VERSION 5.7 ;
  NOWIREEXTENSIONATPIN ON ;
  DIVIDERCHAR "/" ;
  BUSBITCHARS "[]" ;
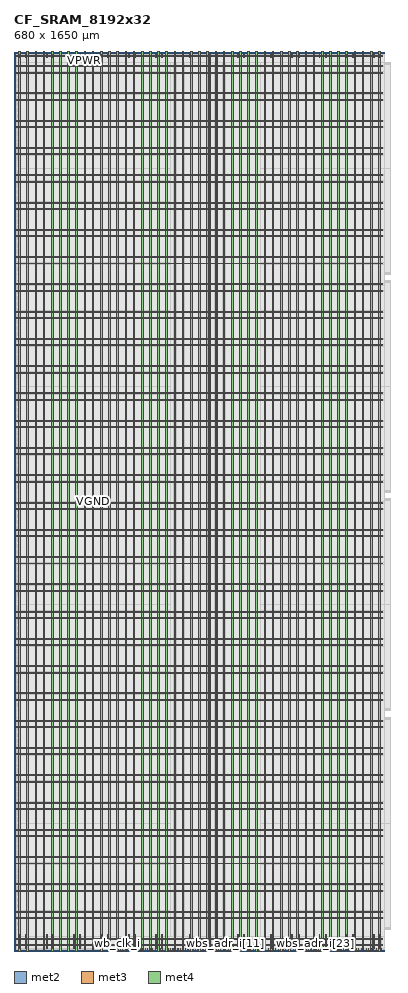
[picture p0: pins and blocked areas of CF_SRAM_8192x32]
MACRO CF_SRAM_8192x32
  CLASS BLOCK ;
  FOREIGN CF_SRAM_8192x32 ;
  ORIGIN 0.000 0.000 ;
  SIZE 680.000 BY 1650.000 ;
  PIN VGND
    DIRECTION INOUT ;
    USE GROUND ;
    PORT
      LAYER met2 ;
        RECT 20.940 5.200 22.700 29.860 ;
    END
    PORT
      LAYER met2 ;
        RECT 20.940 1638.310 22.700 1643.120 ;
    END
    PORT
      LAYER met2 ;
        RECT 70.940 5.200 72.700 29.860 ;
    END
    PORT
      LAYER met2 ;
        RECT 70.940 1638.310 72.700 1643.120 ;
    END
    PORT
      LAYER met2 ;
        RECT 120.940 5.200 122.700 29.860 ;
    END
    PORT
      LAYER met2 ;
        RECT 120.940 1638.310 122.700 1643.120 ;
    END
    PORT
      LAYER met2 ;
        RECT 170.940 5.200 172.700 29.860 ;
    END
    PORT
      LAYER met2 ;
        RECT 170.940 1638.310 172.700 1643.120 ;
    END
    PORT
      LAYER met2 ;
        RECT 220.940 5.200 222.700 29.860 ;
    END
    PORT
      LAYER met2 ;
        RECT 220.940 1638.310 222.700 1643.120 ;
    END
    PORT
      LAYER met2 ;
        RECT 270.940 5.200 272.700 29.720 ;
    END
    PORT
      LAYER met2 ;
        RECT 270.940 1638.450 272.700 1643.120 ;
    END
    PORT
      LAYER met2 ;
        RECT 320.940 5.200 322.700 29.860 ;
    END
    PORT
      LAYER met2 ;
        RECT 320.940 1638.310 322.700 1643.120 ;
    END
    PORT
      LAYER met2 ;
        RECT 370.940 5.200 372.700 1643.120 ;
    END
    PORT
      LAYER met2 ;
        RECT 420.940 5.200 422.700 29.720 ;
    END
    PORT
      LAYER met2 ;
        RECT 420.940 1638.450 422.700 1643.120 ;
    END
    PORT
      LAYER met2 ;
        RECT 470.940 5.200 472.700 29.720 ;
    END
    PORT
      LAYER met2 ;
        RECT 470.940 1638.450 472.700 1643.120 ;
    END
    PORT
      LAYER met2 ;
        RECT 520.940 5.200 522.700 29.860 ;
    END
    PORT
      LAYER met2 ;
        RECT 520.940 1638.310 522.700 1643.120 ;
    END
    PORT
      LAYER met2 ;
        RECT 570.940 5.200 572.700 29.860 ;
    END
    PORT
      LAYER met2 ;
        RECT 570.940 1638.310 572.700 1643.120 ;
    END
    PORT
      LAYER met2 ;
        RECT 620.940 5.200 622.700 29.860 ;
    END
    PORT
      LAYER met2 ;
        RECT 620.940 1638.310 622.700 1643.120 ;
    END
    PORT
      LAYER met2 ;
        RECT 670.940 5.200 672.700 29.860 ;
    END
    PORT
      LAYER met2 ;
        RECT 670.940 1638.310 672.700 1643.120 ;
    END
    PORT
      LAYER met3 ;
        RECT 4.820 21.320 675.060 23.080 ;
    END
    PORT
      LAYER met3 ;
        RECT 4.820 71.320 675.060 73.080 ;
    END
    PORT
      LAYER met3 ;
        RECT 4.820 121.320 675.060 123.080 ;
    END
    PORT
      LAYER met3 ;
        RECT 4.820 171.320 675.060 173.080 ;
    END
    PORT
      LAYER met3 ;
        RECT 4.820 221.320 675.060 223.080 ;
    END
    PORT
      LAYER met3 ;
        RECT 4.820 271.320 675.060 273.080 ;
    END
    PORT
      LAYER met3 ;
        RECT 4.820 321.320 675.060 323.080 ;
    END
    PORT
      LAYER met3 ;
        RECT 4.820 371.320 675.060 373.080 ;
    END
    PORT
      LAYER met3 ;
        RECT 4.820 421.320 675.060 423.080 ;
    END
    PORT
      LAYER met3 ;
        RECT 4.820 471.320 675.060 473.080 ;
    END
    PORT
      LAYER met3 ;
        RECT 4.820 521.320 675.060 523.080 ;
    END
    PORT
      LAYER met3 ;
        RECT 4.820 571.320 675.060 573.080 ;
    END
    PORT
      LAYER met3 ;
        RECT 4.820 621.320 675.060 623.080 ;
    END
    PORT
      LAYER met3 ;
        RECT 4.820 671.320 675.060 673.080 ;
    END
    PORT
      LAYER met3 ;
        RECT 4.820 721.320 675.060 723.080 ;
    END
    PORT
      LAYER met3 ;
        RECT 4.820 771.320 675.060 773.080 ;
    END
    PORT
      LAYER met3 ;
        RECT 4.820 821.320 675.060 823.080 ;
    END
    PORT
      LAYER met3 ;
        RECT 4.820 871.320 675.060 873.080 ;
    END
    PORT
      LAYER met3 ;
        RECT 4.820 921.320 675.060 923.080 ;
    END
    PORT
      LAYER met3 ;
        RECT 4.820 971.320 675.060 973.080 ;
    END
    PORT
      LAYER met3 ;
        RECT 4.820 1021.320 675.060 1023.080 ;
    END
    PORT
      LAYER met3 ;
        RECT 4.820 1071.320 675.060 1073.080 ;
    END
    PORT
      LAYER met3 ;
        RECT 4.820 1121.320 675.060 1123.080 ;
    END
    PORT
      LAYER met3 ;
        RECT 4.820 1171.320 675.060 1173.080 ;
    END
    PORT
      LAYER met3 ;
        RECT 4.820 1221.320 675.060 1223.080 ;
    END
    PORT
      LAYER met3 ;
        RECT 4.820 1271.320 675.060 1273.080 ;
    END
    PORT
      LAYER met3 ;
        RECT 4.820 1321.320 675.060 1323.080 ;
    END
    PORT
      LAYER met3 ;
        RECT 4.820 1371.320 675.060 1373.080 ;
    END
    PORT
      LAYER met3 ;
        RECT 4.820 1421.320 675.060 1423.080 ;
    END
    PORT
      LAYER met3 ;
        RECT 4.820 1471.320 675.060 1473.080 ;
    END
    PORT
      LAYER met3 ;
        RECT 4.820 1521.320 675.060 1523.080 ;
    END
    PORT
      LAYER met3 ;
        RECT 4.820 1571.320 675.060 1573.080 ;
    END
    PORT
      LAYER met3 ;
        RECT 4.820 1621.320 675.060 1623.080 ;
    END
    PORT
      LAYER met4 ;
        RECT 23.510 0.000 26.610 1650.000 ;
    END
    PORT
      LAYER met4 ;
        RECT 53.510 0.000 56.610 1650.000 ;
    END
    PORT
      LAYER met4 ;
        RECT 83.510 0.000 86.610 1650.000 ;
    END
    PORT
      LAYER met4 ;
        RECT 113.510 0.000 116.610 1650.000 ;
    END
    PORT
      LAYER met4 ;
        RECT 143.510 0.000 146.610 1650.000 ;
    END
    PORT
      LAYER met4 ;
        RECT 173.510 0.000 176.610 1650.000 ;
    END
    PORT
      LAYER met4 ;
        RECT 203.510 0.000 206.610 1650.000 ;
    END
    PORT
      LAYER met4 ;
        RECT 233.510 0.000 236.610 1650.000 ;
    END
    PORT
      LAYER met4 ;
        RECT 263.510 0.000 266.610 1650.000 ;
    END
    PORT
      LAYER met4 ;
        RECT 293.510 0.000 296.610 1650.000 ;
    END
    PORT
      LAYER met4 ;
        RECT 323.510 0.000 326.610 1650.000 ;
    END
    PORT
      LAYER met4 ;
        RECT 353.510 0.000 356.610 1650.000 ;
    END
    PORT
      LAYER met4 ;
        RECT 383.510 0.000 386.610 1650.000 ;
    END
    PORT
      LAYER met4 ;
        RECT 413.510 0.000 416.610 1650.000 ;
    END
    PORT
      LAYER met4 ;
        RECT 443.510 0.000 446.610 1650.000 ;
    END
    PORT
      LAYER met4 ;
        RECT 473.510 0.000 476.610 1650.000 ;
    END
    PORT
      LAYER met4 ;
        RECT 503.510 0.000 506.610 1650.000 ;
    END
    PORT
      LAYER met4 ;
        RECT 533.510 0.000 536.610 1650.000 ;
    END
    PORT
      LAYER met4 ;
        RECT 563.510 0.000 566.610 1650.000 ;
    END
    PORT
      LAYER met4 ;
        RECT 593.510 0.000 596.610 1650.000 ;
    END
    PORT
      LAYER met4 ;
        RECT 623.510 0.000 626.610 1650.000 ;
    END
    PORT
      LAYER met4 ;
        RECT 653.510 0.000 656.610 1650.000 ;
    END
    PORT
      LAYER met3 ;
        RECT 4.820 1639.380 675.060 1640.260 ;
    END
  END VGND
  PIN VPWR
    DIRECTION INOUT ;
    USE POWER ;
    PORT
      LAYER met2 ;
        RECT 9.180 5.200 10.940 29.720 ;
    END
    PORT
      LAYER met2 ;
        RECT 9.180 1638.450 10.940 1643.120 ;
    END
    PORT
      LAYER met2 ;
        RECT 59.180 5.200 60.940 29.860 ;
    END
    PORT
      LAYER met2 ;
        RECT 59.180 1638.310 60.940 1643.120 ;
    END
    PORT
      LAYER met2 ;
        RECT 109.180 5.200 110.940 29.860 ;
    END
    PORT
      LAYER met2 ;
        RECT 109.180 1638.310 110.940 1643.120 ;
    END
    PORT
      LAYER met2 ;
        RECT 159.180 5.200 160.940 29.860 ;
    END
    PORT
      LAYER met2 ;
        RECT 159.180 1638.310 160.940 1643.120 ;
    END
    PORT
      LAYER met2 ;
        RECT 209.180 5.200 210.940 29.860 ;
    END
    PORT
      LAYER met2 ;
        RECT 209.180 1638.310 210.940 1643.120 ;
    END
    PORT
      LAYER met2 ;
        RECT 259.180 5.200 260.940 29.720 ;
    END
    PORT
      LAYER met2 ;
        RECT 259.180 1638.450 260.940 1643.120 ;
    END
    PORT
      LAYER met2 ;
        RECT 309.180 5.200 310.940 29.860 ;
    END
    PORT
      LAYER met2 ;
        RECT 309.180 1638.310 310.940 1643.120 ;
    END
    PORT
      LAYER met2 ;
        RECT 359.180 5.200 360.940 1643.120 ;
    END
    PORT
      LAYER met2 ;
        RECT 409.180 5.200 410.940 29.860 ;
    END
    PORT
      LAYER met2 ;
        RECT 409.180 1638.310 410.940 1643.120 ;
    END
    PORT
      LAYER met2 ;
        RECT 459.180 5.200 460.940 29.720 ;
    END
    PORT
      LAYER met2 ;
        RECT 459.180 1638.450 460.940 1643.120 ;
    END
    PORT
      LAYER met2 ;
        RECT 509.180 5.200 510.940 29.860 ;
    END
    PORT
      LAYER met2 ;
        RECT 509.180 1638.310 510.940 1643.120 ;
    END
    PORT
      LAYER met2 ;
        RECT 559.180 5.200 560.940 29.860 ;
    END
    PORT
      LAYER met2 ;
        RECT 559.180 1638.310 560.940 1643.120 ;
    END
    PORT
      LAYER met2 ;
        RECT 609.180 5.200 610.940 29.860 ;
    END
    PORT
      LAYER met2 ;
        RECT 609.180 1638.310 610.940 1643.120 ;
    END
    PORT
      LAYER met2 ;
        RECT 659.180 5.200 660.940 29.860 ;
    END
    PORT
      LAYER met2 ;
        RECT 659.180 1638.310 660.940 1643.120 ;
    END
    PORT
      LAYER met3 ;
        RECT 4.820 9.560 675.060 11.320 ;
    END
    PORT
      LAYER met3 ;
        RECT 4.820 59.560 675.060 61.320 ;
    END
    PORT
      LAYER met3 ;
        RECT 4.820 109.560 675.060 111.320 ;
    END
    PORT
      LAYER met3 ;
        RECT 4.820 159.560 675.060 161.320 ;
    END
    PORT
      LAYER met3 ;
        RECT 4.820 209.560 675.060 211.320 ;
    END
    PORT
      LAYER met3 ;
        RECT 4.820 259.560 675.060 261.320 ;
    END
    PORT
      LAYER met3 ;
        RECT 4.820 309.560 675.060 311.320 ;
    END
    PORT
      LAYER met3 ;
        RECT 4.820 359.560 675.060 361.320 ;
    END
    PORT
      LAYER met3 ;
        RECT 4.820 409.560 675.060 411.320 ;
    END
    PORT
      LAYER met3 ;
        RECT 4.820 459.560 675.060 461.320 ;
    END
    PORT
      LAYER met3 ;
        RECT 4.820 509.560 675.060 511.320 ;
    END
    PORT
      LAYER met3 ;
        RECT 4.820 559.560 675.060 561.320 ;
    END
    PORT
      LAYER met3 ;
        RECT 4.820 609.560 675.060 611.320 ;
    END
    PORT
      LAYER met3 ;
        RECT 4.820 659.560 675.060 661.320 ;
    END
    PORT
      LAYER met3 ;
        RECT 4.820 709.560 675.060 711.320 ;
    END
    PORT
      LAYER met3 ;
        RECT 4.820 759.560 675.060 761.320 ;
    END
    PORT
      LAYER met3 ;
        RECT 4.820 809.560 675.060 811.320 ;
    END
    PORT
      LAYER met3 ;
        RECT 4.820 859.560 675.060 861.320 ;
    END
    PORT
      LAYER met3 ;
        RECT 4.820 909.560 675.060 911.320 ;
    END
    PORT
      LAYER met3 ;
        RECT 4.820 959.560 675.060 961.320 ;
    END
    PORT
      LAYER met3 ;
        RECT 4.820 1009.560 675.060 1011.320 ;
    END
    PORT
      LAYER met3 ;
        RECT 4.820 1059.560 675.060 1061.320 ;
    END
    PORT
      LAYER met3 ;
        RECT 4.820 1109.560 675.060 1111.320 ;
    END
    PORT
      LAYER met3 ;
        RECT 4.820 1159.560 675.060 1161.320 ;
    END
    PORT
      LAYER met3 ;
        RECT 4.820 1209.560 675.060 1211.320 ;
    END
    PORT
      LAYER met3 ;
        RECT 4.820 1259.560 675.060 1261.320 ;
    END
    PORT
      LAYER met3 ;
        RECT 4.820 1309.560 675.060 1311.320 ;
    END
    PORT
      LAYER met3 ;
        RECT 4.820 1359.560 675.060 1361.320 ;
    END
    PORT
      LAYER met3 ;
        RECT 4.820 1409.560 675.060 1411.320 ;
    END
    PORT
      LAYER met3 ;
        RECT 4.820 1459.560 675.060 1461.320 ;
    END
    PORT
      LAYER met3 ;
        RECT 4.820 1509.560 675.060 1511.320 ;
    END
    PORT
      LAYER met3 ;
        RECT 4.820 1559.560 675.060 1561.320 ;
    END
    PORT
      LAYER met3 ;
        RECT 4.820 1609.560 675.060 1611.320 ;
    END
    PORT
      LAYER met4 ;
        RECT 8.510 0.000 11.610 1650.000 ;
    END
    PORT
      LAYER met4 ;
        RECT 38.510 0.000 41.610 1650.000 ;
    END
    PORT
      LAYER met4 ;
        RECT 68.510 0.000 71.610 1650.000 ;
    END
    PORT
      LAYER met4 ;
        RECT 98.510 0.000 101.610 1650.000 ;
    END
    PORT
      LAYER met4 ;
        RECT 128.510 0.000 131.610 1650.000 ;
    END
    PORT
      LAYER met4 ;
        RECT 158.510 0.000 161.610 1650.000 ;
    END
    PORT
      LAYER met4 ;
        RECT 188.510 0.000 191.610 1650.000 ;
    END
    PORT
      LAYER met4 ;
        RECT 218.510 0.000 221.610 1650.000 ;
    END
    PORT
      LAYER met4 ;
        RECT 248.510 0.000 251.610 1650.000 ;
    END
    PORT
      LAYER met4 ;
        RECT 278.510 0.000 281.610 1650.000 ;
    END
    PORT
      LAYER met4 ;
        RECT 308.510 0.000 311.610 1650.000 ;
    END
    PORT
      LAYER met4 ;
        RECT 338.510 0.000 341.610 1650.000 ;
    END
    PORT
      LAYER met4 ;
        RECT 368.510 0.000 371.610 1650.000 ;
    END
    PORT
      LAYER met4 ;
        RECT 398.510 0.000 401.610 1650.000 ;
    END
    PORT
      LAYER met4 ;
        RECT 428.510 0.000 431.610 1650.000 ;
    END
    PORT
      LAYER met4 ;
        RECT 458.510 0.000 461.610 1650.000 ;
    END
    PORT
      LAYER met4 ;
        RECT 488.510 0.000 491.610 1650.000 ;
    END
    PORT
      LAYER met4 ;
        RECT 518.510 0.000 521.610 1650.000 ;
    END
    PORT
      LAYER met4 ;
        RECT 548.510 0.000 551.610 1650.000 ;
    END
    PORT
      LAYER met4 ;
        RECT 578.510 0.000 581.610 1650.000 ;
    END
    PORT
      LAYER met4 ;
        RECT 608.510 0.000 611.610 1650.000 ;
    END
    PORT
      LAYER met4 ;
        RECT 638.510 0.000 641.610 1650.000 ;
    END
    PORT
      LAYER met4 ;
        RECT 668.510 0.000 671.610 1650.000 ;
    END
    PORT
      LAYER met3 ;
        RECT 4.820 1640.740 675.060 1641.620 ;
    END
  END VPWR
  PIN wb_clk_i
    DIRECTION INPUT ;
    USE SIGNAL ;
    ANTENNAGATEAREA 1.286700 ;
    ANTENNADIFFAREA 0.434700 ;
    PORT
      LAYER met2 ;
        RECT 190.070 0.000 190.350 4.000 ;
    END
  END wb_clk_i
  PIN wb_rst_i
    DIRECTION INPUT ;
    USE SIGNAL ;
    ANTENNAGATEAREA 0.196500 ;
    PORT
      LAYER met2 ;
        RECT 194.670 0.000 194.950 4.000 ;
    END
  END wb_rst_i
  PIN wbs_ack_o
    DIRECTION OUTPUT ;
    USE SIGNAL ;
    ANTENNADIFFAREA 2.673000 ;
    PORT
      LAYER met2 ;
        RECT 199.270 0.000 199.550 4.000 ;
    END
  END wbs_ack_o
  PIN wbs_adr_i[0]
    DIRECTION INPUT ;
    USE SIGNAL ;
    PORT
      LAYER met2 ;
        RECT 217.670 0.000 217.950 4.000 ;
    END
  END wbs_adr_i[0]
  PIN wbs_adr_i[10]
    DIRECTION INPUT ;
    USE SIGNAL ;
    ANTENNAGATEAREA 0.126000 ;
    PORT
      LAYER met2 ;
        RECT 374.070 0.000 374.350 4.000 ;
    END
  END wbs_adr_i[10]
  PIN wbs_adr_i[11]
    DIRECTION INPUT ;
    USE SIGNAL ;
    ANTENNAGATEAREA 0.126000 ;
    PORT
      LAYER met2 ;
        RECT 387.870 0.000 388.150 4.000 ;
    END
  END wbs_adr_i[11]
  PIN wbs_adr_i[12]
    DIRECTION INPUT ;
    USE SIGNAL ;
    ANTENNAGATEAREA 0.126000 ;
    PORT
      LAYER met2 ;
        RECT 401.670 0.000 401.950 4.000 ;
    END
  END wbs_adr_i[12]
  PIN wbs_adr_i[13]
    DIRECTION INPUT ;
    USE SIGNAL ;
    ANTENNAGATEAREA 0.126000 ;
    PORT
      LAYER met2 ;
        RECT 415.470 0.000 415.750 4.000 ;
    END
  END wbs_adr_i[13]
  PIN wbs_adr_i[14]
    DIRECTION INPUT ;
    USE SIGNAL ;
    ANTENNAGATEAREA 0.126000 ;
    PORT
      LAYER met2 ;
        RECT 429.270 0.000 429.550 4.000 ;
    END
  END wbs_adr_i[14]
  PIN wbs_adr_i[15]
    DIRECTION INPUT ;
    USE SIGNAL ;
    PORT
      LAYER met2 ;
        RECT 443.070 0.000 443.350 4.000 ;
    END
  END wbs_adr_i[15]
  PIN wbs_adr_i[16]
    DIRECTION INPUT ;
    USE SIGNAL ;
    PORT
      LAYER met2 ;
        RECT 456.870 0.000 457.150 4.000 ;
    END
  END wbs_adr_i[16]
  PIN wbs_adr_i[17]
    DIRECTION INPUT ;
    USE SIGNAL ;
    PORT
      LAYER met2 ;
        RECT 470.670 0.000 470.950 4.000 ;
    END
  END wbs_adr_i[17]
  PIN wbs_adr_i[18]
    DIRECTION INPUT ;
    USE SIGNAL ;
    PORT
      LAYER met2 ;
        RECT 484.470 0.000 484.750 4.000 ;
    END
  END wbs_adr_i[18]
  PIN wbs_adr_i[19]
    DIRECTION INPUT ;
    USE SIGNAL ;
    PORT
      LAYER met2 ;
        RECT 498.270 0.000 498.550 4.000 ;
    END
  END wbs_adr_i[19]
  PIN wbs_adr_i[1]
    DIRECTION INPUT ;
    USE SIGNAL ;
    PORT
      LAYER met2 ;
        RECT 236.070 0.000 236.350 4.000 ;
    END
  END wbs_adr_i[1]
  PIN wbs_adr_i[20]
    DIRECTION INPUT ;
    USE SIGNAL ;
    PORT
      LAYER met2 ;
        RECT 512.070 0.000 512.350 4.000 ;
    END
  END wbs_adr_i[20]
  PIN wbs_adr_i[21]
    DIRECTION INPUT ;
    USE SIGNAL ;
    PORT
      LAYER met2 ;
        RECT 525.870 0.000 526.150 4.000 ;
    END
  END wbs_adr_i[21]
  PIN wbs_adr_i[22]
    DIRECTION INPUT ;
    USE SIGNAL ;
    PORT
      LAYER met2 ;
        RECT 539.670 0.000 539.950 4.000 ;
    END
  END wbs_adr_i[22]
  PIN wbs_adr_i[23]
    DIRECTION INPUT ;
    USE SIGNAL ;
    PORT
      LAYER met2 ;
        RECT 553.470 0.000 553.750 4.000 ;
    END
  END wbs_adr_i[23]
  PIN wbs_adr_i[24]
    DIRECTION INPUT ;
    USE SIGNAL ;
    PORT
      LAYER met2 ;
        RECT 567.270 0.000 567.550 4.000 ;
    END
  END wbs_adr_i[24]
  PIN wbs_adr_i[25]
    DIRECTION INPUT ;
    USE SIGNAL ;
    PORT
      LAYER met2 ;
        RECT 581.070 0.000 581.350 4.000 ;
    END
  END wbs_adr_i[25]
  PIN wbs_adr_i[26]
    DIRECTION INPUT ;
    USE SIGNAL ;
    PORT
      LAYER met2 ;
        RECT 594.870 0.000 595.150 4.000 ;
    END
  END wbs_adr_i[26]
  PIN wbs_adr_i[27]
    DIRECTION INPUT ;
    USE SIGNAL ;
    PORT
      LAYER met2 ;
        RECT 608.670 0.000 608.950 4.000 ;
    END
  END wbs_adr_i[27]
  PIN wbs_adr_i[28]
    DIRECTION INPUT ;
    USE SIGNAL ;
    PORT
      LAYER met2 ;
        RECT 622.470 0.000 622.750 4.000 ;
    END
  END wbs_adr_i[28]
  PIN wbs_adr_i[29]
    DIRECTION INPUT ;
    USE SIGNAL ;
    PORT
      LAYER met2 ;
        RECT 636.270 0.000 636.550 4.000 ;
    END
  END wbs_adr_i[29]
  PIN wbs_adr_i[2]
    DIRECTION INPUT ;
    USE SIGNAL ;
    ANTENNAGATEAREA 0.126000 ;
    PORT
      LAYER met2 ;
        RECT 254.470 0.000 254.750 4.000 ;
    END
  END wbs_adr_i[2]
  PIN wbs_adr_i[30]
    DIRECTION INPUT ;
    USE SIGNAL ;
    PORT
      LAYER met2 ;
        RECT 650.070 0.000 650.350 4.000 ;
    END
  END wbs_adr_i[30]
  PIN wbs_adr_i[31]
    DIRECTION INPUT ;
    USE SIGNAL ;
    PORT
      LAYER met2 ;
        RECT 663.870 0.000 664.150 4.000 ;
    END
  END wbs_adr_i[31]
  PIN wbs_adr_i[3]
    DIRECTION INPUT ;
    USE SIGNAL ;
    ANTENNAGATEAREA 0.126000 ;
    PORT
      LAYER met2 ;
        RECT 272.870 0.000 273.150 4.000 ;
    END
  END wbs_adr_i[3]
  PIN wbs_adr_i[4]
    DIRECTION INPUT ;
    USE SIGNAL ;
    ANTENNAGATEAREA 0.126000 ;
    PORT
      LAYER met2 ;
        RECT 291.270 0.000 291.550 4.000 ;
    END
  END wbs_adr_i[4]
  PIN wbs_adr_i[5]
    DIRECTION INPUT ;
    USE SIGNAL ;
    ANTENNAGATEAREA 0.126000 ;
    PORT
      LAYER met2 ;
        RECT 305.070 0.000 305.350 4.000 ;
    END
  END wbs_adr_i[5]
  PIN wbs_adr_i[6]
    DIRECTION INPUT ;
    USE SIGNAL ;
    ANTENNAGATEAREA 0.126000 ;
    PORT
      LAYER met2 ;
        RECT 318.870 0.000 319.150 4.000 ;
    END
  END wbs_adr_i[6]
  PIN wbs_adr_i[7]
    DIRECTION INPUT ;
    USE SIGNAL ;
    ANTENNAGATEAREA 0.126000 ;
    PORT
      LAYER met2 ;
        RECT 332.670 0.000 332.950 4.000 ;
    END
  END wbs_adr_i[7]
  PIN wbs_adr_i[8]
    DIRECTION INPUT ;
    USE SIGNAL ;
    ANTENNAGATEAREA 0.126000 ;
    PORT
      LAYER met2 ;
        RECT 346.470 0.000 346.750 4.000 ;
    END
  END wbs_adr_i[8]
  PIN wbs_adr_i[9]
    DIRECTION INPUT ;
    USE SIGNAL ;
    ANTENNAGATEAREA 0.126000 ;
    PORT
      LAYER met2 ;
        RECT 360.270 0.000 360.550 4.000 ;
    END
  END wbs_adr_i[9]
  PIN wbs_cyc_i
    DIRECTION INPUT ;
    USE SIGNAL ;
    ANTENNAGATEAREA 0.126000 ;
    PORT
      LAYER met2 ;
        RECT 203.870 0.000 204.150 4.000 ;
    END
  END wbs_cyc_i
  PIN wbs_dat_i[0]
    DIRECTION INPUT ;
    USE SIGNAL ;
    ANTENNAGATEAREA 0.126000 ;
    PORT
      LAYER met2 ;
        RECT 222.270 0.000 222.550 4.000 ;
    END
  END wbs_dat_i[0]
  PIN wbs_dat_i[10]
    DIRECTION INPUT ;
    USE SIGNAL ;
    ANTENNAGATEAREA 0.126000 ;
    PORT
      LAYER met2 ;
        RECT 378.670 0.000 378.950 4.000 ;
    END
  END wbs_dat_i[10]
  PIN wbs_dat_i[11]
    DIRECTION INPUT ;
    USE SIGNAL ;
    ANTENNAGATEAREA 0.126000 ;
    PORT
      LAYER met2 ;
        RECT 392.470 0.000 392.750 4.000 ;
    END
  END wbs_dat_i[11]
  PIN wbs_dat_i[12]
    DIRECTION INPUT ;
    USE SIGNAL ;
    ANTENNAGATEAREA 0.126000 ;
    PORT
      LAYER met2 ;
        RECT 406.270 0.000 406.550 4.000 ;
    END
  END wbs_dat_i[12]
  PIN wbs_dat_i[13]
    DIRECTION INPUT ;
    USE SIGNAL ;
    ANTENNAGATEAREA 0.126000 ;
    PORT
      LAYER met2 ;
        RECT 420.070 0.000 420.350 4.000 ;
    END
  END wbs_dat_i[13]
  PIN wbs_dat_i[14]
    DIRECTION INPUT ;
    USE SIGNAL ;
    ANTENNAGATEAREA 0.126000 ;
    PORT
      LAYER met2 ;
        RECT 433.870 0.000 434.150 4.000 ;
    END
  END wbs_dat_i[14]
  PIN wbs_dat_i[15]
    DIRECTION INPUT ;
    USE SIGNAL ;
    ANTENNAGATEAREA 0.126000 ;
    PORT
      LAYER met2 ;
        RECT 447.670 0.000 447.950 4.000 ;
    END
  END wbs_dat_i[15]
  PIN wbs_dat_i[16]
    DIRECTION INPUT ;
    USE SIGNAL ;
    ANTENNAGATEAREA 0.126000 ;
    PORT
      LAYER met2 ;
        RECT 461.470 0.000 461.750 4.000 ;
    END
  END wbs_dat_i[16]
  PIN wbs_dat_i[17]
    DIRECTION INPUT ;
    USE SIGNAL ;
    ANTENNAGATEAREA 0.126000 ;
    PORT
      LAYER met2 ;
        RECT 475.270 0.000 475.550 4.000 ;
    END
  END wbs_dat_i[17]
  PIN wbs_dat_i[18]
    DIRECTION INPUT ;
    USE SIGNAL ;
    ANTENNAGATEAREA 0.126000 ;
    PORT
      LAYER met2 ;
        RECT 489.070 0.000 489.350 4.000 ;
    END
  END wbs_dat_i[18]
  PIN wbs_dat_i[19]
    DIRECTION INPUT ;
    USE SIGNAL ;
    ANTENNAGATEAREA 0.126000 ;
    PORT
      LAYER met2 ;
        RECT 502.870 0.000 503.150 4.000 ;
    END
  END wbs_dat_i[19]
  PIN wbs_dat_i[1]
    DIRECTION INPUT ;
    USE SIGNAL ;
    ANTENNAGATEAREA 0.126000 ;
    PORT
      LAYER met2 ;
        RECT 240.670 0.000 240.950 4.000 ;
    END
  END wbs_dat_i[1]
  PIN wbs_dat_i[20]
    DIRECTION INPUT ;
    USE SIGNAL ;
    ANTENNAGATEAREA 0.126000 ;
    PORT
      LAYER met2 ;
        RECT 516.670 0.000 516.950 4.000 ;
    END
  END wbs_dat_i[20]
  PIN wbs_dat_i[21]
    DIRECTION INPUT ;
    USE SIGNAL ;
    ANTENNAGATEAREA 0.126000 ;
    PORT
      LAYER met2 ;
        RECT 530.470 0.000 530.750 4.000 ;
    END
  END wbs_dat_i[21]
  PIN wbs_dat_i[22]
    DIRECTION INPUT ;
    USE SIGNAL ;
    ANTENNAGATEAREA 0.126000 ;
    PORT
      LAYER met2 ;
        RECT 544.270 0.000 544.550 4.000 ;
    END
  END wbs_dat_i[22]
  PIN wbs_dat_i[23]
    DIRECTION INPUT ;
    USE SIGNAL ;
    ANTENNAGATEAREA 0.126000 ;
    PORT
      LAYER met2 ;
        RECT 558.070 0.000 558.350 4.000 ;
    END
  END wbs_dat_i[23]
  PIN wbs_dat_i[24]
    DIRECTION INPUT ;
    USE SIGNAL ;
    ANTENNAGATEAREA 0.126000 ;
    PORT
      LAYER met2 ;
        RECT 571.870 0.000 572.150 4.000 ;
    END
  END wbs_dat_i[24]
  PIN wbs_dat_i[25]
    DIRECTION INPUT ;
    USE SIGNAL ;
    ANTENNAGATEAREA 0.126000 ;
    PORT
      LAYER met2 ;
        RECT 585.670 0.000 585.950 4.000 ;
    END
  END wbs_dat_i[25]
  PIN wbs_dat_i[26]
    DIRECTION INPUT ;
    USE SIGNAL ;
    ANTENNAGATEAREA 0.126000 ;
    PORT
      LAYER met2 ;
        RECT 599.470 0.000 599.750 4.000 ;
    END
  END wbs_dat_i[26]
  PIN wbs_dat_i[27]
    DIRECTION INPUT ;
    USE SIGNAL ;
    ANTENNAGATEAREA 0.126000 ;
    PORT
      LAYER met2 ;
        RECT 613.270 0.000 613.550 4.000 ;
    END
  END wbs_dat_i[27]
  PIN wbs_dat_i[28]
    DIRECTION INPUT ;
    USE SIGNAL ;
    ANTENNAGATEAREA 0.126000 ;
    PORT
      LAYER met2 ;
        RECT 627.070 0.000 627.350 4.000 ;
    END
  END wbs_dat_i[28]
  PIN wbs_dat_i[29]
    DIRECTION INPUT ;
    USE SIGNAL ;
    ANTENNAGATEAREA 0.126000 ;
    PORT
      LAYER met2 ;
        RECT 640.870 0.000 641.150 4.000 ;
    END
  END wbs_dat_i[29]
  PIN wbs_dat_i[2]
    DIRECTION INPUT ;
    USE SIGNAL ;
    ANTENNAGATEAREA 0.126000 ;
    PORT
      LAYER met2 ;
        RECT 259.070 0.000 259.350 4.000 ;
    END
  END wbs_dat_i[2]
  PIN wbs_dat_i[30]
    DIRECTION INPUT ;
    USE SIGNAL ;
    ANTENNAGATEAREA 0.126000 ;
    PORT
      LAYER met2 ;
        RECT 654.670 0.000 654.950 4.000 ;
    END
  END wbs_dat_i[30]
  PIN wbs_dat_i[31]
    DIRECTION INPUT ;
    USE SIGNAL ;
    ANTENNAGATEAREA 0.126000 ;
    PORT
      LAYER met2 ;
        RECT 668.470 0.000 668.750 4.000 ;
    END
  END wbs_dat_i[31]
  PIN wbs_dat_i[3]
    DIRECTION INPUT ;
    USE SIGNAL ;
    ANTENNAGATEAREA 0.126000 ;
    PORT
      LAYER met2 ;
        RECT 277.470 0.000 277.750 4.000 ;
    END
  END wbs_dat_i[3]
  PIN wbs_dat_i[4]
    DIRECTION INPUT ;
    USE SIGNAL ;
    ANTENNAGATEAREA 0.126000 ;
    PORT
      LAYER met2 ;
        RECT 295.870 0.000 296.150 4.000 ;
    END
  END wbs_dat_i[4]
  PIN wbs_dat_i[5]
    DIRECTION INPUT ;
    USE SIGNAL ;
    ANTENNAGATEAREA 0.126000 ;
    PORT
      LAYER met2 ;
        RECT 309.670 0.000 309.950 4.000 ;
    END
  END wbs_dat_i[5]
  PIN wbs_dat_i[6]
    DIRECTION INPUT ;
    USE SIGNAL ;
    ANTENNAGATEAREA 0.126000 ;
    PORT
      LAYER met2 ;
        RECT 323.470 0.000 323.750 4.000 ;
    END
  END wbs_dat_i[6]
  PIN wbs_dat_i[7]
    DIRECTION INPUT ;
    USE SIGNAL ;
    ANTENNAGATEAREA 0.126000 ;
    PORT
      LAYER met2 ;
        RECT 337.270 0.000 337.550 4.000 ;
    END
  END wbs_dat_i[7]
  PIN wbs_dat_i[8]
    DIRECTION INPUT ;
    USE SIGNAL ;
    ANTENNAGATEAREA 0.126000 ;
    PORT
      LAYER met2 ;
        RECT 351.070 0.000 351.350 4.000 ;
    END
  END wbs_dat_i[8]
  PIN wbs_dat_i[9]
    DIRECTION INPUT ;
    USE SIGNAL ;
    ANTENNAGATEAREA 0.126000 ;
    PORT
      LAYER met2 ;
        RECT 364.870 0.000 365.150 4.000 ;
    END
  END wbs_dat_i[9]
  PIN wbs_dat_o[0]
    DIRECTION OUTPUT ;
    USE SIGNAL ;
    ANTENNADIFFAREA 2.673000 ;
    PORT
      LAYER met2 ;
        RECT 226.870 0.000 227.150 4.000 ;
    END
  END wbs_dat_o[0]
  PIN wbs_dat_o[10]
    DIRECTION OUTPUT ;
    USE SIGNAL ;
    ANTENNADIFFAREA 2.673000 ;
    PORT
      LAYER met2 ;
        RECT 383.270 0.000 383.550 4.000 ;
    END
  END wbs_dat_o[10]
  PIN wbs_dat_o[11]
    DIRECTION OUTPUT ;
    USE SIGNAL ;
    ANTENNADIFFAREA 2.673000 ;
    PORT
      LAYER met2 ;
        RECT 397.070 0.000 397.350 4.000 ;
    END
  END wbs_dat_o[11]
  PIN wbs_dat_o[12]
    DIRECTION OUTPUT ;
    USE SIGNAL ;
    ANTENNADIFFAREA 2.673000 ;
    PORT
      LAYER met2 ;
        RECT 410.870 0.000 411.150 4.000 ;
    END
  END wbs_dat_o[12]
  PIN wbs_dat_o[13]
    DIRECTION OUTPUT ;
    USE SIGNAL ;
    ANTENNADIFFAREA 2.673000 ;
    PORT
      LAYER met2 ;
        RECT 424.670 0.000 424.950 4.000 ;
    END
  END wbs_dat_o[13]
  PIN wbs_dat_o[14]
    DIRECTION OUTPUT ;
    USE SIGNAL ;
    ANTENNADIFFAREA 2.673000 ;
    PORT
      LAYER met2 ;
        RECT 438.470 0.000 438.750 4.000 ;
    END
  END wbs_dat_o[14]
  PIN wbs_dat_o[15]
    DIRECTION OUTPUT ;
    USE SIGNAL ;
    ANTENNADIFFAREA 2.673000 ;
    PORT
      LAYER met2 ;
        RECT 452.270 0.000 452.550 4.000 ;
    END
  END wbs_dat_o[15]
  PIN wbs_dat_o[16]
    DIRECTION OUTPUT ;
    USE SIGNAL ;
    ANTENNADIFFAREA 2.673000 ;
    PORT
      LAYER met2 ;
        RECT 466.070 0.000 466.350 4.000 ;
    END
  END wbs_dat_o[16]
  PIN wbs_dat_o[17]
    DIRECTION OUTPUT ;
    USE SIGNAL ;
    ANTENNADIFFAREA 2.673000 ;
    PORT
      LAYER met2 ;
        RECT 479.870 0.000 480.150 4.000 ;
    END
  END wbs_dat_o[17]
  PIN wbs_dat_o[18]
    DIRECTION OUTPUT ;
    USE SIGNAL ;
    ANTENNADIFFAREA 2.673000 ;
    PORT
      LAYER met2 ;
        RECT 493.670 0.000 493.950 4.000 ;
    END
  END wbs_dat_o[18]
  PIN wbs_dat_o[19]
    DIRECTION OUTPUT ;
    USE SIGNAL ;
    ANTENNADIFFAREA 2.673000 ;
    PORT
      LAYER met2 ;
        RECT 507.470 0.000 507.750 4.000 ;
    END
  END wbs_dat_o[19]
  PIN wbs_dat_o[1]
    DIRECTION OUTPUT ;
    USE SIGNAL ;
    ANTENNADIFFAREA 2.673000 ;
    PORT
      LAYER met2 ;
        RECT 245.270 0.000 245.550 4.000 ;
    END
  END wbs_dat_o[1]
  PIN wbs_dat_o[20]
    DIRECTION OUTPUT ;
    USE SIGNAL ;
    ANTENNADIFFAREA 2.673000 ;
    PORT
      LAYER met2 ;
        RECT 521.270 0.000 521.550 4.000 ;
    END
  END wbs_dat_o[20]
  PIN wbs_dat_o[21]
    DIRECTION OUTPUT ;
    USE SIGNAL ;
    ANTENNADIFFAREA 2.673000 ;
    PORT
      LAYER met2 ;
        RECT 535.070 0.000 535.350 4.000 ;
    END
  END wbs_dat_o[21]
  PIN wbs_dat_o[22]
    DIRECTION OUTPUT ;
    USE SIGNAL ;
    ANTENNADIFFAREA 2.673000 ;
    PORT
      LAYER met2 ;
        RECT 548.870 0.000 549.150 4.000 ;
    END
  END wbs_dat_o[22]
  PIN wbs_dat_o[23]
    DIRECTION OUTPUT ;
    USE SIGNAL ;
    ANTENNADIFFAREA 2.673000 ;
    PORT
      LAYER met2 ;
        RECT 562.670 0.000 562.950 4.000 ;
    END
  END wbs_dat_o[23]
  PIN wbs_dat_o[24]
    DIRECTION OUTPUT ;
    USE SIGNAL ;
    ANTENNADIFFAREA 2.673000 ;
    PORT
      LAYER met2 ;
        RECT 576.470 0.000 576.750 4.000 ;
    END
  END wbs_dat_o[24]
  PIN wbs_dat_o[25]
    DIRECTION OUTPUT ;
    USE SIGNAL ;
    ANTENNADIFFAREA 2.673000 ;
    PORT
      LAYER met2 ;
        RECT 590.270 0.000 590.550 4.000 ;
    END
  END wbs_dat_o[25]
  PIN wbs_dat_o[26]
    DIRECTION OUTPUT ;
    USE SIGNAL ;
    ANTENNADIFFAREA 2.673000 ;
    PORT
      LAYER met2 ;
        RECT 604.070 0.000 604.350 4.000 ;
    END
  END wbs_dat_o[26]
  PIN wbs_dat_o[27]
    DIRECTION OUTPUT ;
    USE SIGNAL ;
    ANTENNADIFFAREA 2.673000 ;
    PORT
      LAYER met2 ;
        RECT 617.870 0.000 618.150 4.000 ;
    END
  END wbs_dat_o[27]
  PIN wbs_dat_o[28]
    DIRECTION OUTPUT ;
    USE SIGNAL ;
    ANTENNADIFFAREA 2.673000 ;
    PORT
      LAYER met2 ;
        RECT 631.670 0.000 631.950 4.000 ;
    END
  END wbs_dat_o[28]
  PIN wbs_dat_o[29]
    DIRECTION OUTPUT ;
    USE SIGNAL ;
    ANTENNADIFFAREA 2.673000 ;
    PORT
      LAYER met2 ;
        RECT 645.470 0.000 645.750 4.000 ;
    END
  END wbs_dat_o[29]
  PIN wbs_dat_o[2]
    DIRECTION OUTPUT ;
    USE SIGNAL ;
    ANTENNADIFFAREA 2.673000 ;
    PORT
      LAYER met2 ;
        RECT 263.670 0.000 263.950 4.000 ;
    END
  END wbs_dat_o[2]
  PIN wbs_dat_o[30]
    DIRECTION OUTPUT ;
    USE SIGNAL ;
    ANTENNADIFFAREA 2.673000 ;
    PORT
      LAYER met2 ;
        RECT 659.270 0.000 659.550 4.000 ;
    END
  END wbs_dat_o[30]
  PIN wbs_dat_o[31]
    DIRECTION OUTPUT ;
    USE SIGNAL ;
    ANTENNADIFFAREA 2.673000 ;
    PORT
      LAYER met2 ;
        RECT 673.070 0.000 673.350 4.000 ;
    END
  END wbs_dat_o[31]
  PIN wbs_dat_o[3]
    DIRECTION OUTPUT ;
    USE SIGNAL ;
    ANTENNADIFFAREA 2.673000 ;
    PORT
      LAYER met2 ;
        RECT 282.070 0.000 282.350 4.000 ;
    END
  END wbs_dat_o[3]
  PIN wbs_dat_o[4]
    DIRECTION OUTPUT ;
    USE SIGNAL ;
    ANTENNADIFFAREA 2.673000 ;
    PORT
      LAYER met2 ;
        RECT 300.470 0.000 300.750 4.000 ;
    END
  END wbs_dat_o[4]
  PIN wbs_dat_o[5]
    DIRECTION OUTPUT ;
    USE SIGNAL ;
    ANTENNADIFFAREA 2.673000 ;
    PORT
      LAYER met2 ;
        RECT 314.270 0.000 314.550 4.000 ;
    END
  END wbs_dat_o[5]
  PIN wbs_dat_o[6]
    DIRECTION OUTPUT ;
    USE SIGNAL ;
    ANTENNADIFFAREA 2.673000 ;
    PORT
      LAYER met2 ;
        RECT 328.070 0.000 328.350 4.000 ;
    END
  END wbs_dat_o[6]
  PIN wbs_dat_o[7]
    DIRECTION OUTPUT ;
    USE SIGNAL ;
    ANTENNADIFFAREA 2.673000 ;
    PORT
      LAYER met2 ;
        RECT 341.870 0.000 342.150 4.000 ;
    END
  END wbs_dat_o[7]
  PIN wbs_dat_o[8]
    DIRECTION OUTPUT ;
    USE SIGNAL ;
    ANTENNADIFFAREA 2.673000 ;
    PORT
      LAYER met2 ;
        RECT 355.670 0.000 355.950 4.000 ;
    END
  END wbs_dat_o[8]
  PIN wbs_dat_o[9]
    DIRECTION OUTPUT ;
    USE SIGNAL ;
    ANTENNADIFFAREA 2.673000 ;
    PORT
      LAYER met2 ;
        RECT 369.470 0.000 369.750 4.000 ;
    END
  END wbs_dat_o[9]
  PIN wbs_sel_i[0]
    DIRECTION INPUT ;
    USE SIGNAL ;
    ANTENNAGATEAREA 0.126000 ;
    PORT
      LAYER met2 ;
        RECT 231.470 0.000 231.750 4.000 ;
    END
  END wbs_sel_i[0]
  PIN wbs_sel_i[1]
    DIRECTION INPUT ;
    USE SIGNAL ;
    ANTENNAGATEAREA 0.126000 ;
    PORT
      LAYER met2 ;
        RECT 249.870 0.000 250.150 4.000 ;
    END
  END wbs_sel_i[1]
  PIN wbs_sel_i[2]
    DIRECTION INPUT ;
    USE SIGNAL ;
    ANTENNAGATEAREA 0.126000 ;
    PORT
      LAYER met2 ;
        RECT 268.270 0.000 268.550 4.000 ;
    END
  END wbs_sel_i[2]
  PIN wbs_sel_i[3]
    DIRECTION INPUT ;
    USE SIGNAL ;
    ANTENNAGATEAREA 0.126000 ;
    PORT
      LAYER met2 ;
        RECT 286.670 0.000 286.950 4.000 ;
    END
  END wbs_sel_i[3]
  PIN wbs_stb_i
    DIRECTION INPUT ;
    USE SIGNAL ;
    ANTENNAGATEAREA 0.213000 ;
    PORT
      LAYER met2 ;
        RECT 208.470 0.000 208.750 4.000 ;
    END
  END wbs_stb_i
  PIN wbs_we_i
    DIRECTION INPUT ;
    USE SIGNAL ;
    ANTENNAGATEAREA 0.126000 ;
    PORT
      LAYER met2 ;
        RECT 213.070 0.000 213.350 4.000 ;
    END
  END wbs_we_i
  OBS
      LAYER nwell ;
        RECT 4.870 5.320 675.010 1642.965 ;
      LAYER li1 ;
        RECT 5.060 5.355 674.820 1642.965 ;
      LAYER met1 ;
        RECT 5.060 1628.170 680.000 1643.120 ;
        RECT 5.060 1621.575 421.000 1628.170 ;
      LAYER met1 ;
        RECT 421.000 1627.030 724.315 1628.170 ;
        RECT 421.000 1625.335 724.035 1627.030 ;
      LAYER met1 ;
        RECT 724.035 1625.335 724.315 1627.030 ;
      LAYER met1 ;
        RECT 421.000 1623.090 724.315 1625.335 ;
        RECT 421.000 1622.590 723.980 1623.090 ;
      LAYER met1 ;
        RECT 723.980 1622.590 724.315 1623.090 ;
      LAYER met1 ;
        RECT 421.000 1621.575 724.315 1622.590 ;
      LAYER met1 ;
        RECT 5.060 1621.345 421.500 1621.575 ;
      LAYER met1 ;
        RECT 421.500 1621.345 724.315 1621.575 ;
      LAYER met1 ;
        RECT 5.060 1619.425 421.000 1621.345 ;
      LAYER met1 ;
        RECT 421.000 1619.425 724.315 1621.345 ;
      LAYER met1 ;
        RECT 5.060 1618.055 422.000 1619.425 ;
      LAYER met1 ;
        RECT 422.000 1618.055 724.315 1619.425 ;
      LAYER met1 ;
        RECT 5.060 1616.695 421.000 1618.055 ;
      LAYER met1 ;
        RECT 421.000 1616.695 724.315 1618.055 ;
      LAYER met1 ;
        RECT 5.060 1616.465 421.430 1616.695 ;
      LAYER met1 ;
        RECT 421.430 1616.465 724.315 1616.695 ;
      LAYER met1 ;
        RECT 5.060 1615.435 421.000 1616.465 ;
      LAYER met1 ;
        RECT 421.000 1615.435 724.315 1616.465 ;
      LAYER met1 ;
        RECT 5.060 1615.205 421.500 1615.435 ;
      LAYER met1 ;
        RECT 421.500 1615.205 724.315 1615.435 ;
      LAYER met1 ;
        RECT 5.060 1610.675 421.000 1615.205 ;
      LAYER met1 ;
        RECT 421.000 1614.800 724.315 1615.205 ;
        RECT 421.000 1612.560 724.035 1614.800 ;
      LAYER met1 ;
        RECT 724.035 1612.560 724.315 1614.800 ;
      LAYER met1 ;
        RECT 421.000 1610.675 724.315 1612.560 ;
      LAYER met1 ;
        RECT 5.060 1610.445 421.500 1610.675 ;
      LAYER met1 ;
        RECT 421.500 1610.445 724.315 1610.675 ;
      LAYER met1 ;
        RECT 5.060 1608.525 421.000 1610.445 ;
      LAYER met1 ;
        RECT 421.000 1608.525 724.315 1610.445 ;
      LAYER met1 ;
        RECT 5.060 1607.155 422.000 1608.525 ;
      LAYER met1 ;
        RECT 422.000 1607.155 724.315 1608.525 ;
      LAYER met1 ;
        RECT 5.060 1605.795 421.000 1607.155 ;
      LAYER met1 ;
        RECT 421.000 1605.795 724.315 1607.155 ;
      LAYER met1 ;
        RECT 5.060 1605.565 421.430 1605.795 ;
      LAYER met1 ;
        RECT 421.430 1605.565 724.315 1605.795 ;
      LAYER met1 ;
        RECT 5.060 1604.535 421.000 1605.565 ;
      LAYER met1 ;
        RECT 421.000 1604.535 724.315 1605.565 ;
      LAYER met1 ;
        RECT 5.060 1604.305 421.500 1604.535 ;
      LAYER met1 ;
        RECT 421.500 1604.305 724.315 1604.535 ;
      LAYER met1 ;
        RECT 5.060 1599.775 421.000 1604.305 ;
      LAYER met1 ;
        RECT 421.000 1599.775 724.315 1604.305 ;
      LAYER met1 ;
        RECT 5.060 1599.545 421.500 1599.775 ;
      LAYER met1 ;
        RECT 421.500 1599.545 724.315 1599.775 ;
      LAYER met1 ;
        RECT 5.060 1597.625 421.000 1599.545 ;
      LAYER met1 ;
        RECT 421.000 1597.625 724.315 1599.545 ;
      LAYER met1 ;
        RECT 5.060 1596.255 422.000 1597.625 ;
      LAYER met1 ;
        RECT 422.000 1596.255 724.315 1597.625 ;
      LAYER met1 ;
        RECT 5.060 1594.895 421.000 1596.255 ;
      LAYER met1 ;
        RECT 421.000 1594.895 724.315 1596.255 ;
      LAYER met1 ;
        RECT 5.060 1594.665 421.430 1594.895 ;
      LAYER met1 ;
        RECT 421.430 1594.665 724.315 1594.895 ;
      LAYER met1 ;
        RECT 5.060 1593.635 421.000 1594.665 ;
      LAYER met1 ;
        RECT 421.000 1593.635 724.315 1594.665 ;
      LAYER met1 ;
        RECT 5.060 1593.405 421.500 1593.635 ;
      LAYER met1 ;
        RECT 421.500 1593.405 724.315 1593.635 ;
      LAYER met1 ;
        RECT 5.060 1588.875 421.000 1593.405 ;
      LAYER met1 ;
        RECT 421.000 1588.875 724.315 1593.405 ;
      LAYER met1 ;
        RECT 5.060 1588.645 421.500 1588.875 ;
      LAYER met1 ;
        RECT 421.500 1588.645 724.315 1588.875 ;
      LAYER met1 ;
        RECT 5.060 1586.725 421.000 1588.645 ;
      LAYER met1 ;
        RECT 421.000 1586.725 724.315 1588.645 ;
      LAYER met1 ;
        RECT 5.060 1585.355 422.000 1586.725 ;
      LAYER met1 ;
        RECT 422.000 1585.355 724.315 1586.725 ;
      LAYER met1 ;
        RECT 5.060 1583.995 421.000 1585.355 ;
      LAYER met1 ;
        RECT 421.000 1583.995 724.315 1585.355 ;
      LAYER met1 ;
        RECT 5.060 1583.765 421.430 1583.995 ;
      LAYER met1 ;
        RECT 421.430 1583.765 724.315 1583.995 ;
      LAYER met1 ;
        RECT 5.060 1582.735 421.000 1583.765 ;
      LAYER met1 ;
        RECT 421.000 1582.735 724.315 1583.765 ;
      LAYER met1 ;
        RECT 5.060 1582.505 421.500 1582.735 ;
      LAYER met1 ;
        RECT 421.500 1582.505 724.315 1582.735 ;
      LAYER met1 ;
        RECT 5.060 1577.975 421.000 1582.505 ;
      LAYER met1 ;
        RECT 421.000 1577.975 724.315 1582.505 ;
      LAYER met1 ;
        RECT 5.060 1577.745 421.500 1577.975 ;
      LAYER met1 ;
        RECT 421.500 1577.745 724.315 1577.975 ;
      LAYER met1 ;
        RECT 5.060 1575.825 421.000 1577.745 ;
      LAYER met1 ;
        RECT 421.000 1575.825 724.315 1577.745 ;
      LAYER met1 ;
        RECT 5.060 1574.455 422.000 1575.825 ;
      LAYER met1 ;
        RECT 422.000 1574.455 724.315 1575.825 ;
      LAYER met1 ;
        RECT 5.060 1573.095 421.000 1574.455 ;
      LAYER met1 ;
        RECT 421.000 1573.095 724.315 1574.455 ;
      LAYER met1 ;
        RECT 5.060 1572.865 421.430 1573.095 ;
      LAYER met1 ;
        RECT 421.430 1572.865 724.315 1573.095 ;
      LAYER met1 ;
        RECT 5.060 1571.835 421.000 1572.865 ;
      LAYER met1 ;
        RECT 421.000 1571.835 724.315 1572.865 ;
      LAYER met1 ;
        RECT 5.060 1571.605 421.500 1571.835 ;
      LAYER met1 ;
        RECT 421.500 1571.605 724.315 1571.835 ;
      LAYER met1 ;
        RECT 5.060 1567.075 421.000 1571.605 ;
      LAYER met1 ;
        RECT 421.000 1567.075 724.315 1571.605 ;
      LAYER met1 ;
        RECT 5.060 1566.845 421.500 1567.075 ;
      LAYER met1 ;
        RECT 421.500 1566.845 724.315 1567.075 ;
      LAYER met1 ;
        RECT 5.060 1564.925 421.000 1566.845 ;
      LAYER met1 ;
        RECT 421.000 1564.925 724.315 1566.845 ;
      LAYER met1 ;
        RECT 5.060 1563.555 422.000 1564.925 ;
      LAYER met1 ;
        RECT 422.000 1563.555 724.315 1564.925 ;
      LAYER met1 ;
        RECT 5.060 1562.195 421.000 1563.555 ;
      LAYER met1 ;
        RECT 421.000 1562.195 724.315 1563.555 ;
      LAYER met1 ;
        RECT 5.060 1561.965 421.430 1562.195 ;
      LAYER met1 ;
        RECT 421.430 1561.965 724.315 1562.195 ;
      LAYER met1 ;
        RECT 5.060 1560.935 421.000 1561.965 ;
      LAYER met1 ;
        RECT 421.000 1560.935 724.315 1561.965 ;
      LAYER met1 ;
        RECT 5.060 1560.705 421.500 1560.935 ;
      LAYER met1 ;
        RECT 421.500 1560.705 724.315 1560.935 ;
      LAYER met1 ;
        RECT 5.060 1556.175 421.000 1560.705 ;
      LAYER met1 ;
        RECT 421.000 1556.175 724.315 1560.705 ;
      LAYER met1 ;
        RECT 5.060 1555.945 421.500 1556.175 ;
      LAYER met1 ;
        RECT 421.500 1555.945 724.315 1556.175 ;
      LAYER met1 ;
        RECT 5.060 1554.025 421.000 1555.945 ;
      LAYER met1 ;
        RECT 421.000 1554.025 724.315 1555.945 ;
      LAYER met1 ;
        RECT 5.060 1552.655 422.000 1554.025 ;
      LAYER met1 ;
        RECT 422.000 1552.655 724.315 1554.025 ;
      LAYER met1 ;
        RECT 5.060 1551.295 421.000 1552.655 ;
      LAYER met1 ;
        RECT 421.000 1551.295 724.315 1552.655 ;
      LAYER met1 ;
        RECT 5.060 1551.065 421.430 1551.295 ;
      LAYER met1 ;
        RECT 421.430 1551.065 724.315 1551.295 ;
      LAYER met1 ;
        RECT 5.060 1550.035 421.000 1551.065 ;
      LAYER met1 ;
        RECT 421.000 1550.035 724.315 1551.065 ;
      LAYER met1 ;
        RECT 5.060 1549.805 421.500 1550.035 ;
      LAYER met1 ;
        RECT 421.500 1549.805 724.315 1550.035 ;
      LAYER met1 ;
        RECT 5.060 1545.275 421.000 1549.805 ;
      LAYER met1 ;
        RECT 421.000 1545.275 724.315 1549.805 ;
      LAYER met1 ;
        RECT 5.060 1545.045 421.500 1545.275 ;
      LAYER met1 ;
        RECT 421.500 1545.045 724.315 1545.275 ;
      LAYER met1 ;
        RECT 5.060 1543.125 421.000 1545.045 ;
      LAYER met1 ;
        RECT 421.000 1543.125 724.315 1545.045 ;
      LAYER met1 ;
        RECT 5.060 1541.755 422.000 1543.125 ;
      LAYER met1 ;
        RECT 422.000 1541.755 724.315 1543.125 ;
      LAYER met1 ;
        RECT 5.060 1540.395 421.000 1541.755 ;
      LAYER met1 ;
        RECT 421.000 1540.395 724.315 1541.755 ;
      LAYER met1 ;
        RECT 5.060 1540.165 421.430 1540.395 ;
      LAYER met1 ;
        RECT 421.430 1540.165 724.315 1540.395 ;
      LAYER met1 ;
        RECT 5.060 1539.135 421.000 1540.165 ;
      LAYER met1 ;
        RECT 421.000 1539.135 724.315 1540.165 ;
      LAYER met1 ;
        RECT 5.060 1538.905 421.500 1539.135 ;
      LAYER met1 ;
        RECT 421.500 1538.905 724.315 1539.135 ;
      LAYER met1 ;
        RECT 5.060 1534.375 421.000 1538.905 ;
      LAYER met1 ;
        RECT 421.000 1534.375 724.315 1538.905 ;
      LAYER met1 ;
        RECT 5.060 1534.145 421.500 1534.375 ;
      LAYER met1 ;
        RECT 421.500 1534.145 724.315 1534.375 ;
      LAYER met1 ;
        RECT 5.060 1532.225 421.000 1534.145 ;
      LAYER met1 ;
        RECT 421.000 1532.225 724.315 1534.145 ;
      LAYER met1 ;
        RECT 5.060 1530.855 422.000 1532.225 ;
      LAYER met1 ;
        RECT 422.000 1530.855 724.315 1532.225 ;
      LAYER met1 ;
        RECT 5.060 1529.495 421.000 1530.855 ;
      LAYER met1 ;
        RECT 421.000 1529.495 724.315 1530.855 ;
      LAYER met1 ;
        RECT 5.060 1529.265 421.430 1529.495 ;
      LAYER met1 ;
        RECT 421.430 1529.265 724.315 1529.495 ;
      LAYER met1 ;
        RECT 5.060 1528.235 421.000 1529.265 ;
      LAYER met1 ;
        RECT 421.000 1528.235 724.315 1529.265 ;
      LAYER met1 ;
        RECT 5.060 1528.005 421.500 1528.235 ;
      LAYER met1 ;
        RECT 421.500 1528.005 724.315 1528.235 ;
      LAYER met1 ;
        RECT 5.060 1523.475 421.000 1528.005 ;
      LAYER met1 ;
        RECT 421.000 1523.475 724.315 1528.005 ;
      LAYER met1 ;
        RECT 5.060 1523.245 421.500 1523.475 ;
      LAYER met1 ;
        RECT 421.500 1523.245 724.315 1523.475 ;
      LAYER met1 ;
        RECT 5.060 1521.325 421.000 1523.245 ;
      LAYER met1 ;
        RECT 421.000 1521.325 724.315 1523.245 ;
      LAYER met1 ;
        RECT 5.060 1519.955 422.000 1521.325 ;
      LAYER met1 ;
        RECT 422.000 1519.955 724.315 1521.325 ;
      LAYER met1 ;
        RECT 5.060 1518.595 421.000 1519.955 ;
      LAYER met1 ;
        RECT 421.000 1518.595 724.315 1519.955 ;
      LAYER met1 ;
        RECT 5.060 1518.365 421.430 1518.595 ;
      LAYER met1 ;
        RECT 421.430 1518.365 724.315 1518.595 ;
      LAYER met1 ;
        RECT 5.060 1517.335 421.000 1518.365 ;
      LAYER met1 ;
        RECT 421.000 1517.335 724.315 1518.365 ;
      LAYER met1 ;
        RECT 5.060 1517.105 421.500 1517.335 ;
      LAYER met1 ;
        RECT 421.500 1517.105 724.315 1517.335 ;
      LAYER met1 ;
        RECT 5.060 1512.575 421.000 1517.105 ;
      LAYER met1 ;
        RECT 421.000 1512.575 724.315 1517.105 ;
      LAYER met1 ;
        RECT 5.060 1512.345 421.500 1512.575 ;
      LAYER met1 ;
        RECT 421.500 1512.345 724.315 1512.575 ;
      LAYER met1 ;
        RECT 5.060 1510.425 421.000 1512.345 ;
      LAYER met1 ;
        RECT 421.000 1510.425 724.315 1512.345 ;
      LAYER met1 ;
        RECT 5.060 1509.055 422.000 1510.425 ;
      LAYER met1 ;
        RECT 422.000 1509.055 724.315 1510.425 ;
      LAYER met1 ;
        RECT 5.060 1507.695 421.000 1509.055 ;
      LAYER met1 ;
        RECT 421.000 1507.695 724.315 1509.055 ;
      LAYER met1 ;
        RECT 5.060 1507.465 421.430 1507.695 ;
      LAYER met1 ;
        RECT 421.430 1507.465 724.315 1507.695 ;
      LAYER met1 ;
        RECT 5.060 1506.435 421.000 1507.465 ;
      LAYER met1 ;
        RECT 421.000 1506.435 724.315 1507.465 ;
      LAYER met1 ;
        RECT 5.060 1506.205 421.500 1506.435 ;
      LAYER met1 ;
        RECT 421.500 1506.205 724.315 1506.435 ;
      LAYER met1 ;
        RECT 5.060 1501.675 421.000 1506.205 ;
      LAYER met1 ;
        RECT 421.000 1501.675 724.315 1506.205 ;
      LAYER met1 ;
        RECT 5.060 1501.445 421.500 1501.675 ;
      LAYER met1 ;
        RECT 421.500 1501.445 724.315 1501.675 ;
      LAYER met1 ;
        RECT 5.060 1499.525 421.000 1501.445 ;
      LAYER met1 ;
        RECT 421.000 1499.525 724.315 1501.445 ;
      LAYER met1 ;
        RECT 5.060 1498.155 422.000 1499.525 ;
      LAYER met1 ;
        RECT 422.000 1498.155 724.315 1499.525 ;
      LAYER met1 ;
        RECT 5.060 1496.795 421.000 1498.155 ;
      LAYER met1 ;
        RECT 421.000 1496.795 724.315 1498.155 ;
      LAYER met1 ;
        RECT 5.060 1496.565 421.430 1496.795 ;
      LAYER met1 ;
        RECT 421.430 1496.565 724.315 1496.795 ;
      LAYER met1 ;
        RECT 5.060 1495.535 421.000 1496.565 ;
      LAYER met1 ;
        RECT 421.000 1495.535 724.315 1496.565 ;
      LAYER met1 ;
        RECT 5.060 1495.305 421.500 1495.535 ;
      LAYER met1 ;
        RECT 421.500 1495.305 724.315 1495.535 ;
      LAYER met1 ;
        RECT 5.060 1490.775 421.000 1495.305 ;
      LAYER met1 ;
        RECT 421.000 1490.775 724.315 1495.305 ;
      LAYER met1 ;
        RECT 5.060 1490.545 421.500 1490.775 ;
      LAYER met1 ;
        RECT 421.500 1490.545 724.315 1490.775 ;
      LAYER met1 ;
        RECT 5.060 1488.625 421.000 1490.545 ;
      LAYER met1 ;
        RECT 421.000 1488.625 724.315 1490.545 ;
      LAYER met1 ;
        RECT 5.060 1487.255 422.000 1488.625 ;
      LAYER met1 ;
        RECT 422.000 1487.255 724.315 1488.625 ;
      LAYER met1 ;
        RECT 5.060 1485.895 421.000 1487.255 ;
      LAYER met1 ;
        RECT 421.000 1485.895 724.315 1487.255 ;
      LAYER met1 ;
        RECT 5.060 1485.665 421.430 1485.895 ;
      LAYER met1 ;
        RECT 421.430 1485.665 724.315 1485.895 ;
      LAYER met1 ;
        RECT 5.060 1484.635 421.000 1485.665 ;
      LAYER met1 ;
        RECT 421.000 1484.635 724.315 1485.665 ;
      LAYER met1 ;
        RECT 5.060 1484.405 421.500 1484.635 ;
      LAYER met1 ;
        RECT 421.500 1484.405 724.315 1484.635 ;
      LAYER met1 ;
        RECT 5.060 1479.875 421.000 1484.405 ;
      LAYER met1 ;
        RECT 421.000 1479.875 724.315 1484.405 ;
      LAYER met1 ;
        RECT 5.060 1479.645 421.500 1479.875 ;
      LAYER met1 ;
        RECT 421.500 1479.645 724.315 1479.875 ;
      LAYER met1 ;
        RECT 5.060 1477.725 421.000 1479.645 ;
      LAYER met1 ;
        RECT 421.000 1477.725 724.315 1479.645 ;
      LAYER met1 ;
        RECT 5.060 1476.355 422.000 1477.725 ;
      LAYER met1 ;
        RECT 422.000 1476.355 724.315 1477.725 ;
      LAYER met1 ;
        RECT 5.060 1474.995 421.000 1476.355 ;
      LAYER met1 ;
        RECT 421.000 1474.995 724.315 1476.355 ;
      LAYER met1 ;
        RECT 5.060 1474.765 421.430 1474.995 ;
      LAYER met1 ;
        RECT 421.430 1474.765 724.315 1474.995 ;
      LAYER met1 ;
        RECT 5.060 1473.735 421.000 1474.765 ;
      LAYER met1 ;
        RECT 421.000 1473.735 724.315 1474.765 ;
      LAYER met1 ;
        RECT 5.060 1473.505 421.500 1473.735 ;
      LAYER met1 ;
        RECT 421.500 1473.505 724.315 1473.735 ;
      LAYER met1 ;
        RECT 5.060 1468.975 421.000 1473.505 ;
      LAYER met1 ;
        RECT 421.000 1468.975 724.315 1473.505 ;
      LAYER met1 ;
        RECT 5.060 1468.745 421.500 1468.975 ;
      LAYER met1 ;
        RECT 421.500 1468.745 724.315 1468.975 ;
      LAYER met1 ;
        RECT 5.060 1466.825 421.000 1468.745 ;
      LAYER met1 ;
        RECT 421.000 1466.825 724.315 1468.745 ;
      LAYER met1 ;
        RECT 5.060 1465.455 422.000 1466.825 ;
      LAYER met1 ;
        RECT 422.000 1465.455 724.315 1466.825 ;
      LAYER met1 ;
        RECT 5.060 1464.095 421.000 1465.455 ;
      LAYER met1 ;
        RECT 421.000 1464.095 724.315 1465.455 ;
      LAYER met1 ;
        RECT 5.060 1463.865 421.430 1464.095 ;
      LAYER met1 ;
        RECT 421.430 1463.865 724.315 1464.095 ;
      LAYER met1 ;
        RECT 5.060 1462.835 421.000 1463.865 ;
      LAYER met1 ;
        RECT 421.000 1462.835 724.315 1463.865 ;
      LAYER met1 ;
        RECT 5.060 1462.605 421.500 1462.835 ;
      LAYER met1 ;
        RECT 421.500 1462.605 724.315 1462.835 ;
      LAYER met1 ;
        RECT 5.060 1458.075 421.000 1462.605 ;
      LAYER met1 ;
        RECT 421.000 1458.075 724.315 1462.605 ;
      LAYER met1 ;
        RECT 5.060 1457.845 421.500 1458.075 ;
      LAYER met1 ;
        RECT 421.500 1457.845 724.315 1458.075 ;
      LAYER met1 ;
        RECT 5.060 1456.255 421.000 1457.845 ;
      LAYER met1 ;
        RECT 421.000 1456.255 724.315 1457.845 ;
      LAYER met1 ;
        RECT 5.060 1456.065 422.015 1456.255 ;
      LAYER met1 ;
        RECT 422.015 1456.065 724.315 1456.255 ;
      LAYER met1 ;
        RECT 5.060 1455.925 421.000 1456.065 ;
      LAYER met1 ;
        RECT 421.000 1455.925 724.315 1456.065 ;
      LAYER met1 ;
        RECT 5.060 1454.555 422.000 1455.925 ;
      LAYER met1 ;
        RECT 422.000 1454.555 724.315 1455.925 ;
      LAYER met1 ;
        RECT 5.060 1453.195 421.000 1454.555 ;
      LAYER met1 ;
        RECT 421.000 1453.195 724.315 1454.555 ;
      LAYER met1 ;
        RECT 5.060 1452.965 421.430 1453.195 ;
      LAYER met1 ;
        RECT 421.430 1452.965 724.315 1453.195 ;
      LAYER met1 ;
        RECT 5.060 1451.935 421.000 1452.965 ;
      LAYER met1 ;
        RECT 421.000 1451.935 724.315 1452.965 ;
      LAYER met1 ;
        RECT 5.060 1451.705 421.500 1451.935 ;
      LAYER met1 ;
        RECT 421.500 1451.705 724.315 1451.935 ;
      LAYER met1 ;
        RECT 5.060 1450.030 421.000 1451.705 ;
      LAYER met1 ;
        RECT 421.000 1450.030 724.315 1451.705 ;
      LAYER met1 ;
        RECT 5.060 1449.770 421.630 1450.030 ;
      LAYER met1 ;
        RECT 421.630 1449.770 724.315 1450.030 ;
      LAYER met1 ;
        RECT 5.060 1449.105 421.000 1449.770 ;
      LAYER met1 ;
        RECT 421.000 1449.105 724.315 1449.770 ;
      LAYER met1 ;
        RECT 5.060 1448.845 421.620 1449.105 ;
      LAYER met1 ;
        RECT 421.620 1448.845 724.315 1449.105 ;
      LAYER met1 ;
        RECT 5.060 1445.965 421.000 1448.845 ;
      LAYER met1 ;
        RECT 421.000 1445.965 724.315 1448.845 ;
      LAYER met1 ;
        RECT 5.060 1445.705 421.605 1445.965 ;
      LAYER met1 ;
        RECT 421.605 1445.705 724.315 1445.965 ;
      LAYER met1 ;
        RECT 5.060 1445.565 421.000 1445.705 ;
      LAYER met1 ;
        RECT 421.000 1445.565 724.315 1445.705 ;
      LAYER met1 ;
        RECT 5.060 1445.305 421.610 1445.565 ;
      LAYER met1 ;
        RECT 421.610 1445.305 724.315 1445.565 ;
      LAYER met1 ;
        RECT 5.060 1442.425 421.000 1445.305 ;
      LAYER met1 ;
        RECT 421.000 1442.425 724.315 1445.305 ;
      LAYER met1 ;
        RECT 5.060 1442.165 421.550 1442.425 ;
      LAYER met1 ;
        RECT 421.550 1442.165 724.315 1442.425 ;
      LAYER met1 ;
        RECT 5.060 1442.025 421.000 1442.165 ;
      LAYER met1 ;
        RECT 421.000 1442.025 724.315 1442.165 ;
      LAYER met1 ;
        RECT 5.060 1441.765 421.535 1442.025 ;
      LAYER met1 ;
        RECT 421.535 1441.765 724.315 1442.025 ;
      LAYER met1 ;
        RECT 5.060 1438.885 421.000 1441.765 ;
      LAYER met1 ;
        RECT 421.000 1438.885 724.315 1441.765 ;
      LAYER met1 ;
        RECT 5.060 1438.625 421.590 1438.885 ;
      LAYER met1 ;
        RECT 421.590 1438.625 724.315 1438.885 ;
      LAYER met1 ;
        RECT 5.060 1438.485 421.000 1438.625 ;
      LAYER met1 ;
        RECT 421.000 1438.485 724.315 1438.625 ;
      LAYER met1 ;
        RECT 5.060 1438.225 421.575 1438.485 ;
      LAYER met1 ;
        RECT 421.575 1438.225 724.315 1438.485 ;
      LAYER met1 ;
        RECT 5.060 1431.805 421.000 1438.225 ;
      LAYER met1 ;
        RECT 421.000 1434.365 724.315 1438.225 ;
        RECT 421.000 1434.105 724.055 1434.365 ;
      LAYER met1 ;
        RECT 724.055 1434.105 724.775 1434.365 ;
      LAYER met1 ;
        RECT 421.000 1431.805 724.315 1434.105 ;
      LAYER met1 ;
        RECT 5.060 1431.545 421.510 1431.805 ;
      LAYER met1 ;
        RECT 421.510 1431.545 724.315 1431.805 ;
      LAYER met1 ;
        RECT 5.060 1431.405 421.000 1431.545 ;
      LAYER met1 ;
        RECT 421.000 1431.405 724.315 1431.545 ;
      LAYER met1 ;
        RECT 5.060 1431.145 421.510 1431.405 ;
      LAYER met1 ;
        RECT 421.510 1431.145 724.315 1431.405 ;
      LAYER met1 ;
        RECT 5.060 1428.265 421.000 1431.145 ;
      LAYER met1 ;
        RECT 421.000 1428.265 724.315 1431.145 ;
      LAYER met1 ;
        RECT 5.060 1428.005 421.510 1428.265 ;
      LAYER met1 ;
        RECT 421.510 1428.005 724.315 1428.265 ;
      LAYER met1 ;
        RECT 5.060 1427.865 421.000 1428.005 ;
      LAYER met1 ;
        RECT 421.000 1427.865 724.315 1428.005 ;
      LAYER met1 ;
        RECT 5.060 1427.605 421.505 1427.865 ;
      LAYER met1 ;
        RECT 421.505 1427.605 724.315 1427.865 ;
      LAYER met1 ;
        RECT 5.060 1424.720 421.000 1427.605 ;
      LAYER met1 ;
        RECT 421.000 1424.720 724.315 1427.605 ;
      LAYER met1 ;
        RECT 5.060 1424.465 421.675 1424.720 ;
      LAYER met1 ;
        RECT 421.675 1424.465 724.315 1424.720 ;
      LAYER met1 ;
        RECT 5.060 1424.325 421.000 1424.465 ;
      LAYER met1 ;
        RECT 421.000 1424.325 724.315 1424.465 ;
      LAYER met1 ;
        RECT 5.060 1424.065 421.665 1424.325 ;
      LAYER met1 ;
        RECT 421.665 1424.065 724.315 1424.325 ;
      LAYER met1 ;
        RECT 5.060 1419.985 421.000 1424.065 ;
      LAYER met1 ;
        RECT 421.000 1419.985 724.315 1424.065 ;
      LAYER met1 ;
        RECT 5.060 1419.785 421.865 1419.985 ;
      LAYER met1 ;
        RECT 421.865 1419.785 724.315 1419.985 ;
      LAYER met1 ;
        RECT 5.060 1419.645 421.000 1419.785 ;
      LAYER met1 ;
        RECT 421.000 1419.645 724.315 1419.785 ;
      LAYER met1 ;
        RECT 5.060 1419.445 421.880 1419.645 ;
      LAYER met1 ;
        RECT 421.880 1419.445 724.315 1419.645 ;
      LAYER met1 ;
        RECT 5.060 1418.285 421.000 1419.445 ;
      LAYER met1 ;
        RECT 421.000 1418.285 724.315 1419.445 ;
      LAYER met1 ;
        RECT 5.060 1418.095 421.785 1418.285 ;
      LAYER met1 ;
        RECT 421.785 1418.095 724.315 1418.285 ;
      LAYER met1 ;
        RECT 5.060 1416.765 421.000 1418.095 ;
      LAYER met1 ;
        RECT 421.000 1416.765 724.315 1418.095 ;
      LAYER met1 ;
        RECT 5.060 1416.535 421.500 1416.765 ;
      LAYER met1 ;
        RECT 421.500 1416.535 724.315 1416.765 ;
      LAYER met1 ;
        RECT 5.060 1415.505 421.000 1416.535 ;
      LAYER met1 ;
        RECT 421.000 1415.505 724.315 1416.535 ;
      LAYER met1 ;
        RECT 5.060 1415.275 421.430 1415.505 ;
      LAYER met1 ;
        RECT 421.430 1415.275 724.315 1415.505 ;
      LAYER met1 ;
        RECT 5.060 1413.915 421.000 1415.275 ;
      LAYER met1 ;
        RECT 421.000 1413.915 724.315 1415.275 ;
      LAYER met1 ;
        RECT 5.060 1412.545 422.000 1413.915 ;
      LAYER met1 ;
        RECT 422.000 1412.545 724.315 1413.915 ;
      LAYER met1 ;
        RECT 5.060 1410.625 421.000 1412.545 ;
      LAYER met1 ;
        RECT 421.000 1410.625 724.315 1412.545 ;
      LAYER met1 ;
        RECT 5.060 1410.395 421.500 1410.625 ;
      LAYER met1 ;
        RECT 421.500 1410.395 724.315 1410.625 ;
      LAYER met1 ;
        RECT 5.060 1407.825 421.000 1410.395 ;
      LAYER met1 ;
        RECT 421.000 1407.825 724.315 1410.395 ;
      LAYER met1 ;
        RECT 5.060 1407.575 421.630 1407.825 ;
      LAYER met1 ;
        RECT 421.630 1407.575 724.315 1407.825 ;
      LAYER met1 ;
        RECT 5.060 1407.435 421.000 1407.575 ;
      LAYER met1 ;
        RECT 421.000 1407.435 724.315 1407.575 ;
      LAYER met1 ;
        RECT 5.060 1407.195 421.635 1407.435 ;
      LAYER met1 ;
        RECT 421.635 1407.195 724.315 1407.435 ;
      LAYER met1 ;
        RECT 5.060 1405.865 421.000 1407.195 ;
      LAYER met1 ;
        RECT 421.000 1405.865 724.315 1407.195 ;
      LAYER met1 ;
        RECT 5.060 1405.635 421.500 1405.865 ;
      LAYER met1 ;
        RECT 421.500 1405.635 724.315 1405.865 ;
      LAYER met1 ;
        RECT 5.060 1404.605 421.000 1405.635 ;
      LAYER met1 ;
        RECT 421.000 1404.605 724.315 1405.635 ;
      LAYER met1 ;
        RECT 5.060 1404.375 421.430 1404.605 ;
      LAYER met1 ;
        RECT 421.430 1404.375 724.315 1404.605 ;
      LAYER met1 ;
        RECT 5.060 1403.015 421.000 1404.375 ;
      LAYER met1 ;
        RECT 421.000 1403.015 724.315 1404.375 ;
      LAYER met1 ;
        RECT 5.060 1401.645 422.000 1403.015 ;
      LAYER met1 ;
        RECT 422.000 1401.645 724.315 1403.015 ;
      LAYER met1 ;
        RECT 5.060 1401.125 421.000 1401.645 ;
      LAYER met1 ;
        RECT 421.000 1401.125 724.315 1401.645 ;
      LAYER met1 ;
        RECT 5.060 1400.895 421.645 1401.125 ;
      LAYER met1 ;
        RECT 421.645 1400.895 724.315 1401.125 ;
      LAYER met1 ;
        RECT 5.060 1399.725 421.000 1400.895 ;
      LAYER met1 ;
        RECT 421.000 1399.725 724.315 1400.895 ;
      LAYER met1 ;
        RECT 5.060 1399.495 421.500 1399.725 ;
      LAYER met1 ;
        RECT 421.500 1399.495 724.315 1399.725 ;
      LAYER met1 ;
        RECT 5.060 1394.965 421.000 1399.495 ;
      LAYER met1 ;
        RECT 421.000 1394.965 724.315 1399.495 ;
      LAYER met1 ;
        RECT 5.060 1394.735 421.500 1394.965 ;
      LAYER met1 ;
        RECT 421.500 1394.735 724.315 1394.965 ;
      LAYER met1 ;
        RECT 5.060 1393.705 421.000 1394.735 ;
      LAYER met1 ;
        RECT 421.000 1393.705 724.315 1394.735 ;
      LAYER met1 ;
        RECT 5.060 1393.475 421.430 1393.705 ;
      LAYER met1 ;
        RECT 421.430 1393.475 724.315 1393.705 ;
      LAYER met1 ;
        RECT 5.060 1392.115 421.000 1393.475 ;
      LAYER met1 ;
        RECT 421.000 1392.115 724.315 1393.475 ;
      LAYER met1 ;
        RECT 5.060 1390.745 422.000 1392.115 ;
      LAYER met1 ;
        RECT 422.000 1390.745 724.315 1392.115 ;
      LAYER met1 ;
        RECT 5.060 1388.825 421.000 1390.745 ;
      LAYER met1 ;
        RECT 421.000 1388.825 724.315 1390.745 ;
      LAYER met1 ;
        RECT 5.060 1388.595 421.500 1388.825 ;
      LAYER met1 ;
        RECT 421.500 1388.595 724.315 1388.825 ;
      LAYER met1 ;
        RECT 5.060 1384.065 421.000 1388.595 ;
      LAYER met1 ;
        RECT 421.000 1384.065 724.315 1388.595 ;
      LAYER met1 ;
        RECT 5.060 1383.835 421.500 1384.065 ;
      LAYER met1 ;
        RECT 421.500 1383.835 724.315 1384.065 ;
      LAYER met1 ;
        RECT 5.060 1382.805 421.000 1383.835 ;
      LAYER met1 ;
        RECT 421.000 1382.805 724.315 1383.835 ;
      LAYER met1 ;
        RECT 5.060 1382.575 421.430 1382.805 ;
      LAYER met1 ;
        RECT 421.430 1382.575 724.315 1382.805 ;
      LAYER met1 ;
        RECT 5.060 1381.215 421.000 1382.575 ;
      LAYER met1 ;
        RECT 421.000 1381.215 724.315 1382.575 ;
      LAYER met1 ;
        RECT 5.060 1379.845 422.000 1381.215 ;
      LAYER met1 ;
        RECT 422.000 1379.845 724.315 1381.215 ;
      LAYER met1 ;
        RECT 5.060 1377.925 421.000 1379.845 ;
      LAYER met1 ;
        RECT 421.000 1377.925 724.315 1379.845 ;
      LAYER met1 ;
        RECT 5.060 1377.695 421.500 1377.925 ;
      LAYER met1 ;
        RECT 421.500 1377.695 724.315 1377.925 ;
      LAYER met1 ;
        RECT 5.060 1373.165 421.000 1377.695 ;
      LAYER met1 ;
        RECT 421.000 1373.165 724.315 1377.695 ;
      LAYER met1 ;
        RECT 5.060 1372.935 421.500 1373.165 ;
      LAYER met1 ;
        RECT 421.500 1372.935 724.315 1373.165 ;
      LAYER met1 ;
        RECT 5.060 1371.905 421.000 1372.935 ;
      LAYER met1 ;
        RECT 421.000 1371.905 724.315 1372.935 ;
      LAYER met1 ;
        RECT 5.060 1371.675 421.430 1371.905 ;
      LAYER met1 ;
        RECT 421.430 1371.675 724.315 1371.905 ;
      LAYER met1 ;
        RECT 5.060 1370.315 421.000 1371.675 ;
      LAYER met1 ;
        RECT 421.000 1370.315 724.315 1371.675 ;
      LAYER met1 ;
        RECT 5.060 1368.945 422.000 1370.315 ;
      LAYER met1 ;
        RECT 422.000 1368.945 724.315 1370.315 ;
      LAYER met1 ;
        RECT 5.060 1367.025 421.000 1368.945 ;
      LAYER met1 ;
        RECT 421.000 1367.025 724.315 1368.945 ;
      LAYER met1 ;
        RECT 5.060 1366.795 421.500 1367.025 ;
      LAYER met1 ;
        RECT 421.500 1366.795 724.315 1367.025 ;
      LAYER met1 ;
        RECT 5.060 1362.265 421.000 1366.795 ;
      LAYER met1 ;
        RECT 421.000 1362.265 724.315 1366.795 ;
      LAYER met1 ;
        RECT 5.060 1362.035 421.500 1362.265 ;
      LAYER met1 ;
        RECT 421.500 1362.035 724.315 1362.265 ;
      LAYER met1 ;
        RECT 5.060 1361.005 421.000 1362.035 ;
      LAYER met1 ;
        RECT 421.000 1361.005 724.315 1362.035 ;
      LAYER met1 ;
        RECT 5.060 1360.775 421.430 1361.005 ;
      LAYER met1 ;
        RECT 421.430 1360.775 724.315 1361.005 ;
      LAYER met1 ;
        RECT 5.060 1359.415 421.000 1360.775 ;
      LAYER met1 ;
        RECT 421.000 1359.415 724.315 1360.775 ;
      LAYER met1 ;
        RECT 5.060 1358.045 422.000 1359.415 ;
      LAYER met1 ;
        RECT 422.000 1358.045 724.315 1359.415 ;
      LAYER met1 ;
        RECT 5.060 1356.125 421.000 1358.045 ;
      LAYER met1 ;
        RECT 421.000 1356.125 724.315 1358.045 ;
      LAYER met1 ;
        RECT 5.060 1355.895 421.500 1356.125 ;
      LAYER met1 ;
        RECT 421.500 1355.895 724.315 1356.125 ;
      LAYER met1 ;
        RECT 5.060 1351.365 421.000 1355.895 ;
      LAYER met1 ;
        RECT 421.000 1351.365 724.315 1355.895 ;
      LAYER met1 ;
        RECT 5.060 1351.135 421.500 1351.365 ;
      LAYER met1 ;
        RECT 421.500 1351.135 724.315 1351.365 ;
      LAYER met1 ;
        RECT 5.060 1350.105 421.000 1351.135 ;
      LAYER met1 ;
        RECT 421.000 1350.105 724.315 1351.135 ;
      LAYER met1 ;
        RECT 5.060 1349.875 421.430 1350.105 ;
      LAYER met1 ;
        RECT 421.430 1349.875 724.315 1350.105 ;
      LAYER met1 ;
        RECT 5.060 1348.515 421.000 1349.875 ;
      LAYER met1 ;
        RECT 421.000 1348.515 724.315 1349.875 ;
      LAYER met1 ;
        RECT 5.060 1347.145 422.000 1348.515 ;
      LAYER met1 ;
        RECT 422.000 1347.145 724.315 1348.515 ;
      LAYER met1 ;
        RECT 5.060 1345.225 421.000 1347.145 ;
      LAYER met1 ;
        RECT 421.000 1345.225 724.315 1347.145 ;
      LAYER met1 ;
        RECT 5.060 1344.995 421.500 1345.225 ;
      LAYER met1 ;
        RECT 421.500 1344.995 724.315 1345.225 ;
      LAYER met1 ;
        RECT 5.060 1340.465 421.000 1344.995 ;
      LAYER met1 ;
        RECT 421.000 1340.465 724.315 1344.995 ;
      LAYER met1 ;
        RECT 5.060 1340.235 421.500 1340.465 ;
      LAYER met1 ;
        RECT 421.500 1340.235 724.315 1340.465 ;
      LAYER met1 ;
        RECT 5.060 1339.205 421.000 1340.235 ;
      LAYER met1 ;
        RECT 421.000 1339.205 724.315 1340.235 ;
      LAYER met1 ;
        RECT 5.060 1338.975 421.430 1339.205 ;
      LAYER met1 ;
        RECT 421.430 1338.975 724.315 1339.205 ;
      LAYER met1 ;
        RECT 5.060 1337.615 421.000 1338.975 ;
      LAYER met1 ;
        RECT 421.000 1337.615 724.315 1338.975 ;
      LAYER met1 ;
        RECT 5.060 1336.245 422.000 1337.615 ;
      LAYER met1 ;
        RECT 422.000 1336.245 724.315 1337.615 ;
      LAYER met1 ;
        RECT 5.060 1334.325 421.000 1336.245 ;
      LAYER met1 ;
        RECT 421.000 1334.325 724.315 1336.245 ;
      LAYER met1 ;
        RECT 5.060 1334.095 421.500 1334.325 ;
      LAYER met1 ;
        RECT 421.500 1334.095 724.315 1334.325 ;
      LAYER met1 ;
        RECT 5.060 1329.565 421.000 1334.095 ;
      LAYER met1 ;
        RECT 421.000 1329.565 724.315 1334.095 ;
      LAYER met1 ;
        RECT 5.060 1329.335 421.500 1329.565 ;
      LAYER met1 ;
        RECT 421.500 1329.335 724.315 1329.565 ;
      LAYER met1 ;
        RECT 5.060 1328.305 421.000 1329.335 ;
      LAYER met1 ;
        RECT 421.000 1328.305 724.315 1329.335 ;
      LAYER met1 ;
        RECT 5.060 1328.075 421.430 1328.305 ;
      LAYER met1 ;
        RECT 421.430 1328.075 724.315 1328.305 ;
      LAYER met1 ;
        RECT 5.060 1326.715 421.000 1328.075 ;
      LAYER met1 ;
        RECT 421.000 1326.715 724.315 1328.075 ;
      LAYER met1 ;
        RECT 5.060 1325.345 422.000 1326.715 ;
      LAYER met1 ;
        RECT 422.000 1325.345 724.315 1326.715 ;
      LAYER met1 ;
        RECT 5.060 1323.425 421.000 1325.345 ;
      LAYER met1 ;
        RECT 421.000 1323.425 724.315 1325.345 ;
      LAYER met1 ;
        RECT 5.060 1323.195 421.500 1323.425 ;
      LAYER met1 ;
        RECT 421.500 1323.195 724.315 1323.425 ;
      LAYER met1 ;
        RECT 5.060 1318.665 421.000 1323.195 ;
      LAYER met1 ;
        RECT 421.000 1318.665 724.315 1323.195 ;
      LAYER met1 ;
        RECT 5.060 1318.435 421.500 1318.665 ;
      LAYER met1 ;
        RECT 421.500 1318.435 724.315 1318.665 ;
      LAYER met1 ;
        RECT 5.060 1317.405 421.000 1318.435 ;
      LAYER met1 ;
        RECT 421.000 1317.405 724.315 1318.435 ;
      LAYER met1 ;
        RECT 5.060 1317.175 421.430 1317.405 ;
      LAYER met1 ;
        RECT 421.430 1317.175 724.315 1317.405 ;
      LAYER met1 ;
        RECT 5.060 1315.815 421.000 1317.175 ;
      LAYER met1 ;
        RECT 421.000 1315.815 724.315 1317.175 ;
      LAYER met1 ;
        RECT 5.060 1314.445 422.000 1315.815 ;
      LAYER met1 ;
        RECT 422.000 1314.445 724.315 1315.815 ;
      LAYER met1 ;
        RECT 5.060 1312.525 421.000 1314.445 ;
      LAYER met1 ;
        RECT 421.000 1312.525 724.315 1314.445 ;
      LAYER met1 ;
        RECT 5.060 1312.295 421.500 1312.525 ;
      LAYER met1 ;
        RECT 421.500 1312.295 724.315 1312.525 ;
      LAYER met1 ;
        RECT 5.060 1307.765 421.000 1312.295 ;
      LAYER met1 ;
        RECT 421.000 1307.765 724.315 1312.295 ;
      LAYER met1 ;
        RECT 5.060 1307.535 421.500 1307.765 ;
      LAYER met1 ;
        RECT 421.500 1307.535 724.315 1307.765 ;
      LAYER met1 ;
        RECT 5.060 1306.505 421.000 1307.535 ;
      LAYER met1 ;
        RECT 421.000 1306.505 724.315 1307.535 ;
      LAYER met1 ;
        RECT 5.060 1306.275 421.430 1306.505 ;
      LAYER met1 ;
        RECT 421.430 1306.275 724.315 1306.505 ;
      LAYER met1 ;
        RECT 5.060 1304.915 421.000 1306.275 ;
      LAYER met1 ;
        RECT 421.000 1304.915 724.315 1306.275 ;
      LAYER met1 ;
        RECT 5.060 1303.545 422.000 1304.915 ;
      LAYER met1 ;
        RECT 422.000 1303.545 724.315 1304.915 ;
      LAYER met1 ;
        RECT 5.060 1301.625 421.000 1303.545 ;
      LAYER met1 ;
        RECT 421.000 1301.625 724.315 1303.545 ;
      LAYER met1 ;
        RECT 5.060 1301.395 421.500 1301.625 ;
      LAYER met1 ;
        RECT 421.500 1301.395 724.315 1301.625 ;
      LAYER met1 ;
        RECT 5.060 1296.865 421.000 1301.395 ;
      LAYER met1 ;
        RECT 421.000 1296.865 724.315 1301.395 ;
      LAYER met1 ;
        RECT 5.060 1296.635 421.500 1296.865 ;
      LAYER met1 ;
        RECT 421.500 1296.635 724.315 1296.865 ;
      LAYER met1 ;
        RECT 5.060 1295.605 421.000 1296.635 ;
      LAYER met1 ;
        RECT 421.000 1295.605 724.315 1296.635 ;
      LAYER met1 ;
        RECT 5.060 1295.375 421.430 1295.605 ;
      LAYER met1 ;
        RECT 421.430 1295.375 724.315 1295.605 ;
      LAYER met1 ;
        RECT 5.060 1294.015 421.000 1295.375 ;
      LAYER met1 ;
        RECT 421.000 1294.015 724.315 1295.375 ;
      LAYER met1 ;
        RECT 5.060 1292.645 422.000 1294.015 ;
      LAYER met1 ;
        RECT 422.000 1292.645 724.315 1294.015 ;
      LAYER met1 ;
        RECT 5.060 1290.725 421.000 1292.645 ;
      LAYER met1 ;
        RECT 421.000 1290.725 724.315 1292.645 ;
      LAYER met1 ;
        RECT 5.060 1290.495 421.500 1290.725 ;
      LAYER met1 ;
        RECT 421.500 1290.495 724.315 1290.725 ;
      LAYER met1 ;
        RECT 5.060 1285.965 421.000 1290.495 ;
      LAYER met1 ;
        RECT 421.000 1285.965 724.315 1290.495 ;
      LAYER met1 ;
        RECT 5.060 1285.735 421.500 1285.965 ;
      LAYER met1 ;
        RECT 421.500 1285.735 724.315 1285.965 ;
      LAYER met1 ;
        RECT 5.060 1284.705 421.000 1285.735 ;
      LAYER met1 ;
        RECT 421.000 1284.705 724.315 1285.735 ;
      LAYER met1 ;
        RECT 5.060 1284.475 421.430 1284.705 ;
      LAYER met1 ;
        RECT 421.430 1284.475 724.315 1284.705 ;
      LAYER met1 ;
        RECT 5.060 1283.115 421.000 1284.475 ;
      LAYER met1 ;
        RECT 421.000 1283.115 724.315 1284.475 ;
      LAYER met1 ;
        RECT 5.060 1281.745 422.000 1283.115 ;
      LAYER met1 ;
        RECT 422.000 1281.745 724.315 1283.115 ;
      LAYER met1 ;
        RECT 5.060 1279.825 421.000 1281.745 ;
      LAYER met1 ;
        RECT 421.000 1279.825 724.315 1281.745 ;
      LAYER met1 ;
        RECT 5.060 1279.595 421.500 1279.825 ;
      LAYER met1 ;
        RECT 421.500 1279.595 724.315 1279.825 ;
      LAYER met1 ;
        RECT 5.060 1275.065 421.000 1279.595 ;
      LAYER met1 ;
        RECT 421.000 1275.065 724.315 1279.595 ;
      LAYER met1 ;
        RECT 5.060 1274.835 421.500 1275.065 ;
      LAYER met1 ;
        RECT 421.500 1274.835 724.315 1275.065 ;
      LAYER met1 ;
        RECT 5.060 1273.805 421.000 1274.835 ;
      LAYER met1 ;
        RECT 421.000 1273.805 724.315 1274.835 ;
      LAYER met1 ;
        RECT 5.060 1273.575 421.430 1273.805 ;
      LAYER met1 ;
        RECT 421.430 1273.575 724.315 1273.805 ;
      LAYER met1 ;
        RECT 5.060 1272.215 421.000 1273.575 ;
      LAYER met1 ;
        RECT 421.000 1272.215 724.315 1273.575 ;
      LAYER met1 ;
        RECT 5.060 1270.845 422.000 1272.215 ;
      LAYER met1 ;
        RECT 422.000 1270.845 724.315 1272.215 ;
      LAYER met1 ;
        RECT 5.060 1268.925 421.000 1270.845 ;
      LAYER met1 ;
        RECT 421.000 1268.925 724.315 1270.845 ;
      LAYER met1 ;
        RECT 5.060 1268.695 421.500 1268.925 ;
      LAYER met1 ;
        RECT 421.500 1268.695 724.315 1268.925 ;
      LAYER met1 ;
        RECT 5.060 1264.165 421.000 1268.695 ;
      LAYER met1 ;
        RECT 421.000 1264.165 724.315 1268.695 ;
      LAYER met1 ;
        RECT 5.060 1263.935 421.500 1264.165 ;
      LAYER met1 ;
        RECT 421.500 1263.935 724.315 1264.165 ;
      LAYER met1 ;
        RECT 5.060 1262.905 421.000 1263.935 ;
      LAYER met1 ;
        RECT 421.000 1262.905 724.315 1263.935 ;
      LAYER met1 ;
        RECT 5.060 1262.675 421.430 1262.905 ;
      LAYER met1 ;
        RECT 421.430 1262.675 724.315 1262.905 ;
      LAYER met1 ;
        RECT 5.060 1261.315 421.000 1262.675 ;
      LAYER met1 ;
        RECT 421.000 1261.315 724.315 1262.675 ;
      LAYER met1 ;
        RECT 5.060 1259.945 422.000 1261.315 ;
      LAYER met1 ;
        RECT 422.000 1259.945 724.315 1261.315 ;
      LAYER met1 ;
        RECT 5.060 1258.025 421.000 1259.945 ;
      LAYER met1 ;
        RECT 421.000 1258.025 724.315 1259.945 ;
      LAYER met1 ;
        RECT 5.060 1257.795 421.500 1258.025 ;
      LAYER met1 ;
        RECT 421.500 1257.795 724.315 1258.025 ;
      LAYER met1 ;
        RECT 5.060 1253.265 421.000 1257.795 ;
      LAYER met1 ;
        RECT 421.000 1255.910 724.315 1257.795 ;
        RECT 421.000 1253.670 724.035 1255.910 ;
      LAYER met1 ;
        RECT 724.035 1253.670 724.315 1255.910 ;
      LAYER met1 ;
        RECT 421.000 1253.265 724.315 1253.670 ;
      LAYER met1 ;
        RECT 5.060 1253.035 421.500 1253.265 ;
      LAYER met1 ;
        RECT 421.500 1253.035 724.315 1253.265 ;
      LAYER met1 ;
        RECT 5.060 1252.005 421.000 1253.035 ;
      LAYER met1 ;
        RECT 421.000 1252.005 724.315 1253.035 ;
      LAYER met1 ;
        RECT 5.060 1251.775 421.430 1252.005 ;
      LAYER met1 ;
        RECT 421.430 1251.775 724.315 1252.005 ;
      LAYER met1 ;
        RECT 5.060 1250.415 421.000 1251.775 ;
      LAYER met1 ;
        RECT 421.000 1250.415 724.315 1251.775 ;
      LAYER met1 ;
        RECT 5.060 1249.045 422.000 1250.415 ;
      LAYER met1 ;
        RECT 422.000 1249.045 724.315 1250.415 ;
      LAYER met1 ;
        RECT 5.060 1247.125 421.000 1249.045 ;
      LAYER met1 ;
        RECT 421.000 1247.125 724.315 1249.045 ;
      LAYER met1 ;
        RECT 5.060 1246.895 421.500 1247.125 ;
      LAYER met1 ;
        RECT 421.500 1246.895 724.315 1247.125 ;
      LAYER met1 ;
        RECT 5.060 1240.300 421.000 1246.895 ;
      LAYER met1 ;
        RECT 421.000 1245.880 724.315 1246.895 ;
        RECT 421.000 1245.380 723.980 1245.880 ;
      LAYER met1 ;
        RECT 723.980 1245.380 724.315 1245.880 ;
      LAYER met1 ;
        RECT 421.000 1243.135 724.315 1245.380 ;
        RECT 421.000 1241.440 724.035 1243.135 ;
      LAYER met1 ;
        RECT 724.035 1241.440 724.315 1243.135 ;
      LAYER met1 ;
        RECT 421.000 1240.300 724.315 1241.440 ;
      LAYER met1 ;
        RECT 5.060 1228.370 680.000 1240.300 ;
        RECT 5.060 1221.775 421.000 1228.370 ;
      LAYER met1 ;
        RECT 421.000 1227.230 724.315 1228.370 ;
        RECT 421.000 1225.535 724.035 1227.230 ;
      LAYER met1 ;
        RECT 724.035 1225.535 724.315 1227.230 ;
      LAYER met1 ;
        RECT 421.000 1223.290 724.315 1225.535 ;
        RECT 421.000 1222.790 723.980 1223.290 ;
      LAYER met1 ;
        RECT 723.980 1222.790 724.315 1223.290 ;
      LAYER met1 ;
        RECT 421.000 1221.775 724.315 1222.790 ;
      LAYER met1 ;
        RECT 5.060 1221.545 421.500 1221.775 ;
      LAYER met1 ;
        RECT 421.500 1221.545 724.315 1221.775 ;
      LAYER met1 ;
        RECT 5.060 1219.625 421.000 1221.545 ;
      LAYER met1 ;
        RECT 421.000 1219.625 724.315 1221.545 ;
      LAYER met1 ;
        RECT 5.060 1218.255 422.000 1219.625 ;
      LAYER met1 ;
        RECT 422.000 1218.255 724.315 1219.625 ;
      LAYER met1 ;
        RECT 5.060 1216.895 421.000 1218.255 ;
      LAYER met1 ;
        RECT 421.000 1216.895 724.315 1218.255 ;
      LAYER met1 ;
        RECT 5.060 1216.665 421.430 1216.895 ;
      LAYER met1 ;
        RECT 421.430 1216.665 724.315 1216.895 ;
      LAYER met1 ;
        RECT 5.060 1215.635 421.000 1216.665 ;
      LAYER met1 ;
        RECT 421.000 1215.635 724.315 1216.665 ;
      LAYER met1 ;
        RECT 5.060 1215.405 421.500 1215.635 ;
      LAYER met1 ;
        RECT 421.500 1215.405 724.315 1215.635 ;
      LAYER met1 ;
        RECT 5.060 1210.875 421.000 1215.405 ;
      LAYER met1 ;
        RECT 421.000 1215.000 724.315 1215.405 ;
        RECT 421.000 1212.760 724.035 1215.000 ;
      LAYER met1 ;
        RECT 724.035 1212.760 724.315 1215.000 ;
      LAYER met1 ;
        RECT 421.000 1210.875 724.315 1212.760 ;
      LAYER met1 ;
        RECT 5.060 1210.645 421.500 1210.875 ;
      LAYER met1 ;
        RECT 421.500 1210.645 724.315 1210.875 ;
      LAYER met1 ;
        RECT 5.060 1208.725 421.000 1210.645 ;
      LAYER met1 ;
        RECT 421.000 1208.725 724.315 1210.645 ;
      LAYER met1 ;
        RECT 5.060 1207.355 422.000 1208.725 ;
      LAYER met1 ;
        RECT 422.000 1207.355 724.315 1208.725 ;
      LAYER met1 ;
        RECT 5.060 1205.995 421.000 1207.355 ;
      LAYER met1 ;
        RECT 421.000 1205.995 724.315 1207.355 ;
      LAYER met1 ;
        RECT 5.060 1205.765 421.430 1205.995 ;
      LAYER met1 ;
        RECT 421.430 1205.765 724.315 1205.995 ;
      LAYER met1 ;
        RECT 5.060 1204.735 421.000 1205.765 ;
      LAYER met1 ;
        RECT 421.000 1204.735 724.315 1205.765 ;
      LAYER met1 ;
        RECT 5.060 1204.505 421.500 1204.735 ;
      LAYER met1 ;
        RECT 421.500 1204.505 724.315 1204.735 ;
      LAYER met1 ;
        RECT 5.060 1199.975 421.000 1204.505 ;
      LAYER met1 ;
        RECT 421.000 1199.975 724.315 1204.505 ;
      LAYER met1 ;
        RECT 5.060 1199.745 421.500 1199.975 ;
      LAYER met1 ;
        RECT 421.500 1199.745 724.315 1199.975 ;
      LAYER met1 ;
        RECT 5.060 1197.825 421.000 1199.745 ;
      LAYER met1 ;
        RECT 421.000 1197.825 724.315 1199.745 ;
      LAYER met1 ;
        RECT 5.060 1196.455 422.000 1197.825 ;
      LAYER met1 ;
        RECT 422.000 1196.455 724.315 1197.825 ;
      LAYER met1 ;
        RECT 5.060 1195.095 421.000 1196.455 ;
      LAYER met1 ;
        RECT 421.000 1195.095 724.315 1196.455 ;
      LAYER met1 ;
        RECT 5.060 1194.865 421.430 1195.095 ;
      LAYER met1 ;
        RECT 421.430 1194.865 724.315 1195.095 ;
      LAYER met1 ;
        RECT 5.060 1193.835 421.000 1194.865 ;
      LAYER met1 ;
        RECT 421.000 1193.835 724.315 1194.865 ;
      LAYER met1 ;
        RECT 5.060 1193.605 421.500 1193.835 ;
      LAYER met1 ;
        RECT 421.500 1193.605 724.315 1193.835 ;
      LAYER met1 ;
        RECT 5.060 1189.075 421.000 1193.605 ;
      LAYER met1 ;
        RECT 421.000 1189.075 724.315 1193.605 ;
      LAYER met1 ;
        RECT 5.060 1188.845 421.500 1189.075 ;
      LAYER met1 ;
        RECT 421.500 1188.845 724.315 1189.075 ;
      LAYER met1 ;
        RECT 5.060 1186.925 421.000 1188.845 ;
      LAYER met1 ;
        RECT 421.000 1186.925 724.315 1188.845 ;
      LAYER met1 ;
        RECT 5.060 1185.555 422.000 1186.925 ;
      LAYER met1 ;
        RECT 422.000 1185.555 724.315 1186.925 ;
      LAYER met1 ;
        RECT 5.060 1184.195 421.000 1185.555 ;
      LAYER met1 ;
        RECT 421.000 1184.195 724.315 1185.555 ;
      LAYER met1 ;
        RECT 5.060 1183.965 421.430 1184.195 ;
      LAYER met1 ;
        RECT 421.430 1183.965 724.315 1184.195 ;
      LAYER met1 ;
        RECT 5.060 1182.935 421.000 1183.965 ;
      LAYER met1 ;
        RECT 421.000 1182.935 724.315 1183.965 ;
      LAYER met1 ;
        RECT 5.060 1182.705 421.500 1182.935 ;
      LAYER met1 ;
        RECT 421.500 1182.705 724.315 1182.935 ;
      LAYER met1 ;
        RECT 5.060 1178.175 421.000 1182.705 ;
      LAYER met1 ;
        RECT 421.000 1178.175 724.315 1182.705 ;
      LAYER met1 ;
        RECT 5.060 1177.945 421.500 1178.175 ;
      LAYER met1 ;
        RECT 421.500 1177.945 724.315 1178.175 ;
      LAYER met1 ;
        RECT 5.060 1176.025 421.000 1177.945 ;
      LAYER met1 ;
        RECT 421.000 1176.025 724.315 1177.945 ;
      LAYER met1 ;
        RECT 5.060 1174.655 422.000 1176.025 ;
      LAYER met1 ;
        RECT 422.000 1174.655 724.315 1176.025 ;
      LAYER met1 ;
        RECT 5.060 1173.295 421.000 1174.655 ;
      LAYER met1 ;
        RECT 421.000 1173.295 724.315 1174.655 ;
      LAYER met1 ;
        RECT 5.060 1173.065 421.430 1173.295 ;
      LAYER met1 ;
        RECT 421.430 1173.065 724.315 1173.295 ;
      LAYER met1 ;
        RECT 5.060 1172.035 421.000 1173.065 ;
      LAYER met1 ;
        RECT 421.000 1172.035 724.315 1173.065 ;
      LAYER met1 ;
        RECT 5.060 1171.805 421.500 1172.035 ;
      LAYER met1 ;
        RECT 421.500 1171.805 724.315 1172.035 ;
      LAYER met1 ;
        RECT 5.060 1167.275 421.000 1171.805 ;
      LAYER met1 ;
        RECT 421.000 1167.275 724.315 1171.805 ;
      LAYER met1 ;
        RECT 5.060 1167.045 421.500 1167.275 ;
      LAYER met1 ;
        RECT 421.500 1167.045 724.315 1167.275 ;
      LAYER met1 ;
        RECT 5.060 1165.125 421.000 1167.045 ;
      LAYER met1 ;
        RECT 421.000 1165.125 724.315 1167.045 ;
      LAYER met1 ;
        RECT 5.060 1163.755 422.000 1165.125 ;
      LAYER met1 ;
        RECT 422.000 1163.755 724.315 1165.125 ;
      LAYER met1 ;
        RECT 5.060 1162.395 421.000 1163.755 ;
      LAYER met1 ;
        RECT 421.000 1162.395 724.315 1163.755 ;
      LAYER met1 ;
        RECT 5.060 1162.165 421.430 1162.395 ;
      LAYER met1 ;
        RECT 421.430 1162.165 724.315 1162.395 ;
      LAYER met1 ;
        RECT 5.060 1161.135 421.000 1162.165 ;
      LAYER met1 ;
        RECT 421.000 1161.135 724.315 1162.165 ;
      LAYER met1 ;
        RECT 5.060 1160.905 421.500 1161.135 ;
      LAYER met1 ;
        RECT 421.500 1160.905 724.315 1161.135 ;
      LAYER met1 ;
        RECT 5.060 1156.375 421.000 1160.905 ;
      LAYER met1 ;
        RECT 421.000 1156.375 724.315 1160.905 ;
      LAYER met1 ;
        RECT 5.060 1156.145 421.500 1156.375 ;
      LAYER met1 ;
        RECT 421.500 1156.145 724.315 1156.375 ;
      LAYER met1 ;
        RECT 5.060 1154.225 421.000 1156.145 ;
      LAYER met1 ;
        RECT 421.000 1154.225 724.315 1156.145 ;
      LAYER met1 ;
        RECT 5.060 1152.855 422.000 1154.225 ;
      LAYER met1 ;
        RECT 422.000 1152.855 724.315 1154.225 ;
      LAYER met1 ;
        RECT 5.060 1151.495 421.000 1152.855 ;
      LAYER met1 ;
        RECT 421.000 1151.495 724.315 1152.855 ;
      LAYER met1 ;
        RECT 5.060 1151.265 421.430 1151.495 ;
      LAYER met1 ;
        RECT 421.430 1151.265 724.315 1151.495 ;
      LAYER met1 ;
        RECT 5.060 1150.235 421.000 1151.265 ;
      LAYER met1 ;
        RECT 421.000 1150.235 724.315 1151.265 ;
      LAYER met1 ;
        RECT 5.060 1150.005 421.500 1150.235 ;
      LAYER met1 ;
        RECT 421.500 1150.005 724.315 1150.235 ;
      LAYER met1 ;
        RECT 5.060 1145.475 421.000 1150.005 ;
      LAYER met1 ;
        RECT 421.000 1145.475 724.315 1150.005 ;
      LAYER met1 ;
        RECT 5.060 1145.245 421.500 1145.475 ;
      LAYER met1 ;
        RECT 421.500 1145.245 724.315 1145.475 ;
      LAYER met1 ;
        RECT 5.060 1143.325 421.000 1145.245 ;
      LAYER met1 ;
        RECT 421.000 1143.325 724.315 1145.245 ;
      LAYER met1 ;
        RECT 5.060 1141.955 422.000 1143.325 ;
      LAYER met1 ;
        RECT 422.000 1141.955 724.315 1143.325 ;
      LAYER met1 ;
        RECT 5.060 1140.595 421.000 1141.955 ;
      LAYER met1 ;
        RECT 421.000 1140.595 724.315 1141.955 ;
      LAYER met1 ;
        RECT 5.060 1140.365 421.430 1140.595 ;
      LAYER met1 ;
        RECT 421.430 1140.365 724.315 1140.595 ;
      LAYER met1 ;
        RECT 5.060 1139.335 421.000 1140.365 ;
      LAYER met1 ;
        RECT 421.000 1139.335 724.315 1140.365 ;
      LAYER met1 ;
        RECT 5.060 1139.105 421.500 1139.335 ;
      LAYER met1 ;
        RECT 421.500 1139.105 724.315 1139.335 ;
      LAYER met1 ;
        RECT 5.060 1134.575 421.000 1139.105 ;
      LAYER met1 ;
        RECT 421.000 1134.575 724.315 1139.105 ;
      LAYER met1 ;
        RECT 5.060 1134.345 421.500 1134.575 ;
      LAYER met1 ;
        RECT 421.500 1134.345 724.315 1134.575 ;
      LAYER met1 ;
        RECT 5.060 1132.425 421.000 1134.345 ;
      LAYER met1 ;
        RECT 421.000 1132.425 724.315 1134.345 ;
      LAYER met1 ;
        RECT 5.060 1131.055 422.000 1132.425 ;
      LAYER met1 ;
        RECT 422.000 1131.055 724.315 1132.425 ;
      LAYER met1 ;
        RECT 5.060 1129.695 421.000 1131.055 ;
      LAYER met1 ;
        RECT 421.000 1129.695 724.315 1131.055 ;
      LAYER met1 ;
        RECT 5.060 1129.465 421.430 1129.695 ;
      LAYER met1 ;
        RECT 421.430 1129.465 724.315 1129.695 ;
      LAYER met1 ;
        RECT 5.060 1128.435 421.000 1129.465 ;
      LAYER met1 ;
        RECT 421.000 1128.435 724.315 1129.465 ;
      LAYER met1 ;
        RECT 5.060 1128.205 421.500 1128.435 ;
      LAYER met1 ;
        RECT 421.500 1128.205 724.315 1128.435 ;
      LAYER met1 ;
        RECT 5.060 1123.675 421.000 1128.205 ;
      LAYER met1 ;
        RECT 421.000 1123.675 724.315 1128.205 ;
      LAYER met1 ;
        RECT 5.060 1123.445 421.500 1123.675 ;
      LAYER met1 ;
        RECT 421.500 1123.445 724.315 1123.675 ;
      LAYER met1 ;
        RECT 5.060 1121.525 421.000 1123.445 ;
      LAYER met1 ;
        RECT 421.000 1121.525 724.315 1123.445 ;
      LAYER met1 ;
        RECT 5.060 1120.155 422.000 1121.525 ;
      LAYER met1 ;
        RECT 422.000 1120.155 724.315 1121.525 ;
      LAYER met1 ;
        RECT 5.060 1118.795 421.000 1120.155 ;
      LAYER met1 ;
        RECT 421.000 1118.795 724.315 1120.155 ;
      LAYER met1 ;
        RECT 5.060 1118.565 421.430 1118.795 ;
      LAYER met1 ;
        RECT 421.430 1118.565 724.315 1118.795 ;
      LAYER met1 ;
        RECT 5.060 1117.535 421.000 1118.565 ;
      LAYER met1 ;
        RECT 421.000 1117.535 724.315 1118.565 ;
      LAYER met1 ;
        RECT 5.060 1117.305 421.500 1117.535 ;
      LAYER met1 ;
        RECT 421.500 1117.305 724.315 1117.535 ;
      LAYER met1 ;
        RECT 5.060 1112.775 421.000 1117.305 ;
      LAYER met1 ;
        RECT 421.000 1112.775 724.315 1117.305 ;
      LAYER met1 ;
        RECT 5.060 1112.545 421.500 1112.775 ;
      LAYER met1 ;
        RECT 421.500 1112.545 724.315 1112.775 ;
      LAYER met1 ;
        RECT 5.060 1110.625 421.000 1112.545 ;
      LAYER met1 ;
        RECT 421.000 1110.625 724.315 1112.545 ;
      LAYER met1 ;
        RECT 5.060 1109.255 422.000 1110.625 ;
      LAYER met1 ;
        RECT 422.000 1109.255 724.315 1110.625 ;
      LAYER met1 ;
        RECT 5.060 1107.895 421.000 1109.255 ;
      LAYER met1 ;
        RECT 421.000 1107.895 724.315 1109.255 ;
      LAYER met1 ;
        RECT 5.060 1107.665 421.430 1107.895 ;
      LAYER met1 ;
        RECT 421.430 1107.665 724.315 1107.895 ;
      LAYER met1 ;
        RECT 5.060 1106.635 421.000 1107.665 ;
      LAYER met1 ;
        RECT 421.000 1106.635 724.315 1107.665 ;
      LAYER met1 ;
        RECT 5.060 1106.405 421.500 1106.635 ;
      LAYER met1 ;
        RECT 421.500 1106.405 724.315 1106.635 ;
      LAYER met1 ;
        RECT 5.060 1101.875 421.000 1106.405 ;
      LAYER met1 ;
        RECT 421.000 1101.875 724.315 1106.405 ;
      LAYER met1 ;
        RECT 5.060 1101.645 421.500 1101.875 ;
      LAYER met1 ;
        RECT 421.500 1101.645 724.315 1101.875 ;
      LAYER met1 ;
        RECT 5.060 1099.725 421.000 1101.645 ;
      LAYER met1 ;
        RECT 421.000 1099.725 724.315 1101.645 ;
      LAYER met1 ;
        RECT 5.060 1098.355 422.000 1099.725 ;
      LAYER met1 ;
        RECT 422.000 1098.355 724.315 1099.725 ;
      LAYER met1 ;
        RECT 5.060 1096.995 421.000 1098.355 ;
      LAYER met1 ;
        RECT 421.000 1096.995 724.315 1098.355 ;
      LAYER met1 ;
        RECT 5.060 1096.765 421.430 1096.995 ;
      LAYER met1 ;
        RECT 421.430 1096.765 724.315 1096.995 ;
      LAYER met1 ;
        RECT 5.060 1095.735 421.000 1096.765 ;
      LAYER met1 ;
        RECT 421.000 1095.735 724.315 1096.765 ;
      LAYER met1 ;
        RECT 5.060 1095.505 421.500 1095.735 ;
      LAYER met1 ;
        RECT 421.500 1095.505 724.315 1095.735 ;
      LAYER met1 ;
        RECT 5.060 1090.975 421.000 1095.505 ;
      LAYER met1 ;
        RECT 421.000 1090.975 724.315 1095.505 ;
      LAYER met1 ;
        RECT 5.060 1090.745 421.500 1090.975 ;
      LAYER met1 ;
        RECT 421.500 1090.745 724.315 1090.975 ;
      LAYER met1 ;
        RECT 5.060 1088.825 421.000 1090.745 ;
      LAYER met1 ;
        RECT 421.000 1088.825 724.315 1090.745 ;
      LAYER met1 ;
        RECT 5.060 1087.455 422.000 1088.825 ;
      LAYER met1 ;
        RECT 422.000 1087.455 724.315 1088.825 ;
      LAYER met1 ;
        RECT 5.060 1086.095 421.000 1087.455 ;
      LAYER met1 ;
        RECT 421.000 1086.095 724.315 1087.455 ;
      LAYER met1 ;
        RECT 5.060 1085.865 421.430 1086.095 ;
      LAYER met1 ;
        RECT 421.430 1085.865 724.315 1086.095 ;
      LAYER met1 ;
        RECT 5.060 1084.835 421.000 1085.865 ;
      LAYER met1 ;
        RECT 421.000 1084.835 724.315 1085.865 ;
      LAYER met1 ;
        RECT 5.060 1084.605 421.500 1084.835 ;
      LAYER met1 ;
        RECT 421.500 1084.605 724.315 1084.835 ;
      LAYER met1 ;
        RECT 5.060 1080.075 421.000 1084.605 ;
      LAYER met1 ;
        RECT 421.000 1080.075 724.315 1084.605 ;
      LAYER met1 ;
        RECT 5.060 1079.845 421.500 1080.075 ;
      LAYER met1 ;
        RECT 421.500 1079.845 724.315 1080.075 ;
      LAYER met1 ;
        RECT 5.060 1077.925 421.000 1079.845 ;
      LAYER met1 ;
        RECT 421.000 1077.925 724.315 1079.845 ;
      LAYER met1 ;
        RECT 5.060 1076.555 422.000 1077.925 ;
      LAYER met1 ;
        RECT 422.000 1076.555 724.315 1077.925 ;
      LAYER met1 ;
        RECT 5.060 1075.195 421.000 1076.555 ;
      LAYER met1 ;
        RECT 421.000 1075.195 724.315 1076.555 ;
      LAYER met1 ;
        RECT 5.060 1074.965 421.430 1075.195 ;
      LAYER met1 ;
        RECT 421.430 1074.965 724.315 1075.195 ;
      LAYER met1 ;
        RECT 5.060 1073.935 421.000 1074.965 ;
      LAYER met1 ;
        RECT 421.000 1073.935 724.315 1074.965 ;
      LAYER met1 ;
        RECT 5.060 1073.705 421.500 1073.935 ;
      LAYER met1 ;
        RECT 421.500 1073.705 724.315 1073.935 ;
      LAYER met1 ;
        RECT 5.060 1069.175 421.000 1073.705 ;
      LAYER met1 ;
        RECT 421.000 1069.175 724.315 1073.705 ;
      LAYER met1 ;
        RECT 5.060 1068.945 421.500 1069.175 ;
      LAYER met1 ;
        RECT 421.500 1068.945 724.315 1069.175 ;
      LAYER met1 ;
        RECT 5.060 1067.025 421.000 1068.945 ;
      LAYER met1 ;
        RECT 421.000 1067.025 724.315 1068.945 ;
      LAYER met1 ;
        RECT 5.060 1065.655 422.000 1067.025 ;
      LAYER met1 ;
        RECT 422.000 1065.655 724.315 1067.025 ;
      LAYER met1 ;
        RECT 5.060 1064.295 421.000 1065.655 ;
      LAYER met1 ;
        RECT 421.000 1064.295 724.315 1065.655 ;
      LAYER met1 ;
        RECT 5.060 1064.065 421.430 1064.295 ;
      LAYER met1 ;
        RECT 421.430 1064.065 724.315 1064.295 ;
      LAYER met1 ;
        RECT 5.060 1063.035 421.000 1064.065 ;
      LAYER met1 ;
        RECT 421.000 1063.035 724.315 1064.065 ;
      LAYER met1 ;
        RECT 5.060 1062.805 421.500 1063.035 ;
      LAYER met1 ;
        RECT 421.500 1062.805 724.315 1063.035 ;
      LAYER met1 ;
        RECT 5.060 1058.275 421.000 1062.805 ;
      LAYER met1 ;
        RECT 421.000 1058.275 724.315 1062.805 ;
      LAYER met1 ;
        RECT 5.060 1058.045 421.500 1058.275 ;
      LAYER met1 ;
        RECT 421.500 1058.045 724.315 1058.275 ;
      LAYER met1 ;
        RECT 5.060 1056.455 421.000 1058.045 ;
      LAYER met1 ;
        RECT 421.000 1056.455 724.315 1058.045 ;
      LAYER met1 ;
        RECT 5.060 1056.265 422.015 1056.455 ;
      LAYER met1 ;
        RECT 422.015 1056.265 724.315 1056.455 ;
      LAYER met1 ;
        RECT 5.060 1056.125 421.000 1056.265 ;
      LAYER met1 ;
        RECT 421.000 1056.125 724.315 1056.265 ;
      LAYER met1 ;
        RECT 5.060 1054.755 422.000 1056.125 ;
      LAYER met1 ;
        RECT 422.000 1054.755 724.315 1056.125 ;
      LAYER met1 ;
        RECT 5.060 1053.395 421.000 1054.755 ;
      LAYER met1 ;
        RECT 421.000 1053.395 724.315 1054.755 ;
      LAYER met1 ;
        RECT 5.060 1053.165 421.430 1053.395 ;
      LAYER met1 ;
        RECT 421.430 1053.165 724.315 1053.395 ;
      LAYER met1 ;
        RECT 5.060 1052.135 421.000 1053.165 ;
      LAYER met1 ;
        RECT 421.000 1052.135 724.315 1053.165 ;
      LAYER met1 ;
        RECT 5.060 1051.905 421.500 1052.135 ;
      LAYER met1 ;
        RECT 421.500 1051.905 724.315 1052.135 ;
      LAYER met1 ;
        RECT 5.060 1050.230 421.000 1051.905 ;
      LAYER met1 ;
        RECT 421.000 1050.230 724.315 1051.905 ;
      LAYER met1 ;
        RECT 5.060 1049.970 421.630 1050.230 ;
      LAYER met1 ;
        RECT 421.630 1049.970 724.315 1050.230 ;
      LAYER met1 ;
        RECT 5.060 1049.305 421.000 1049.970 ;
      LAYER met1 ;
        RECT 421.000 1049.305 724.315 1049.970 ;
      LAYER met1 ;
        RECT 5.060 1049.045 421.620 1049.305 ;
      LAYER met1 ;
        RECT 421.620 1049.045 724.315 1049.305 ;
      LAYER met1 ;
        RECT 5.060 1046.165 421.000 1049.045 ;
      LAYER met1 ;
        RECT 421.000 1046.165 724.315 1049.045 ;
      LAYER met1 ;
        RECT 5.060 1045.905 421.605 1046.165 ;
      LAYER met1 ;
        RECT 421.605 1045.905 724.315 1046.165 ;
      LAYER met1 ;
        RECT 5.060 1045.765 421.000 1045.905 ;
      LAYER met1 ;
        RECT 421.000 1045.765 724.315 1045.905 ;
      LAYER met1 ;
        RECT 5.060 1045.505 421.610 1045.765 ;
      LAYER met1 ;
        RECT 421.610 1045.505 724.315 1045.765 ;
      LAYER met1 ;
        RECT 5.060 1042.625 421.000 1045.505 ;
      LAYER met1 ;
        RECT 421.000 1042.625 724.315 1045.505 ;
      LAYER met1 ;
        RECT 5.060 1042.365 421.550 1042.625 ;
      LAYER met1 ;
        RECT 421.550 1042.365 724.315 1042.625 ;
      LAYER met1 ;
        RECT 5.060 1042.225 421.000 1042.365 ;
      LAYER met1 ;
        RECT 421.000 1042.225 724.315 1042.365 ;
      LAYER met1 ;
        RECT 5.060 1041.965 421.535 1042.225 ;
      LAYER met1 ;
        RECT 421.535 1041.965 724.315 1042.225 ;
      LAYER met1 ;
        RECT 5.060 1039.085 421.000 1041.965 ;
      LAYER met1 ;
        RECT 421.000 1039.085 724.315 1041.965 ;
      LAYER met1 ;
        RECT 5.060 1038.825 421.590 1039.085 ;
      LAYER met1 ;
        RECT 421.590 1038.825 724.315 1039.085 ;
      LAYER met1 ;
        RECT 5.060 1038.685 421.000 1038.825 ;
      LAYER met1 ;
        RECT 421.000 1038.685 724.315 1038.825 ;
      LAYER met1 ;
        RECT 5.060 1038.425 421.575 1038.685 ;
      LAYER met1 ;
        RECT 421.575 1038.425 724.315 1038.685 ;
      LAYER met1 ;
        RECT 5.060 1032.005 421.000 1038.425 ;
      LAYER met1 ;
        RECT 421.000 1034.565 724.315 1038.425 ;
        RECT 421.000 1034.305 724.055 1034.565 ;
      LAYER met1 ;
        RECT 724.055 1034.305 724.775 1034.565 ;
      LAYER met1 ;
        RECT 421.000 1032.005 724.315 1034.305 ;
      LAYER met1 ;
        RECT 5.060 1031.745 421.510 1032.005 ;
      LAYER met1 ;
        RECT 421.510 1031.745 724.315 1032.005 ;
      LAYER met1 ;
        RECT 5.060 1031.605 421.000 1031.745 ;
      LAYER met1 ;
        RECT 421.000 1031.605 724.315 1031.745 ;
      LAYER met1 ;
        RECT 5.060 1031.345 421.510 1031.605 ;
      LAYER met1 ;
        RECT 421.510 1031.345 724.315 1031.605 ;
      LAYER met1 ;
        RECT 5.060 1028.465 421.000 1031.345 ;
      LAYER met1 ;
        RECT 421.000 1028.465 724.315 1031.345 ;
      LAYER met1 ;
        RECT 5.060 1028.205 421.510 1028.465 ;
      LAYER met1 ;
        RECT 421.510 1028.205 724.315 1028.465 ;
      LAYER met1 ;
        RECT 5.060 1028.065 421.000 1028.205 ;
      LAYER met1 ;
        RECT 421.000 1028.065 724.315 1028.205 ;
      LAYER met1 ;
        RECT 5.060 1027.805 421.505 1028.065 ;
      LAYER met1 ;
        RECT 421.505 1027.805 724.315 1028.065 ;
      LAYER met1 ;
        RECT 5.060 1024.920 421.000 1027.805 ;
      LAYER met1 ;
        RECT 421.000 1024.920 724.315 1027.805 ;
      LAYER met1 ;
        RECT 5.060 1024.665 421.675 1024.920 ;
      LAYER met1 ;
        RECT 421.675 1024.665 724.315 1024.920 ;
      LAYER met1 ;
        RECT 5.060 1024.525 421.000 1024.665 ;
      LAYER met1 ;
        RECT 421.000 1024.525 724.315 1024.665 ;
      LAYER met1 ;
        RECT 5.060 1024.265 421.665 1024.525 ;
      LAYER met1 ;
        RECT 421.665 1024.265 724.315 1024.525 ;
      LAYER met1 ;
        RECT 5.060 1020.185 421.000 1024.265 ;
      LAYER met1 ;
        RECT 421.000 1020.185 724.315 1024.265 ;
      LAYER met1 ;
        RECT 5.060 1019.985 421.865 1020.185 ;
      LAYER met1 ;
        RECT 421.865 1019.985 724.315 1020.185 ;
      LAYER met1 ;
        RECT 5.060 1019.845 421.000 1019.985 ;
      LAYER met1 ;
        RECT 421.000 1019.845 724.315 1019.985 ;
      LAYER met1 ;
        RECT 5.060 1019.645 421.880 1019.845 ;
      LAYER met1 ;
        RECT 421.880 1019.645 724.315 1019.845 ;
      LAYER met1 ;
        RECT 5.060 1018.485 421.000 1019.645 ;
      LAYER met1 ;
        RECT 421.000 1018.485 724.315 1019.645 ;
      LAYER met1 ;
        RECT 5.060 1018.295 421.785 1018.485 ;
      LAYER met1 ;
        RECT 421.785 1018.295 724.315 1018.485 ;
      LAYER met1 ;
        RECT 5.060 1016.965 421.000 1018.295 ;
      LAYER met1 ;
        RECT 421.000 1016.965 724.315 1018.295 ;
      LAYER met1 ;
        RECT 5.060 1016.735 421.500 1016.965 ;
      LAYER met1 ;
        RECT 421.500 1016.735 724.315 1016.965 ;
      LAYER met1 ;
        RECT 5.060 1015.705 421.000 1016.735 ;
      LAYER met1 ;
        RECT 421.000 1015.705 724.315 1016.735 ;
      LAYER met1 ;
        RECT 5.060 1015.475 421.430 1015.705 ;
      LAYER met1 ;
        RECT 421.430 1015.475 724.315 1015.705 ;
      LAYER met1 ;
        RECT 5.060 1014.115 421.000 1015.475 ;
      LAYER met1 ;
        RECT 421.000 1014.115 724.315 1015.475 ;
      LAYER met1 ;
        RECT 5.060 1012.745 422.000 1014.115 ;
      LAYER met1 ;
        RECT 422.000 1012.745 724.315 1014.115 ;
      LAYER met1 ;
        RECT 5.060 1010.825 421.000 1012.745 ;
      LAYER met1 ;
        RECT 421.000 1010.825 724.315 1012.745 ;
      LAYER met1 ;
        RECT 5.060 1010.595 421.500 1010.825 ;
      LAYER met1 ;
        RECT 421.500 1010.595 724.315 1010.825 ;
      LAYER met1 ;
        RECT 5.060 1008.025 421.000 1010.595 ;
      LAYER met1 ;
        RECT 421.000 1008.025 724.315 1010.595 ;
      LAYER met1 ;
        RECT 5.060 1007.775 421.630 1008.025 ;
      LAYER met1 ;
        RECT 421.630 1007.775 724.315 1008.025 ;
      LAYER met1 ;
        RECT 5.060 1007.635 421.000 1007.775 ;
      LAYER met1 ;
        RECT 421.000 1007.635 724.315 1007.775 ;
      LAYER met1 ;
        RECT 5.060 1007.395 421.635 1007.635 ;
      LAYER met1 ;
        RECT 421.635 1007.395 724.315 1007.635 ;
      LAYER met1 ;
        RECT 5.060 1006.065 421.000 1007.395 ;
      LAYER met1 ;
        RECT 421.000 1006.065 724.315 1007.395 ;
      LAYER met1 ;
        RECT 5.060 1005.835 421.500 1006.065 ;
      LAYER met1 ;
        RECT 421.500 1005.835 724.315 1006.065 ;
      LAYER met1 ;
        RECT 5.060 1004.805 421.000 1005.835 ;
      LAYER met1 ;
        RECT 421.000 1004.805 724.315 1005.835 ;
      LAYER met1 ;
        RECT 5.060 1004.575 421.430 1004.805 ;
      LAYER met1 ;
        RECT 421.430 1004.575 724.315 1004.805 ;
      LAYER met1 ;
        RECT 5.060 1003.215 421.000 1004.575 ;
      LAYER met1 ;
        RECT 421.000 1003.215 724.315 1004.575 ;
      LAYER met1 ;
        RECT 5.060 1001.845 422.000 1003.215 ;
      LAYER met1 ;
        RECT 422.000 1001.845 724.315 1003.215 ;
      LAYER met1 ;
        RECT 5.060 1001.325 421.000 1001.845 ;
      LAYER met1 ;
        RECT 421.000 1001.325 724.315 1001.845 ;
      LAYER met1 ;
        RECT 5.060 1001.095 421.645 1001.325 ;
      LAYER met1 ;
        RECT 421.645 1001.095 724.315 1001.325 ;
      LAYER met1 ;
        RECT 5.060 999.925 421.000 1001.095 ;
      LAYER met1 ;
        RECT 421.000 999.925 724.315 1001.095 ;
      LAYER met1 ;
        RECT 5.060 999.695 421.500 999.925 ;
      LAYER met1 ;
        RECT 421.500 999.695 724.315 999.925 ;
      LAYER met1 ;
        RECT 5.060 995.165 421.000 999.695 ;
      LAYER met1 ;
        RECT 421.000 995.165 724.315 999.695 ;
      LAYER met1 ;
        RECT 5.060 994.935 421.500 995.165 ;
      LAYER met1 ;
        RECT 421.500 994.935 724.315 995.165 ;
      LAYER met1 ;
        RECT 5.060 993.905 421.000 994.935 ;
      LAYER met1 ;
        RECT 421.000 993.905 724.315 994.935 ;
      LAYER met1 ;
        RECT 5.060 993.675 421.430 993.905 ;
      LAYER met1 ;
        RECT 421.430 993.675 724.315 993.905 ;
      LAYER met1 ;
        RECT 5.060 992.315 421.000 993.675 ;
      LAYER met1 ;
        RECT 421.000 992.315 724.315 993.675 ;
      LAYER met1 ;
        RECT 5.060 990.945 422.000 992.315 ;
      LAYER met1 ;
        RECT 422.000 990.945 724.315 992.315 ;
      LAYER met1 ;
        RECT 5.060 989.025 421.000 990.945 ;
      LAYER met1 ;
        RECT 421.000 989.025 724.315 990.945 ;
      LAYER met1 ;
        RECT 5.060 988.795 421.500 989.025 ;
      LAYER met1 ;
        RECT 421.500 988.795 724.315 989.025 ;
      LAYER met1 ;
        RECT 5.060 984.265 421.000 988.795 ;
      LAYER met1 ;
        RECT 421.000 984.265 724.315 988.795 ;
      LAYER met1 ;
        RECT 5.060 984.035 421.500 984.265 ;
      LAYER met1 ;
        RECT 421.500 984.035 724.315 984.265 ;
      LAYER met1 ;
        RECT 5.060 983.005 421.000 984.035 ;
      LAYER met1 ;
        RECT 421.000 983.005 724.315 984.035 ;
      LAYER met1 ;
        RECT 5.060 982.775 421.430 983.005 ;
      LAYER met1 ;
        RECT 421.430 982.775 724.315 983.005 ;
      LAYER met1 ;
        RECT 5.060 981.415 421.000 982.775 ;
      LAYER met1 ;
        RECT 421.000 981.415 724.315 982.775 ;
      LAYER met1 ;
        RECT 5.060 980.045 422.000 981.415 ;
      LAYER met1 ;
        RECT 422.000 980.045 724.315 981.415 ;
      LAYER met1 ;
        RECT 5.060 978.125 421.000 980.045 ;
      LAYER met1 ;
        RECT 421.000 978.125 724.315 980.045 ;
      LAYER met1 ;
        RECT 5.060 977.895 421.500 978.125 ;
      LAYER met1 ;
        RECT 421.500 977.895 724.315 978.125 ;
      LAYER met1 ;
        RECT 5.060 973.365 421.000 977.895 ;
      LAYER met1 ;
        RECT 421.000 973.365 724.315 977.895 ;
      LAYER met1 ;
        RECT 5.060 973.135 421.500 973.365 ;
      LAYER met1 ;
        RECT 421.500 973.135 724.315 973.365 ;
      LAYER met1 ;
        RECT 5.060 972.105 421.000 973.135 ;
      LAYER met1 ;
        RECT 421.000 972.105 724.315 973.135 ;
      LAYER met1 ;
        RECT 5.060 971.875 421.430 972.105 ;
      LAYER met1 ;
        RECT 421.430 971.875 724.315 972.105 ;
      LAYER met1 ;
        RECT 5.060 970.515 421.000 971.875 ;
      LAYER met1 ;
        RECT 421.000 970.515 724.315 971.875 ;
      LAYER met1 ;
        RECT 5.060 969.145 422.000 970.515 ;
      LAYER met1 ;
        RECT 422.000 969.145 724.315 970.515 ;
      LAYER met1 ;
        RECT 5.060 967.225 421.000 969.145 ;
      LAYER met1 ;
        RECT 421.000 967.225 724.315 969.145 ;
      LAYER met1 ;
        RECT 5.060 966.995 421.500 967.225 ;
      LAYER met1 ;
        RECT 421.500 966.995 724.315 967.225 ;
      LAYER met1 ;
        RECT 5.060 962.465 421.000 966.995 ;
      LAYER met1 ;
        RECT 421.000 962.465 724.315 966.995 ;
      LAYER met1 ;
        RECT 5.060 962.235 421.500 962.465 ;
      LAYER met1 ;
        RECT 421.500 962.235 724.315 962.465 ;
      LAYER met1 ;
        RECT 5.060 961.205 421.000 962.235 ;
      LAYER met1 ;
        RECT 421.000 961.205 724.315 962.235 ;
      LAYER met1 ;
        RECT 5.060 960.975 421.430 961.205 ;
      LAYER met1 ;
        RECT 421.430 960.975 724.315 961.205 ;
      LAYER met1 ;
        RECT 5.060 959.615 421.000 960.975 ;
      LAYER met1 ;
        RECT 421.000 959.615 724.315 960.975 ;
      LAYER met1 ;
        RECT 5.060 958.245 422.000 959.615 ;
      LAYER met1 ;
        RECT 422.000 958.245 724.315 959.615 ;
      LAYER met1 ;
        RECT 5.060 956.325 421.000 958.245 ;
      LAYER met1 ;
        RECT 421.000 956.325 724.315 958.245 ;
      LAYER met1 ;
        RECT 5.060 956.095 421.500 956.325 ;
      LAYER met1 ;
        RECT 421.500 956.095 724.315 956.325 ;
      LAYER met1 ;
        RECT 5.060 951.565 421.000 956.095 ;
      LAYER met1 ;
        RECT 421.000 951.565 724.315 956.095 ;
      LAYER met1 ;
        RECT 5.060 951.335 421.500 951.565 ;
      LAYER met1 ;
        RECT 421.500 951.335 724.315 951.565 ;
      LAYER met1 ;
        RECT 5.060 950.305 421.000 951.335 ;
      LAYER met1 ;
        RECT 421.000 950.305 724.315 951.335 ;
      LAYER met1 ;
        RECT 5.060 950.075 421.430 950.305 ;
      LAYER met1 ;
        RECT 421.430 950.075 724.315 950.305 ;
      LAYER met1 ;
        RECT 5.060 948.715 421.000 950.075 ;
      LAYER met1 ;
        RECT 421.000 948.715 724.315 950.075 ;
      LAYER met1 ;
        RECT 5.060 947.345 422.000 948.715 ;
      LAYER met1 ;
        RECT 422.000 947.345 724.315 948.715 ;
      LAYER met1 ;
        RECT 5.060 945.425 421.000 947.345 ;
      LAYER met1 ;
        RECT 421.000 945.425 724.315 947.345 ;
      LAYER met1 ;
        RECT 5.060 945.195 421.500 945.425 ;
      LAYER met1 ;
        RECT 421.500 945.195 724.315 945.425 ;
      LAYER met1 ;
        RECT 5.060 940.665 421.000 945.195 ;
      LAYER met1 ;
        RECT 421.000 940.665 724.315 945.195 ;
      LAYER met1 ;
        RECT 5.060 940.435 421.500 940.665 ;
      LAYER met1 ;
        RECT 421.500 940.435 724.315 940.665 ;
      LAYER met1 ;
        RECT 5.060 939.405 421.000 940.435 ;
      LAYER met1 ;
        RECT 421.000 939.405 724.315 940.435 ;
      LAYER met1 ;
        RECT 5.060 939.175 421.430 939.405 ;
      LAYER met1 ;
        RECT 421.430 939.175 724.315 939.405 ;
      LAYER met1 ;
        RECT 5.060 937.815 421.000 939.175 ;
      LAYER met1 ;
        RECT 421.000 937.815 724.315 939.175 ;
      LAYER met1 ;
        RECT 5.060 936.445 422.000 937.815 ;
      LAYER met1 ;
        RECT 422.000 936.445 724.315 937.815 ;
      LAYER met1 ;
        RECT 5.060 934.525 421.000 936.445 ;
      LAYER met1 ;
        RECT 421.000 934.525 724.315 936.445 ;
      LAYER met1 ;
        RECT 5.060 934.295 421.500 934.525 ;
      LAYER met1 ;
        RECT 421.500 934.295 724.315 934.525 ;
      LAYER met1 ;
        RECT 5.060 929.765 421.000 934.295 ;
      LAYER met1 ;
        RECT 421.000 929.765 724.315 934.295 ;
      LAYER met1 ;
        RECT 5.060 929.535 421.500 929.765 ;
      LAYER met1 ;
        RECT 421.500 929.535 724.315 929.765 ;
      LAYER met1 ;
        RECT 5.060 928.505 421.000 929.535 ;
      LAYER met1 ;
        RECT 421.000 928.505 724.315 929.535 ;
      LAYER met1 ;
        RECT 5.060 928.275 421.430 928.505 ;
      LAYER met1 ;
        RECT 421.430 928.275 724.315 928.505 ;
      LAYER met1 ;
        RECT 5.060 926.915 421.000 928.275 ;
      LAYER met1 ;
        RECT 421.000 926.915 724.315 928.275 ;
      LAYER met1 ;
        RECT 5.060 925.545 422.000 926.915 ;
      LAYER met1 ;
        RECT 422.000 925.545 724.315 926.915 ;
      LAYER met1 ;
        RECT 5.060 923.625 421.000 925.545 ;
      LAYER met1 ;
        RECT 421.000 923.625 724.315 925.545 ;
      LAYER met1 ;
        RECT 5.060 923.395 421.500 923.625 ;
      LAYER met1 ;
        RECT 421.500 923.395 724.315 923.625 ;
      LAYER met1 ;
        RECT 5.060 918.865 421.000 923.395 ;
      LAYER met1 ;
        RECT 421.000 918.865 724.315 923.395 ;
      LAYER met1 ;
        RECT 5.060 918.635 421.500 918.865 ;
      LAYER met1 ;
        RECT 421.500 918.635 724.315 918.865 ;
      LAYER met1 ;
        RECT 5.060 917.605 421.000 918.635 ;
      LAYER met1 ;
        RECT 421.000 917.605 724.315 918.635 ;
      LAYER met1 ;
        RECT 5.060 917.375 421.430 917.605 ;
      LAYER met1 ;
        RECT 421.430 917.375 724.315 917.605 ;
      LAYER met1 ;
        RECT 5.060 916.015 421.000 917.375 ;
      LAYER met1 ;
        RECT 421.000 916.015 724.315 917.375 ;
      LAYER met1 ;
        RECT 5.060 914.645 422.000 916.015 ;
      LAYER met1 ;
        RECT 422.000 914.645 724.315 916.015 ;
      LAYER met1 ;
        RECT 5.060 912.725 421.000 914.645 ;
      LAYER met1 ;
        RECT 421.000 912.725 724.315 914.645 ;
      LAYER met1 ;
        RECT 5.060 912.495 421.500 912.725 ;
      LAYER met1 ;
        RECT 421.500 912.495 724.315 912.725 ;
      LAYER met1 ;
        RECT 5.060 907.965 421.000 912.495 ;
      LAYER met1 ;
        RECT 421.000 907.965 724.315 912.495 ;
      LAYER met1 ;
        RECT 5.060 907.735 421.500 907.965 ;
      LAYER met1 ;
        RECT 421.500 907.735 724.315 907.965 ;
      LAYER met1 ;
        RECT 5.060 906.705 421.000 907.735 ;
      LAYER met1 ;
        RECT 421.000 906.705 724.315 907.735 ;
      LAYER met1 ;
        RECT 5.060 906.475 421.430 906.705 ;
      LAYER met1 ;
        RECT 421.430 906.475 724.315 906.705 ;
      LAYER met1 ;
        RECT 5.060 905.115 421.000 906.475 ;
      LAYER met1 ;
        RECT 421.000 905.115 724.315 906.475 ;
      LAYER met1 ;
        RECT 5.060 903.745 422.000 905.115 ;
      LAYER met1 ;
        RECT 422.000 903.745 724.315 905.115 ;
      LAYER met1 ;
        RECT 5.060 901.825 421.000 903.745 ;
      LAYER met1 ;
        RECT 421.000 901.825 724.315 903.745 ;
      LAYER met1 ;
        RECT 5.060 901.595 421.500 901.825 ;
      LAYER met1 ;
        RECT 421.500 901.595 724.315 901.825 ;
      LAYER met1 ;
        RECT 5.060 897.065 421.000 901.595 ;
      LAYER met1 ;
        RECT 421.000 897.065 724.315 901.595 ;
      LAYER met1 ;
        RECT 5.060 896.835 421.500 897.065 ;
      LAYER met1 ;
        RECT 421.500 896.835 724.315 897.065 ;
      LAYER met1 ;
        RECT 5.060 895.805 421.000 896.835 ;
      LAYER met1 ;
        RECT 421.000 895.805 724.315 896.835 ;
      LAYER met1 ;
        RECT 5.060 895.575 421.430 895.805 ;
      LAYER met1 ;
        RECT 421.430 895.575 724.315 895.805 ;
      LAYER met1 ;
        RECT 5.060 894.215 421.000 895.575 ;
      LAYER met1 ;
        RECT 421.000 894.215 724.315 895.575 ;
      LAYER met1 ;
        RECT 5.060 892.845 422.000 894.215 ;
      LAYER met1 ;
        RECT 422.000 892.845 724.315 894.215 ;
      LAYER met1 ;
        RECT 5.060 890.925 421.000 892.845 ;
      LAYER met1 ;
        RECT 421.000 890.925 724.315 892.845 ;
      LAYER met1 ;
        RECT 5.060 890.695 421.500 890.925 ;
      LAYER met1 ;
        RECT 421.500 890.695 724.315 890.925 ;
      LAYER met1 ;
        RECT 5.060 886.165 421.000 890.695 ;
      LAYER met1 ;
        RECT 421.000 886.165 724.315 890.695 ;
      LAYER met1 ;
        RECT 5.060 885.935 421.500 886.165 ;
      LAYER met1 ;
        RECT 421.500 885.935 724.315 886.165 ;
      LAYER met1 ;
        RECT 5.060 884.905 421.000 885.935 ;
      LAYER met1 ;
        RECT 421.000 884.905 724.315 885.935 ;
      LAYER met1 ;
        RECT 5.060 884.675 421.430 884.905 ;
      LAYER met1 ;
        RECT 421.430 884.675 724.315 884.905 ;
      LAYER met1 ;
        RECT 5.060 883.315 421.000 884.675 ;
      LAYER met1 ;
        RECT 421.000 883.315 724.315 884.675 ;
      LAYER met1 ;
        RECT 5.060 881.945 422.000 883.315 ;
      LAYER met1 ;
        RECT 422.000 881.945 724.315 883.315 ;
      LAYER met1 ;
        RECT 5.060 880.025 421.000 881.945 ;
      LAYER met1 ;
        RECT 421.000 880.025 724.315 881.945 ;
      LAYER met1 ;
        RECT 5.060 879.795 421.500 880.025 ;
      LAYER met1 ;
        RECT 421.500 879.795 724.315 880.025 ;
      LAYER met1 ;
        RECT 5.060 875.265 421.000 879.795 ;
      LAYER met1 ;
        RECT 421.000 875.265 724.315 879.795 ;
      LAYER met1 ;
        RECT 5.060 875.035 421.500 875.265 ;
      LAYER met1 ;
        RECT 421.500 875.035 724.315 875.265 ;
      LAYER met1 ;
        RECT 5.060 874.005 421.000 875.035 ;
      LAYER met1 ;
        RECT 421.000 874.005 724.315 875.035 ;
      LAYER met1 ;
        RECT 5.060 873.775 421.430 874.005 ;
      LAYER met1 ;
        RECT 421.430 873.775 724.315 874.005 ;
      LAYER met1 ;
        RECT 5.060 872.415 421.000 873.775 ;
      LAYER met1 ;
        RECT 421.000 872.415 724.315 873.775 ;
      LAYER met1 ;
        RECT 5.060 871.045 422.000 872.415 ;
      LAYER met1 ;
        RECT 422.000 871.045 724.315 872.415 ;
      LAYER met1 ;
        RECT 5.060 869.125 421.000 871.045 ;
      LAYER met1 ;
        RECT 421.000 869.125 724.315 871.045 ;
      LAYER met1 ;
        RECT 5.060 868.895 421.500 869.125 ;
      LAYER met1 ;
        RECT 421.500 868.895 724.315 869.125 ;
      LAYER met1 ;
        RECT 5.060 864.365 421.000 868.895 ;
      LAYER met1 ;
        RECT 421.000 864.365 724.315 868.895 ;
      LAYER met1 ;
        RECT 5.060 864.135 421.500 864.365 ;
      LAYER met1 ;
        RECT 421.500 864.135 724.315 864.365 ;
      LAYER met1 ;
        RECT 5.060 863.105 421.000 864.135 ;
      LAYER met1 ;
        RECT 421.000 863.105 724.315 864.135 ;
      LAYER met1 ;
        RECT 5.060 862.875 421.430 863.105 ;
      LAYER met1 ;
        RECT 421.430 862.875 724.315 863.105 ;
      LAYER met1 ;
        RECT 5.060 861.515 421.000 862.875 ;
      LAYER met1 ;
        RECT 421.000 861.515 724.315 862.875 ;
      LAYER met1 ;
        RECT 5.060 860.145 422.000 861.515 ;
      LAYER met1 ;
        RECT 422.000 860.145 724.315 861.515 ;
      LAYER met1 ;
        RECT 5.060 858.225 421.000 860.145 ;
      LAYER met1 ;
        RECT 421.000 858.225 724.315 860.145 ;
      LAYER met1 ;
        RECT 5.060 857.995 421.500 858.225 ;
      LAYER met1 ;
        RECT 421.500 857.995 724.315 858.225 ;
      LAYER met1 ;
        RECT 5.060 853.465 421.000 857.995 ;
      LAYER met1 ;
        RECT 421.000 856.110 724.315 857.995 ;
        RECT 421.000 853.870 724.035 856.110 ;
      LAYER met1 ;
        RECT 724.035 853.870 724.315 856.110 ;
      LAYER met1 ;
        RECT 421.000 853.465 724.315 853.870 ;
      LAYER met1 ;
        RECT 5.060 853.235 421.500 853.465 ;
      LAYER met1 ;
        RECT 421.500 853.235 724.315 853.465 ;
      LAYER met1 ;
        RECT 5.060 852.205 421.000 853.235 ;
      LAYER met1 ;
        RECT 421.000 852.205 724.315 853.235 ;
      LAYER met1 ;
        RECT 5.060 851.975 421.430 852.205 ;
      LAYER met1 ;
        RECT 421.430 851.975 724.315 852.205 ;
      LAYER met1 ;
        RECT 5.060 850.615 421.000 851.975 ;
      LAYER met1 ;
        RECT 421.000 850.615 724.315 851.975 ;
      LAYER met1 ;
        RECT 5.060 849.245 422.000 850.615 ;
      LAYER met1 ;
        RECT 422.000 849.245 724.315 850.615 ;
      LAYER met1 ;
        RECT 5.060 847.325 421.000 849.245 ;
      LAYER met1 ;
        RECT 421.000 847.325 724.315 849.245 ;
      LAYER met1 ;
        RECT 5.060 847.095 421.500 847.325 ;
      LAYER met1 ;
        RECT 421.500 847.095 724.315 847.325 ;
      LAYER met1 ;
        RECT 5.060 840.500 421.000 847.095 ;
      LAYER met1 ;
        RECT 421.000 846.080 724.315 847.095 ;
        RECT 421.000 845.580 723.980 846.080 ;
      LAYER met1 ;
        RECT 723.980 845.580 724.315 846.080 ;
      LAYER met1 ;
        RECT 421.000 843.335 724.315 845.580 ;
        RECT 421.000 841.640 724.035 843.335 ;
      LAYER met1 ;
        RECT 724.035 841.640 724.315 843.335 ;
      LAYER met1 ;
        RECT 421.000 840.500 724.315 841.640 ;
      LAYER met1 ;
        RECT 5.060 828.870 680.000 840.500 ;
        RECT 5.060 822.275 421.000 828.870 ;
      LAYER met1 ;
        RECT 421.000 827.730 724.315 828.870 ;
        RECT 421.000 826.035 724.035 827.730 ;
      LAYER met1 ;
        RECT 724.035 826.035 724.315 827.730 ;
      LAYER met1 ;
        RECT 421.000 823.790 724.315 826.035 ;
        RECT 421.000 823.290 723.980 823.790 ;
      LAYER met1 ;
        RECT 723.980 823.290 724.315 823.790 ;
      LAYER met1 ;
        RECT 421.000 822.275 724.315 823.290 ;
      LAYER met1 ;
        RECT 5.060 822.045 421.500 822.275 ;
      LAYER met1 ;
        RECT 421.500 822.045 724.315 822.275 ;
      LAYER met1 ;
        RECT 5.060 820.125 421.000 822.045 ;
      LAYER met1 ;
        RECT 421.000 820.125 724.315 822.045 ;
      LAYER met1 ;
        RECT 5.060 818.755 422.000 820.125 ;
      LAYER met1 ;
        RECT 422.000 818.755 724.315 820.125 ;
      LAYER met1 ;
        RECT 5.060 817.395 421.000 818.755 ;
      LAYER met1 ;
        RECT 421.000 817.395 724.315 818.755 ;
      LAYER met1 ;
        RECT 5.060 817.165 421.430 817.395 ;
      LAYER met1 ;
        RECT 421.430 817.165 724.315 817.395 ;
      LAYER met1 ;
        RECT 5.060 816.135 421.000 817.165 ;
      LAYER met1 ;
        RECT 421.000 816.135 724.315 817.165 ;
      LAYER met1 ;
        RECT 5.060 815.905 421.500 816.135 ;
      LAYER met1 ;
        RECT 421.500 815.905 724.315 816.135 ;
      LAYER met1 ;
        RECT 5.060 811.375 421.000 815.905 ;
      LAYER met1 ;
        RECT 421.000 815.500 724.315 815.905 ;
        RECT 421.000 813.260 724.035 815.500 ;
      LAYER met1 ;
        RECT 724.035 813.260 724.315 815.500 ;
      LAYER met1 ;
        RECT 421.000 811.375 724.315 813.260 ;
      LAYER met1 ;
        RECT 5.060 811.145 421.500 811.375 ;
      LAYER met1 ;
        RECT 421.500 811.145 724.315 811.375 ;
      LAYER met1 ;
        RECT 5.060 809.225 421.000 811.145 ;
      LAYER met1 ;
        RECT 421.000 809.225 724.315 811.145 ;
      LAYER met1 ;
        RECT 5.060 807.855 422.000 809.225 ;
      LAYER met1 ;
        RECT 422.000 807.855 724.315 809.225 ;
      LAYER met1 ;
        RECT 5.060 806.495 421.000 807.855 ;
      LAYER met1 ;
        RECT 421.000 806.495 724.315 807.855 ;
      LAYER met1 ;
        RECT 5.060 806.265 421.430 806.495 ;
      LAYER met1 ;
        RECT 421.430 806.265 724.315 806.495 ;
      LAYER met1 ;
        RECT 5.060 805.235 421.000 806.265 ;
      LAYER met1 ;
        RECT 421.000 805.235 724.315 806.265 ;
      LAYER met1 ;
        RECT 5.060 805.005 421.500 805.235 ;
      LAYER met1 ;
        RECT 421.500 805.005 724.315 805.235 ;
      LAYER met1 ;
        RECT 5.060 800.475 421.000 805.005 ;
      LAYER met1 ;
        RECT 421.000 800.475 724.315 805.005 ;
      LAYER met1 ;
        RECT 5.060 800.245 421.500 800.475 ;
      LAYER met1 ;
        RECT 421.500 800.245 724.315 800.475 ;
      LAYER met1 ;
        RECT 5.060 798.325 421.000 800.245 ;
      LAYER met1 ;
        RECT 421.000 798.325 724.315 800.245 ;
      LAYER met1 ;
        RECT 5.060 796.955 422.000 798.325 ;
      LAYER met1 ;
        RECT 422.000 796.955 724.315 798.325 ;
      LAYER met1 ;
        RECT 5.060 795.595 421.000 796.955 ;
      LAYER met1 ;
        RECT 421.000 795.595 724.315 796.955 ;
      LAYER met1 ;
        RECT 5.060 795.365 421.430 795.595 ;
      LAYER met1 ;
        RECT 421.430 795.365 724.315 795.595 ;
      LAYER met1 ;
        RECT 5.060 794.335 421.000 795.365 ;
      LAYER met1 ;
        RECT 421.000 794.335 724.315 795.365 ;
      LAYER met1 ;
        RECT 5.060 794.105 421.500 794.335 ;
      LAYER met1 ;
        RECT 421.500 794.105 724.315 794.335 ;
      LAYER met1 ;
        RECT 5.060 789.575 421.000 794.105 ;
      LAYER met1 ;
        RECT 421.000 789.575 724.315 794.105 ;
      LAYER met1 ;
        RECT 5.060 789.345 421.500 789.575 ;
      LAYER met1 ;
        RECT 421.500 789.345 724.315 789.575 ;
      LAYER met1 ;
        RECT 5.060 787.425 421.000 789.345 ;
      LAYER met1 ;
        RECT 421.000 787.425 724.315 789.345 ;
      LAYER met1 ;
        RECT 5.060 786.055 422.000 787.425 ;
      LAYER met1 ;
        RECT 422.000 786.055 724.315 787.425 ;
      LAYER met1 ;
        RECT 5.060 784.695 421.000 786.055 ;
      LAYER met1 ;
        RECT 421.000 784.695 724.315 786.055 ;
      LAYER met1 ;
        RECT 5.060 784.465 421.430 784.695 ;
      LAYER met1 ;
        RECT 421.430 784.465 724.315 784.695 ;
      LAYER met1 ;
        RECT 5.060 783.435 421.000 784.465 ;
      LAYER met1 ;
        RECT 421.000 783.435 724.315 784.465 ;
      LAYER met1 ;
        RECT 5.060 783.205 421.500 783.435 ;
      LAYER met1 ;
        RECT 421.500 783.205 724.315 783.435 ;
      LAYER met1 ;
        RECT 5.060 778.675 421.000 783.205 ;
      LAYER met1 ;
        RECT 421.000 778.675 724.315 783.205 ;
      LAYER met1 ;
        RECT 5.060 778.445 421.500 778.675 ;
      LAYER met1 ;
        RECT 421.500 778.445 724.315 778.675 ;
      LAYER met1 ;
        RECT 5.060 776.525 421.000 778.445 ;
      LAYER met1 ;
        RECT 421.000 776.525 724.315 778.445 ;
      LAYER met1 ;
        RECT 5.060 775.155 422.000 776.525 ;
      LAYER met1 ;
        RECT 422.000 775.155 724.315 776.525 ;
      LAYER met1 ;
        RECT 5.060 773.795 421.000 775.155 ;
      LAYER met1 ;
        RECT 421.000 773.795 724.315 775.155 ;
      LAYER met1 ;
        RECT 5.060 773.565 421.430 773.795 ;
      LAYER met1 ;
        RECT 421.430 773.565 724.315 773.795 ;
      LAYER met1 ;
        RECT 5.060 772.535 421.000 773.565 ;
      LAYER met1 ;
        RECT 421.000 772.535 724.315 773.565 ;
      LAYER met1 ;
        RECT 5.060 772.305 421.500 772.535 ;
      LAYER met1 ;
        RECT 421.500 772.305 724.315 772.535 ;
      LAYER met1 ;
        RECT 5.060 767.775 421.000 772.305 ;
      LAYER met1 ;
        RECT 421.000 767.775 724.315 772.305 ;
      LAYER met1 ;
        RECT 5.060 767.545 421.500 767.775 ;
      LAYER met1 ;
        RECT 421.500 767.545 724.315 767.775 ;
      LAYER met1 ;
        RECT 5.060 765.625 421.000 767.545 ;
      LAYER met1 ;
        RECT 421.000 765.625 724.315 767.545 ;
      LAYER met1 ;
        RECT 5.060 764.255 422.000 765.625 ;
      LAYER met1 ;
        RECT 422.000 764.255 724.315 765.625 ;
      LAYER met1 ;
        RECT 5.060 762.895 421.000 764.255 ;
      LAYER met1 ;
        RECT 421.000 762.895 724.315 764.255 ;
      LAYER met1 ;
        RECT 5.060 762.665 421.430 762.895 ;
      LAYER met1 ;
        RECT 421.430 762.665 724.315 762.895 ;
      LAYER met1 ;
        RECT 5.060 761.635 421.000 762.665 ;
      LAYER met1 ;
        RECT 421.000 761.635 724.315 762.665 ;
      LAYER met1 ;
        RECT 5.060 761.405 421.500 761.635 ;
      LAYER met1 ;
        RECT 421.500 761.405 724.315 761.635 ;
      LAYER met1 ;
        RECT 5.060 756.875 421.000 761.405 ;
      LAYER met1 ;
        RECT 421.000 756.875 724.315 761.405 ;
      LAYER met1 ;
        RECT 5.060 756.645 421.500 756.875 ;
      LAYER met1 ;
        RECT 421.500 756.645 724.315 756.875 ;
      LAYER met1 ;
        RECT 5.060 754.725 421.000 756.645 ;
      LAYER met1 ;
        RECT 421.000 754.725 724.315 756.645 ;
      LAYER met1 ;
        RECT 5.060 753.355 422.000 754.725 ;
      LAYER met1 ;
        RECT 422.000 753.355 724.315 754.725 ;
      LAYER met1 ;
        RECT 5.060 751.995 421.000 753.355 ;
      LAYER met1 ;
        RECT 421.000 751.995 724.315 753.355 ;
      LAYER met1 ;
        RECT 5.060 751.765 421.430 751.995 ;
      LAYER met1 ;
        RECT 421.430 751.765 724.315 751.995 ;
      LAYER met1 ;
        RECT 5.060 750.735 421.000 751.765 ;
      LAYER met1 ;
        RECT 421.000 750.735 724.315 751.765 ;
      LAYER met1 ;
        RECT 5.060 750.505 421.500 750.735 ;
      LAYER met1 ;
        RECT 421.500 750.505 724.315 750.735 ;
      LAYER met1 ;
        RECT 5.060 745.975 421.000 750.505 ;
      LAYER met1 ;
        RECT 421.000 745.975 724.315 750.505 ;
      LAYER met1 ;
        RECT 5.060 745.745 421.500 745.975 ;
      LAYER met1 ;
        RECT 421.500 745.745 724.315 745.975 ;
      LAYER met1 ;
        RECT 5.060 743.825 421.000 745.745 ;
      LAYER met1 ;
        RECT 421.000 743.825 724.315 745.745 ;
      LAYER met1 ;
        RECT 5.060 742.455 422.000 743.825 ;
      LAYER met1 ;
        RECT 422.000 742.455 724.315 743.825 ;
      LAYER met1 ;
        RECT 5.060 741.095 421.000 742.455 ;
      LAYER met1 ;
        RECT 421.000 741.095 724.315 742.455 ;
      LAYER met1 ;
        RECT 5.060 740.865 421.430 741.095 ;
      LAYER met1 ;
        RECT 421.430 740.865 724.315 741.095 ;
      LAYER met1 ;
        RECT 5.060 739.835 421.000 740.865 ;
      LAYER met1 ;
        RECT 421.000 739.835 724.315 740.865 ;
      LAYER met1 ;
        RECT 5.060 739.605 421.500 739.835 ;
      LAYER met1 ;
        RECT 421.500 739.605 724.315 739.835 ;
      LAYER met1 ;
        RECT 5.060 735.075 421.000 739.605 ;
      LAYER met1 ;
        RECT 421.000 735.075 724.315 739.605 ;
      LAYER met1 ;
        RECT 5.060 734.845 421.500 735.075 ;
      LAYER met1 ;
        RECT 421.500 734.845 724.315 735.075 ;
      LAYER met1 ;
        RECT 5.060 732.925 421.000 734.845 ;
      LAYER met1 ;
        RECT 421.000 732.925 724.315 734.845 ;
      LAYER met1 ;
        RECT 5.060 731.555 422.000 732.925 ;
      LAYER met1 ;
        RECT 422.000 731.555 724.315 732.925 ;
      LAYER met1 ;
        RECT 5.060 730.195 421.000 731.555 ;
      LAYER met1 ;
        RECT 421.000 730.195 724.315 731.555 ;
      LAYER met1 ;
        RECT 5.060 729.965 421.430 730.195 ;
      LAYER met1 ;
        RECT 421.430 729.965 724.315 730.195 ;
      LAYER met1 ;
        RECT 5.060 728.935 421.000 729.965 ;
      LAYER met1 ;
        RECT 421.000 728.935 724.315 729.965 ;
      LAYER met1 ;
        RECT 5.060 728.705 421.500 728.935 ;
      LAYER met1 ;
        RECT 421.500 728.705 724.315 728.935 ;
      LAYER met1 ;
        RECT 5.060 724.175 421.000 728.705 ;
      LAYER met1 ;
        RECT 421.000 724.175 724.315 728.705 ;
      LAYER met1 ;
        RECT 5.060 723.945 421.500 724.175 ;
      LAYER met1 ;
        RECT 421.500 723.945 724.315 724.175 ;
      LAYER met1 ;
        RECT 5.060 722.025 421.000 723.945 ;
      LAYER met1 ;
        RECT 421.000 722.025 724.315 723.945 ;
      LAYER met1 ;
        RECT 5.060 720.655 422.000 722.025 ;
      LAYER met1 ;
        RECT 422.000 720.655 724.315 722.025 ;
      LAYER met1 ;
        RECT 5.060 719.295 421.000 720.655 ;
      LAYER met1 ;
        RECT 421.000 719.295 724.315 720.655 ;
      LAYER met1 ;
        RECT 5.060 719.065 421.430 719.295 ;
      LAYER met1 ;
        RECT 421.430 719.065 724.315 719.295 ;
      LAYER met1 ;
        RECT 5.060 718.035 421.000 719.065 ;
      LAYER met1 ;
        RECT 421.000 718.035 724.315 719.065 ;
      LAYER met1 ;
        RECT 5.060 717.805 421.500 718.035 ;
      LAYER met1 ;
        RECT 421.500 717.805 724.315 718.035 ;
      LAYER met1 ;
        RECT 5.060 713.275 421.000 717.805 ;
      LAYER met1 ;
        RECT 421.000 713.275 724.315 717.805 ;
      LAYER met1 ;
        RECT 5.060 713.045 421.500 713.275 ;
      LAYER met1 ;
        RECT 421.500 713.045 724.315 713.275 ;
      LAYER met1 ;
        RECT 5.060 711.125 421.000 713.045 ;
      LAYER met1 ;
        RECT 421.000 711.125 724.315 713.045 ;
      LAYER met1 ;
        RECT 5.060 709.755 422.000 711.125 ;
      LAYER met1 ;
        RECT 422.000 709.755 724.315 711.125 ;
      LAYER met1 ;
        RECT 5.060 708.395 421.000 709.755 ;
      LAYER met1 ;
        RECT 421.000 708.395 724.315 709.755 ;
      LAYER met1 ;
        RECT 5.060 708.165 421.430 708.395 ;
      LAYER met1 ;
        RECT 421.430 708.165 724.315 708.395 ;
      LAYER met1 ;
        RECT 5.060 707.135 421.000 708.165 ;
      LAYER met1 ;
        RECT 421.000 707.135 724.315 708.165 ;
      LAYER met1 ;
        RECT 5.060 706.905 421.500 707.135 ;
      LAYER met1 ;
        RECT 421.500 706.905 724.315 707.135 ;
      LAYER met1 ;
        RECT 5.060 702.375 421.000 706.905 ;
      LAYER met1 ;
        RECT 421.000 702.375 724.315 706.905 ;
      LAYER met1 ;
        RECT 5.060 702.145 421.500 702.375 ;
      LAYER met1 ;
        RECT 421.500 702.145 724.315 702.375 ;
      LAYER met1 ;
        RECT 5.060 700.225 421.000 702.145 ;
      LAYER met1 ;
        RECT 421.000 700.225 724.315 702.145 ;
      LAYER met1 ;
        RECT 5.060 698.855 422.000 700.225 ;
      LAYER met1 ;
        RECT 422.000 698.855 724.315 700.225 ;
      LAYER met1 ;
        RECT 5.060 697.495 421.000 698.855 ;
      LAYER met1 ;
        RECT 421.000 697.495 724.315 698.855 ;
      LAYER met1 ;
        RECT 5.060 697.265 421.430 697.495 ;
      LAYER met1 ;
        RECT 421.430 697.265 724.315 697.495 ;
      LAYER met1 ;
        RECT 5.060 696.235 421.000 697.265 ;
      LAYER met1 ;
        RECT 421.000 696.235 724.315 697.265 ;
      LAYER met1 ;
        RECT 5.060 696.005 421.500 696.235 ;
      LAYER met1 ;
        RECT 421.500 696.005 724.315 696.235 ;
      LAYER met1 ;
        RECT 5.060 691.475 421.000 696.005 ;
      LAYER met1 ;
        RECT 421.000 691.475 724.315 696.005 ;
      LAYER met1 ;
        RECT 5.060 691.245 421.500 691.475 ;
      LAYER met1 ;
        RECT 421.500 691.245 724.315 691.475 ;
      LAYER met1 ;
        RECT 5.060 689.325 421.000 691.245 ;
      LAYER met1 ;
        RECT 421.000 689.325 724.315 691.245 ;
      LAYER met1 ;
        RECT 5.060 687.955 422.000 689.325 ;
      LAYER met1 ;
        RECT 422.000 687.955 724.315 689.325 ;
      LAYER met1 ;
        RECT 5.060 686.595 421.000 687.955 ;
      LAYER met1 ;
        RECT 421.000 686.595 724.315 687.955 ;
      LAYER met1 ;
        RECT 5.060 686.365 421.430 686.595 ;
      LAYER met1 ;
        RECT 421.430 686.365 724.315 686.595 ;
      LAYER met1 ;
        RECT 5.060 685.335 421.000 686.365 ;
      LAYER met1 ;
        RECT 421.000 685.335 724.315 686.365 ;
      LAYER met1 ;
        RECT 5.060 685.105 421.500 685.335 ;
      LAYER met1 ;
        RECT 421.500 685.105 724.315 685.335 ;
      LAYER met1 ;
        RECT 5.060 680.575 421.000 685.105 ;
      LAYER met1 ;
        RECT 421.000 680.575 724.315 685.105 ;
      LAYER met1 ;
        RECT 5.060 680.345 421.500 680.575 ;
      LAYER met1 ;
        RECT 421.500 680.345 724.315 680.575 ;
      LAYER met1 ;
        RECT 5.060 678.425 421.000 680.345 ;
      LAYER met1 ;
        RECT 421.000 678.425 724.315 680.345 ;
      LAYER met1 ;
        RECT 5.060 677.055 422.000 678.425 ;
      LAYER met1 ;
        RECT 422.000 677.055 724.315 678.425 ;
      LAYER met1 ;
        RECT 5.060 675.695 421.000 677.055 ;
      LAYER met1 ;
        RECT 421.000 675.695 724.315 677.055 ;
      LAYER met1 ;
        RECT 5.060 675.465 421.430 675.695 ;
      LAYER met1 ;
        RECT 421.430 675.465 724.315 675.695 ;
      LAYER met1 ;
        RECT 5.060 674.435 421.000 675.465 ;
      LAYER met1 ;
        RECT 421.000 674.435 724.315 675.465 ;
      LAYER met1 ;
        RECT 5.060 674.205 421.500 674.435 ;
      LAYER met1 ;
        RECT 421.500 674.205 724.315 674.435 ;
      LAYER met1 ;
        RECT 5.060 669.675 421.000 674.205 ;
      LAYER met1 ;
        RECT 421.000 669.675 724.315 674.205 ;
      LAYER met1 ;
        RECT 5.060 669.445 421.500 669.675 ;
      LAYER met1 ;
        RECT 421.500 669.445 724.315 669.675 ;
      LAYER met1 ;
        RECT 5.060 667.525 421.000 669.445 ;
      LAYER met1 ;
        RECT 421.000 667.525 724.315 669.445 ;
      LAYER met1 ;
        RECT 5.060 666.155 422.000 667.525 ;
      LAYER met1 ;
        RECT 422.000 666.155 724.315 667.525 ;
      LAYER met1 ;
        RECT 5.060 664.795 421.000 666.155 ;
      LAYER met1 ;
        RECT 421.000 664.795 724.315 666.155 ;
      LAYER met1 ;
        RECT 5.060 664.565 421.430 664.795 ;
      LAYER met1 ;
        RECT 421.430 664.565 724.315 664.795 ;
      LAYER met1 ;
        RECT 5.060 663.535 421.000 664.565 ;
      LAYER met1 ;
        RECT 421.000 663.535 724.315 664.565 ;
      LAYER met1 ;
        RECT 5.060 663.305 421.500 663.535 ;
      LAYER met1 ;
        RECT 421.500 663.305 724.315 663.535 ;
      LAYER met1 ;
        RECT 5.060 658.775 421.000 663.305 ;
      LAYER met1 ;
        RECT 421.000 658.775 724.315 663.305 ;
      LAYER met1 ;
        RECT 5.060 658.545 421.500 658.775 ;
      LAYER met1 ;
        RECT 421.500 658.545 724.315 658.775 ;
      LAYER met1 ;
        RECT 5.060 656.955 421.000 658.545 ;
      LAYER met1 ;
        RECT 421.000 656.955 724.315 658.545 ;
      LAYER met1 ;
        RECT 5.060 656.765 422.015 656.955 ;
      LAYER met1 ;
        RECT 422.015 656.765 724.315 656.955 ;
      LAYER met1 ;
        RECT 5.060 656.625 421.000 656.765 ;
      LAYER met1 ;
        RECT 421.000 656.625 724.315 656.765 ;
      LAYER met1 ;
        RECT 5.060 655.255 422.000 656.625 ;
      LAYER met1 ;
        RECT 422.000 655.255 724.315 656.625 ;
      LAYER met1 ;
        RECT 5.060 653.895 421.000 655.255 ;
      LAYER met1 ;
        RECT 421.000 653.895 724.315 655.255 ;
      LAYER met1 ;
        RECT 5.060 653.665 421.430 653.895 ;
      LAYER met1 ;
        RECT 421.430 653.665 724.315 653.895 ;
      LAYER met1 ;
        RECT 5.060 652.635 421.000 653.665 ;
      LAYER met1 ;
        RECT 421.000 652.635 724.315 653.665 ;
      LAYER met1 ;
        RECT 5.060 652.405 421.500 652.635 ;
      LAYER met1 ;
        RECT 421.500 652.405 724.315 652.635 ;
      LAYER met1 ;
        RECT 5.060 650.730 421.000 652.405 ;
      LAYER met1 ;
        RECT 421.000 650.730 724.315 652.405 ;
      LAYER met1 ;
        RECT 5.060 650.470 421.630 650.730 ;
      LAYER met1 ;
        RECT 421.630 650.470 724.315 650.730 ;
      LAYER met1 ;
        RECT 5.060 649.805 421.000 650.470 ;
      LAYER met1 ;
        RECT 421.000 649.805 724.315 650.470 ;
      LAYER met1 ;
        RECT 5.060 649.545 421.620 649.805 ;
      LAYER met1 ;
        RECT 421.620 649.545 724.315 649.805 ;
      LAYER met1 ;
        RECT 5.060 646.665 421.000 649.545 ;
      LAYER met1 ;
        RECT 421.000 646.665 724.315 649.545 ;
      LAYER met1 ;
        RECT 5.060 646.405 421.605 646.665 ;
      LAYER met1 ;
        RECT 421.605 646.405 724.315 646.665 ;
      LAYER met1 ;
        RECT 5.060 646.265 421.000 646.405 ;
      LAYER met1 ;
        RECT 421.000 646.265 724.315 646.405 ;
      LAYER met1 ;
        RECT 5.060 646.005 421.610 646.265 ;
      LAYER met1 ;
        RECT 421.610 646.005 724.315 646.265 ;
      LAYER met1 ;
        RECT 5.060 643.125 421.000 646.005 ;
      LAYER met1 ;
        RECT 421.000 643.125 724.315 646.005 ;
      LAYER met1 ;
        RECT 5.060 642.865 421.550 643.125 ;
      LAYER met1 ;
        RECT 421.550 642.865 724.315 643.125 ;
      LAYER met1 ;
        RECT 5.060 642.725 421.000 642.865 ;
      LAYER met1 ;
        RECT 421.000 642.725 724.315 642.865 ;
      LAYER met1 ;
        RECT 5.060 642.465 421.535 642.725 ;
      LAYER met1 ;
        RECT 421.535 642.465 724.315 642.725 ;
      LAYER met1 ;
        RECT 5.060 639.585 421.000 642.465 ;
      LAYER met1 ;
        RECT 421.000 639.585 724.315 642.465 ;
      LAYER met1 ;
        RECT 5.060 639.325 421.590 639.585 ;
      LAYER met1 ;
        RECT 421.590 639.325 724.315 639.585 ;
      LAYER met1 ;
        RECT 5.060 639.185 421.000 639.325 ;
      LAYER met1 ;
        RECT 421.000 639.185 724.315 639.325 ;
      LAYER met1 ;
        RECT 5.060 638.925 421.575 639.185 ;
      LAYER met1 ;
        RECT 421.575 638.925 724.315 639.185 ;
      LAYER met1 ;
        RECT 5.060 632.505 421.000 638.925 ;
      LAYER met1 ;
        RECT 421.000 635.065 724.315 638.925 ;
        RECT 421.000 634.805 724.055 635.065 ;
      LAYER met1 ;
        RECT 724.055 634.805 724.775 635.065 ;
      LAYER met1 ;
        RECT 421.000 632.505 724.315 634.805 ;
      LAYER met1 ;
        RECT 5.060 632.245 421.510 632.505 ;
      LAYER met1 ;
        RECT 421.510 632.245 724.315 632.505 ;
      LAYER met1 ;
        RECT 5.060 632.105 421.000 632.245 ;
      LAYER met1 ;
        RECT 421.000 632.105 724.315 632.245 ;
      LAYER met1 ;
        RECT 5.060 631.845 421.510 632.105 ;
      LAYER met1 ;
        RECT 421.510 631.845 724.315 632.105 ;
      LAYER met1 ;
        RECT 5.060 628.965 421.000 631.845 ;
      LAYER met1 ;
        RECT 421.000 628.965 724.315 631.845 ;
      LAYER met1 ;
        RECT 5.060 628.705 421.510 628.965 ;
      LAYER met1 ;
        RECT 421.510 628.705 724.315 628.965 ;
      LAYER met1 ;
        RECT 5.060 628.565 421.000 628.705 ;
      LAYER met1 ;
        RECT 421.000 628.565 724.315 628.705 ;
      LAYER met1 ;
        RECT 5.060 628.305 421.505 628.565 ;
      LAYER met1 ;
        RECT 421.505 628.305 724.315 628.565 ;
      LAYER met1 ;
        RECT 5.060 625.420 421.000 628.305 ;
      LAYER met1 ;
        RECT 421.000 625.420 724.315 628.305 ;
      LAYER met1 ;
        RECT 5.060 625.165 421.675 625.420 ;
      LAYER met1 ;
        RECT 421.675 625.165 724.315 625.420 ;
      LAYER met1 ;
        RECT 5.060 625.025 421.000 625.165 ;
      LAYER met1 ;
        RECT 421.000 625.025 724.315 625.165 ;
      LAYER met1 ;
        RECT 5.060 624.765 421.665 625.025 ;
      LAYER met1 ;
        RECT 421.665 624.765 724.315 625.025 ;
      LAYER met1 ;
        RECT 5.060 620.685 421.000 624.765 ;
      LAYER met1 ;
        RECT 421.000 620.685 724.315 624.765 ;
      LAYER met1 ;
        RECT 5.060 620.485 421.865 620.685 ;
      LAYER met1 ;
        RECT 421.865 620.485 724.315 620.685 ;
      LAYER met1 ;
        RECT 5.060 620.345 421.000 620.485 ;
      LAYER met1 ;
        RECT 421.000 620.345 724.315 620.485 ;
      LAYER met1 ;
        RECT 5.060 620.145 421.880 620.345 ;
      LAYER met1 ;
        RECT 421.880 620.145 724.315 620.345 ;
      LAYER met1 ;
        RECT 5.060 618.985 421.000 620.145 ;
      LAYER met1 ;
        RECT 421.000 618.985 724.315 620.145 ;
      LAYER met1 ;
        RECT 5.060 618.795 421.785 618.985 ;
      LAYER met1 ;
        RECT 421.785 618.795 724.315 618.985 ;
      LAYER met1 ;
        RECT 5.060 617.465 421.000 618.795 ;
      LAYER met1 ;
        RECT 421.000 617.465 724.315 618.795 ;
      LAYER met1 ;
        RECT 5.060 617.235 421.500 617.465 ;
      LAYER met1 ;
        RECT 421.500 617.235 724.315 617.465 ;
      LAYER met1 ;
        RECT 5.060 616.205 421.000 617.235 ;
      LAYER met1 ;
        RECT 421.000 616.205 724.315 617.235 ;
      LAYER met1 ;
        RECT 5.060 615.975 421.430 616.205 ;
      LAYER met1 ;
        RECT 421.430 615.975 724.315 616.205 ;
      LAYER met1 ;
        RECT 5.060 614.615 421.000 615.975 ;
      LAYER met1 ;
        RECT 421.000 614.615 724.315 615.975 ;
      LAYER met1 ;
        RECT 5.060 613.245 422.000 614.615 ;
      LAYER met1 ;
        RECT 422.000 613.245 724.315 614.615 ;
      LAYER met1 ;
        RECT 5.060 611.325 421.000 613.245 ;
      LAYER met1 ;
        RECT 421.000 611.325 724.315 613.245 ;
      LAYER met1 ;
        RECT 5.060 611.095 421.500 611.325 ;
      LAYER met1 ;
        RECT 421.500 611.095 724.315 611.325 ;
      LAYER met1 ;
        RECT 5.060 608.525 421.000 611.095 ;
      LAYER met1 ;
        RECT 421.000 608.525 724.315 611.095 ;
      LAYER met1 ;
        RECT 5.060 608.275 421.630 608.525 ;
      LAYER met1 ;
        RECT 421.630 608.275 724.315 608.525 ;
      LAYER met1 ;
        RECT 5.060 608.135 421.000 608.275 ;
      LAYER met1 ;
        RECT 421.000 608.135 724.315 608.275 ;
      LAYER met1 ;
        RECT 5.060 607.895 421.635 608.135 ;
      LAYER met1 ;
        RECT 421.635 607.895 724.315 608.135 ;
      LAYER met1 ;
        RECT 5.060 606.565 421.000 607.895 ;
      LAYER met1 ;
        RECT 421.000 606.565 724.315 607.895 ;
      LAYER met1 ;
        RECT 5.060 606.335 421.500 606.565 ;
      LAYER met1 ;
        RECT 421.500 606.335 724.315 606.565 ;
      LAYER met1 ;
        RECT 5.060 605.305 421.000 606.335 ;
      LAYER met1 ;
        RECT 421.000 605.305 724.315 606.335 ;
      LAYER met1 ;
        RECT 5.060 605.075 421.430 605.305 ;
      LAYER met1 ;
        RECT 421.430 605.075 724.315 605.305 ;
      LAYER met1 ;
        RECT 5.060 603.715 421.000 605.075 ;
      LAYER met1 ;
        RECT 421.000 603.715 724.315 605.075 ;
      LAYER met1 ;
        RECT 5.060 602.345 422.000 603.715 ;
      LAYER met1 ;
        RECT 422.000 602.345 724.315 603.715 ;
      LAYER met1 ;
        RECT 5.060 601.825 421.000 602.345 ;
      LAYER met1 ;
        RECT 421.000 601.825 724.315 602.345 ;
      LAYER met1 ;
        RECT 5.060 601.595 421.645 601.825 ;
      LAYER met1 ;
        RECT 421.645 601.595 724.315 601.825 ;
      LAYER met1 ;
        RECT 5.060 600.425 421.000 601.595 ;
      LAYER met1 ;
        RECT 421.000 600.425 724.315 601.595 ;
      LAYER met1 ;
        RECT 5.060 600.195 421.500 600.425 ;
      LAYER met1 ;
        RECT 421.500 600.195 724.315 600.425 ;
      LAYER met1 ;
        RECT 5.060 595.665 421.000 600.195 ;
      LAYER met1 ;
        RECT 421.000 595.665 724.315 600.195 ;
      LAYER met1 ;
        RECT 5.060 595.435 421.500 595.665 ;
      LAYER met1 ;
        RECT 421.500 595.435 724.315 595.665 ;
      LAYER met1 ;
        RECT 5.060 594.405 421.000 595.435 ;
      LAYER met1 ;
        RECT 421.000 594.405 724.315 595.435 ;
      LAYER met1 ;
        RECT 5.060 594.175 421.430 594.405 ;
      LAYER met1 ;
        RECT 421.430 594.175 724.315 594.405 ;
      LAYER met1 ;
        RECT 5.060 592.815 421.000 594.175 ;
      LAYER met1 ;
        RECT 421.000 592.815 724.315 594.175 ;
      LAYER met1 ;
        RECT 5.060 591.445 422.000 592.815 ;
      LAYER met1 ;
        RECT 422.000 591.445 724.315 592.815 ;
      LAYER met1 ;
        RECT 5.060 589.525 421.000 591.445 ;
      LAYER met1 ;
        RECT 421.000 589.525 724.315 591.445 ;
      LAYER met1 ;
        RECT 5.060 589.295 421.500 589.525 ;
      LAYER met1 ;
        RECT 421.500 589.295 724.315 589.525 ;
      LAYER met1 ;
        RECT 5.060 584.765 421.000 589.295 ;
      LAYER met1 ;
        RECT 421.000 584.765 724.315 589.295 ;
      LAYER met1 ;
        RECT 5.060 584.535 421.500 584.765 ;
      LAYER met1 ;
        RECT 421.500 584.535 724.315 584.765 ;
      LAYER met1 ;
        RECT 5.060 583.505 421.000 584.535 ;
      LAYER met1 ;
        RECT 421.000 583.505 724.315 584.535 ;
      LAYER met1 ;
        RECT 5.060 583.275 421.430 583.505 ;
      LAYER met1 ;
        RECT 421.430 583.275 724.315 583.505 ;
      LAYER met1 ;
        RECT 5.060 581.915 421.000 583.275 ;
      LAYER met1 ;
        RECT 421.000 581.915 724.315 583.275 ;
      LAYER met1 ;
        RECT 5.060 580.545 422.000 581.915 ;
      LAYER met1 ;
        RECT 422.000 580.545 724.315 581.915 ;
      LAYER met1 ;
        RECT 5.060 578.625 421.000 580.545 ;
      LAYER met1 ;
        RECT 421.000 578.625 724.315 580.545 ;
      LAYER met1 ;
        RECT 5.060 578.395 421.500 578.625 ;
      LAYER met1 ;
        RECT 421.500 578.395 724.315 578.625 ;
      LAYER met1 ;
        RECT 5.060 573.865 421.000 578.395 ;
      LAYER met1 ;
        RECT 421.000 573.865 724.315 578.395 ;
      LAYER met1 ;
        RECT 5.060 573.635 421.500 573.865 ;
      LAYER met1 ;
        RECT 421.500 573.635 724.315 573.865 ;
      LAYER met1 ;
        RECT 5.060 572.605 421.000 573.635 ;
      LAYER met1 ;
        RECT 421.000 572.605 724.315 573.635 ;
      LAYER met1 ;
        RECT 5.060 572.375 421.430 572.605 ;
      LAYER met1 ;
        RECT 421.430 572.375 724.315 572.605 ;
      LAYER met1 ;
        RECT 5.060 571.015 421.000 572.375 ;
      LAYER met1 ;
        RECT 421.000 571.015 724.315 572.375 ;
      LAYER met1 ;
        RECT 5.060 569.645 422.000 571.015 ;
      LAYER met1 ;
        RECT 422.000 569.645 724.315 571.015 ;
      LAYER met1 ;
        RECT 5.060 567.725 421.000 569.645 ;
      LAYER met1 ;
        RECT 421.000 567.725 724.315 569.645 ;
      LAYER met1 ;
        RECT 5.060 567.495 421.500 567.725 ;
      LAYER met1 ;
        RECT 421.500 567.495 724.315 567.725 ;
      LAYER met1 ;
        RECT 5.060 562.965 421.000 567.495 ;
      LAYER met1 ;
        RECT 421.000 562.965 724.315 567.495 ;
      LAYER met1 ;
        RECT 5.060 562.735 421.500 562.965 ;
      LAYER met1 ;
        RECT 421.500 562.735 724.315 562.965 ;
      LAYER met1 ;
        RECT 5.060 561.705 421.000 562.735 ;
      LAYER met1 ;
        RECT 421.000 561.705 724.315 562.735 ;
      LAYER met1 ;
        RECT 5.060 561.475 421.430 561.705 ;
      LAYER met1 ;
        RECT 421.430 561.475 724.315 561.705 ;
      LAYER met1 ;
        RECT 5.060 560.115 421.000 561.475 ;
      LAYER met1 ;
        RECT 421.000 560.115 724.315 561.475 ;
      LAYER met1 ;
        RECT 5.060 558.745 422.000 560.115 ;
      LAYER met1 ;
        RECT 422.000 558.745 724.315 560.115 ;
      LAYER met1 ;
        RECT 5.060 556.825 421.000 558.745 ;
      LAYER met1 ;
        RECT 421.000 556.825 724.315 558.745 ;
      LAYER met1 ;
        RECT 5.060 556.595 421.500 556.825 ;
      LAYER met1 ;
        RECT 421.500 556.595 724.315 556.825 ;
      LAYER met1 ;
        RECT 5.060 552.065 421.000 556.595 ;
      LAYER met1 ;
        RECT 421.000 552.065 724.315 556.595 ;
      LAYER met1 ;
        RECT 5.060 551.835 421.500 552.065 ;
      LAYER met1 ;
        RECT 421.500 551.835 724.315 552.065 ;
      LAYER met1 ;
        RECT 5.060 550.805 421.000 551.835 ;
      LAYER met1 ;
        RECT 421.000 550.805 724.315 551.835 ;
      LAYER met1 ;
        RECT 5.060 550.575 421.430 550.805 ;
      LAYER met1 ;
        RECT 421.430 550.575 724.315 550.805 ;
      LAYER met1 ;
        RECT 5.060 549.215 421.000 550.575 ;
      LAYER met1 ;
        RECT 421.000 549.215 724.315 550.575 ;
      LAYER met1 ;
        RECT 5.060 547.845 422.000 549.215 ;
      LAYER met1 ;
        RECT 422.000 547.845 724.315 549.215 ;
      LAYER met1 ;
        RECT 5.060 545.925 421.000 547.845 ;
      LAYER met1 ;
        RECT 421.000 545.925 724.315 547.845 ;
      LAYER met1 ;
        RECT 5.060 545.695 421.500 545.925 ;
      LAYER met1 ;
        RECT 421.500 545.695 724.315 545.925 ;
      LAYER met1 ;
        RECT 5.060 541.165 421.000 545.695 ;
      LAYER met1 ;
        RECT 421.000 541.165 724.315 545.695 ;
      LAYER met1 ;
        RECT 5.060 540.935 421.500 541.165 ;
      LAYER met1 ;
        RECT 421.500 540.935 724.315 541.165 ;
      LAYER met1 ;
        RECT 5.060 539.905 421.000 540.935 ;
      LAYER met1 ;
        RECT 421.000 539.905 724.315 540.935 ;
      LAYER met1 ;
        RECT 5.060 539.675 421.430 539.905 ;
      LAYER met1 ;
        RECT 421.430 539.675 724.315 539.905 ;
      LAYER met1 ;
        RECT 5.060 538.315 421.000 539.675 ;
      LAYER met1 ;
        RECT 421.000 538.315 724.315 539.675 ;
      LAYER met1 ;
        RECT 5.060 536.945 422.000 538.315 ;
      LAYER met1 ;
        RECT 422.000 536.945 724.315 538.315 ;
      LAYER met1 ;
        RECT 5.060 535.025 421.000 536.945 ;
      LAYER met1 ;
        RECT 421.000 535.025 724.315 536.945 ;
      LAYER met1 ;
        RECT 5.060 534.795 421.500 535.025 ;
      LAYER met1 ;
        RECT 421.500 534.795 724.315 535.025 ;
      LAYER met1 ;
        RECT 5.060 530.265 421.000 534.795 ;
      LAYER met1 ;
        RECT 421.000 530.265 724.315 534.795 ;
      LAYER met1 ;
        RECT 5.060 530.035 421.500 530.265 ;
      LAYER met1 ;
        RECT 421.500 530.035 724.315 530.265 ;
      LAYER met1 ;
        RECT 5.060 529.005 421.000 530.035 ;
      LAYER met1 ;
        RECT 421.000 529.005 724.315 530.035 ;
      LAYER met1 ;
        RECT 5.060 528.775 421.430 529.005 ;
      LAYER met1 ;
        RECT 421.430 528.775 724.315 529.005 ;
      LAYER met1 ;
        RECT 5.060 527.415 421.000 528.775 ;
      LAYER met1 ;
        RECT 421.000 527.415 724.315 528.775 ;
      LAYER met1 ;
        RECT 5.060 526.045 422.000 527.415 ;
      LAYER met1 ;
        RECT 422.000 526.045 724.315 527.415 ;
      LAYER met1 ;
        RECT 5.060 524.125 421.000 526.045 ;
      LAYER met1 ;
        RECT 421.000 524.125 724.315 526.045 ;
      LAYER met1 ;
        RECT 5.060 523.895 421.500 524.125 ;
      LAYER met1 ;
        RECT 421.500 523.895 724.315 524.125 ;
      LAYER met1 ;
        RECT 5.060 519.365 421.000 523.895 ;
      LAYER met1 ;
        RECT 421.000 519.365 724.315 523.895 ;
      LAYER met1 ;
        RECT 5.060 519.135 421.500 519.365 ;
      LAYER met1 ;
        RECT 421.500 519.135 724.315 519.365 ;
      LAYER met1 ;
        RECT 5.060 518.105 421.000 519.135 ;
      LAYER met1 ;
        RECT 421.000 518.105 724.315 519.135 ;
      LAYER met1 ;
        RECT 5.060 517.875 421.430 518.105 ;
      LAYER met1 ;
        RECT 421.430 517.875 724.315 518.105 ;
      LAYER met1 ;
        RECT 5.060 516.515 421.000 517.875 ;
      LAYER met1 ;
        RECT 421.000 516.515 724.315 517.875 ;
      LAYER met1 ;
        RECT 5.060 515.145 422.000 516.515 ;
      LAYER met1 ;
        RECT 422.000 515.145 724.315 516.515 ;
      LAYER met1 ;
        RECT 5.060 513.225 421.000 515.145 ;
      LAYER met1 ;
        RECT 421.000 513.225 724.315 515.145 ;
      LAYER met1 ;
        RECT 5.060 512.995 421.500 513.225 ;
      LAYER met1 ;
        RECT 421.500 512.995 724.315 513.225 ;
      LAYER met1 ;
        RECT 5.060 508.465 421.000 512.995 ;
      LAYER met1 ;
        RECT 421.000 508.465 724.315 512.995 ;
      LAYER met1 ;
        RECT 5.060 508.235 421.500 508.465 ;
      LAYER met1 ;
        RECT 421.500 508.235 724.315 508.465 ;
      LAYER met1 ;
        RECT 5.060 507.205 421.000 508.235 ;
      LAYER met1 ;
        RECT 421.000 507.205 724.315 508.235 ;
      LAYER met1 ;
        RECT 5.060 506.975 421.430 507.205 ;
      LAYER met1 ;
        RECT 421.430 506.975 724.315 507.205 ;
      LAYER met1 ;
        RECT 5.060 505.615 421.000 506.975 ;
      LAYER met1 ;
        RECT 421.000 505.615 724.315 506.975 ;
      LAYER met1 ;
        RECT 5.060 504.245 422.000 505.615 ;
      LAYER met1 ;
        RECT 422.000 504.245 724.315 505.615 ;
      LAYER met1 ;
        RECT 5.060 502.325 421.000 504.245 ;
      LAYER met1 ;
        RECT 421.000 502.325 724.315 504.245 ;
      LAYER met1 ;
        RECT 5.060 502.095 421.500 502.325 ;
      LAYER met1 ;
        RECT 421.500 502.095 724.315 502.325 ;
      LAYER met1 ;
        RECT 5.060 497.565 421.000 502.095 ;
      LAYER met1 ;
        RECT 421.000 497.565 724.315 502.095 ;
      LAYER met1 ;
        RECT 5.060 497.335 421.500 497.565 ;
      LAYER met1 ;
        RECT 421.500 497.335 724.315 497.565 ;
      LAYER met1 ;
        RECT 5.060 496.305 421.000 497.335 ;
      LAYER met1 ;
        RECT 421.000 496.305 724.315 497.335 ;
      LAYER met1 ;
        RECT 5.060 496.075 421.430 496.305 ;
      LAYER met1 ;
        RECT 421.430 496.075 724.315 496.305 ;
      LAYER met1 ;
        RECT 5.060 494.715 421.000 496.075 ;
      LAYER met1 ;
        RECT 421.000 494.715 724.315 496.075 ;
      LAYER met1 ;
        RECT 5.060 493.345 422.000 494.715 ;
      LAYER met1 ;
        RECT 422.000 493.345 724.315 494.715 ;
      LAYER met1 ;
        RECT 5.060 491.425 421.000 493.345 ;
      LAYER met1 ;
        RECT 421.000 491.425 724.315 493.345 ;
      LAYER met1 ;
        RECT 5.060 491.195 421.500 491.425 ;
      LAYER met1 ;
        RECT 421.500 491.195 724.315 491.425 ;
      LAYER met1 ;
        RECT 5.060 486.665 421.000 491.195 ;
      LAYER met1 ;
        RECT 421.000 486.665 724.315 491.195 ;
      LAYER met1 ;
        RECT 5.060 486.435 421.500 486.665 ;
      LAYER met1 ;
        RECT 421.500 486.435 724.315 486.665 ;
      LAYER met1 ;
        RECT 5.060 485.405 421.000 486.435 ;
      LAYER met1 ;
        RECT 421.000 485.405 724.315 486.435 ;
      LAYER met1 ;
        RECT 5.060 485.175 421.430 485.405 ;
      LAYER met1 ;
        RECT 421.430 485.175 724.315 485.405 ;
      LAYER met1 ;
        RECT 5.060 483.815 421.000 485.175 ;
      LAYER met1 ;
        RECT 421.000 483.815 724.315 485.175 ;
      LAYER met1 ;
        RECT 5.060 482.445 422.000 483.815 ;
      LAYER met1 ;
        RECT 422.000 482.445 724.315 483.815 ;
      LAYER met1 ;
        RECT 5.060 480.525 421.000 482.445 ;
      LAYER met1 ;
        RECT 421.000 480.525 724.315 482.445 ;
      LAYER met1 ;
        RECT 5.060 480.295 421.500 480.525 ;
      LAYER met1 ;
        RECT 421.500 480.295 724.315 480.525 ;
      LAYER met1 ;
        RECT 5.060 475.765 421.000 480.295 ;
      LAYER met1 ;
        RECT 421.000 475.765 724.315 480.295 ;
      LAYER met1 ;
        RECT 5.060 475.535 421.500 475.765 ;
      LAYER met1 ;
        RECT 421.500 475.535 724.315 475.765 ;
      LAYER met1 ;
        RECT 5.060 474.505 421.000 475.535 ;
      LAYER met1 ;
        RECT 421.000 474.505 724.315 475.535 ;
      LAYER met1 ;
        RECT 5.060 474.275 421.430 474.505 ;
      LAYER met1 ;
        RECT 421.430 474.275 724.315 474.505 ;
      LAYER met1 ;
        RECT 5.060 472.915 421.000 474.275 ;
      LAYER met1 ;
        RECT 421.000 472.915 724.315 474.275 ;
      LAYER met1 ;
        RECT 5.060 471.545 422.000 472.915 ;
      LAYER met1 ;
        RECT 422.000 471.545 724.315 472.915 ;
      LAYER met1 ;
        RECT 5.060 469.625 421.000 471.545 ;
      LAYER met1 ;
        RECT 421.000 469.625 724.315 471.545 ;
      LAYER met1 ;
        RECT 5.060 469.395 421.500 469.625 ;
      LAYER met1 ;
        RECT 421.500 469.395 724.315 469.625 ;
      LAYER met1 ;
        RECT 5.060 464.865 421.000 469.395 ;
      LAYER met1 ;
        RECT 421.000 464.865 724.315 469.395 ;
      LAYER met1 ;
        RECT 5.060 464.635 421.500 464.865 ;
      LAYER met1 ;
        RECT 421.500 464.635 724.315 464.865 ;
      LAYER met1 ;
        RECT 5.060 463.605 421.000 464.635 ;
      LAYER met1 ;
        RECT 421.000 463.605 724.315 464.635 ;
      LAYER met1 ;
        RECT 5.060 463.375 421.430 463.605 ;
      LAYER met1 ;
        RECT 421.430 463.375 724.315 463.605 ;
      LAYER met1 ;
        RECT 5.060 462.015 421.000 463.375 ;
      LAYER met1 ;
        RECT 421.000 462.015 724.315 463.375 ;
      LAYER met1 ;
        RECT 5.060 460.645 422.000 462.015 ;
      LAYER met1 ;
        RECT 422.000 460.645 724.315 462.015 ;
      LAYER met1 ;
        RECT 5.060 458.725 421.000 460.645 ;
      LAYER met1 ;
        RECT 421.000 458.725 724.315 460.645 ;
      LAYER met1 ;
        RECT 5.060 458.495 421.500 458.725 ;
      LAYER met1 ;
        RECT 421.500 458.495 724.315 458.725 ;
      LAYER met1 ;
        RECT 5.060 453.965 421.000 458.495 ;
      LAYER met1 ;
        RECT 421.000 456.610 724.315 458.495 ;
        RECT 421.000 454.370 724.035 456.610 ;
      LAYER met1 ;
        RECT 724.035 454.370 724.315 456.610 ;
      LAYER met1 ;
        RECT 421.000 453.965 724.315 454.370 ;
      LAYER met1 ;
        RECT 5.060 453.735 421.500 453.965 ;
      LAYER met1 ;
        RECT 421.500 453.735 724.315 453.965 ;
      LAYER met1 ;
        RECT 5.060 452.705 421.000 453.735 ;
      LAYER met1 ;
        RECT 421.000 452.705 724.315 453.735 ;
      LAYER met1 ;
        RECT 5.060 452.475 421.430 452.705 ;
      LAYER met1 ;
        RECT 421.430 452.475 724.315 452.705 ;
      LAYER met1 ;
        RECT 5.060 451.115 421.000 452.475 ;
      LAYER met1 ;
        RECT 421.000 451.115 724.315 452.475 ;
      LAYER met1 ;
        RECT 5.060 449.745 422.000 451.115 ;
      LAYER met1 ;
        RECT 422.000 449.745 724.315 451.115 ;
      LAYER met1 ;
        RECT 5.060 447.825 421.000 449.745 ;
      LAYER met1 ;
        RECT 421.000 447.825 724.315 449.745 ;
      LAYER met1 ;
        RECT 5.060 447.595 421.500 447.825 ;
      LAYER met1 ;
        RECT 421.500 447.595 724.315 447.825 ;
      LAYER met1 ;
        RECT 5.060 441.000 421.000 447.595 ;
      LAYER met1 ;
        RECT 421.000 446.580 724.315 447.595 ;
        RECT 421.000 446.080 723.980 446.580 ;
      LAYER met1 ;
        RECT 723.980 446.080 724.315 446.580 ;
      LAYER met1 ;
        RECT 421.000 443.835 724.315 446.080 ;
        RECT 421.000 442.140 724.035 443.835 ;
      LAYER met1 ;
        RECT 724.035 442.140 724.315 443.835 ;
      LAYER met1 ;
        RECT 421.000 441.000 724.315 442.140 ;
      LAYER met1 ;
        RECT 5.060 427.870 680.000 441.000 ;
        RECT 5.060 421.275 421.000 427.870 ;
      LAYER met1 ;
        RECT 421.000 426.730 724.315 427.870 ;
        RECT 421.000 425.035 724.035 426.730 ;
      LAYER met1 ;
        RECT 724.035 425.035 724.315 426.730 ;
      LAYER met1 ;
        RECT 421.000 422.790 724.315 425.035 ;
        RECT 421.000 422.290 723.980 422.790 ;
      LAYER met1 ;
        RECT 723.980 422.290 724.315 422.790 ;
      LAYER met1 ;
        RECT 421.000 421.275 724.315 422.290 ;
      LAYER met1 ;
        RECT 5.060 421.045 421.500 421.275 ;
      LAYER met1 ;
        RECT 421.500 421.045 724.315 421.275 ;
      LAYER met1 ;
        RECT 5.060 419.125 421.000 421.045 ;
      LAYER met1 ;
        RECT 421.000 419.125 724.315 421.045 ;
      LAYER met1 ;
        RECT 5.060 417.755 422.000 419.125 ;
      LAYER met1 ;
        RECT 422.000 417.755 724.315 419.125 ;
      LAYER met1 ;
        RECT 5.060 416.395 421.000 417.755 ;
      LAYER met1 ;
        RECT 421.000 416.395 724.315 417.755 ;
      LAYER met1 ;
        RECT 5.060 416.165 421.430 416.395 ;
      LAYER met1 ;
        RECT 421.430 416.165 724.315 416.395 ;
      LAYER met1 ;
        RECT 5.060 415.135 421.000 416.165 ;
      LAYER met1 ;
        RECT 421.000 415.135 724.315 416.165 ;
      LAYER met1 ;
        RECT 5.060 414.905 421.500 415.135 ;
      LAYER met1 ;
        RECT 421.500 414.905 724.315 415.135 ;
      LAYER met1 ;
        RECT 5.060 410.375 421.000 414.905 ;
      LAYER met1 ;
        RECT 421.000 414.500 724.315 414.905 ;
        RECT 421.000 412.260 724.035 414.500 ;
      LAYER met1 ;
        RECT 724.035 412.260 724.315 414.500 ;
      LAYER met1 ;
        RECT 421.000 410.375 724.315 412.260 ;
      LAYER met1 ;
        RECT 5.060 410.145 421.500 410.375 ;
      LAYER met1 ;
        RECT 421.500 410.145 724.315 410.375 ;
      LAYER met1 ;
        RECT 5.060 408.225 421.000 410.145 ;
      LAYER met1 ;
        RECT 421.000 408.225 724.315 410.145 ;
      LAYER met1 ;
        RECT 5.060 406.855 422.000 408.225 ;
      LAYER met1 ;
        RECT 422.000 406.855 724.315 408.225 ;
      LAYER met1 ;
        RECT 5.060 405.495 421.000 406.855 ;
      LAYER met1 ;
        RECT 421.000 405.495 724.315 406.855 ;
      LAYER met1 ;
        RECT 5.060 405.265 421.430 405.495 ;
      LAYER met1 ;
        RECT 421.430 405.265 724.315 405.495 ;
      LAYER met1 ;
        RECT 5.060 404.235 421.000 405.265 ;
      LAYER met1 ;
        RECT 421.000 404.235 724.315 405.265 ;
      LAYER met1 ;
        RECT 5.060 404.005 421.500 404.235 ;
      LAYER met1 ;
        RECT 421.500 404.005 724.315 404.235 ;
      LAYER met1 ;
        RECT 5.060 399.475 421.000 404.005 ;
      LAYER met1 ;
        RECT 421.000 399.475 724.315 404.005 ;
      LAYER met1 ;
        RECT 5.060 399.245 421.500 399.475 ;
      LAYER met1 ;
        RECT 421.500 399.245 724.315 399.475 ;
      LAYER met1 ;
        RECT 5.060 397.325 421.000 399.245 ;
      LAYER met1 ;
        RECT 421.000 397.325 724.315 399.245 ;
      LAYER met1 ;
        RECT 5.060 395.955 422.000 397.325 ;
      LAYER met1 ;
        RECT 422.000 395.955 724.315 397.325 ;
      LAYER met1 ;
        RECT 5.060 394.595 421.000 395.955 ;
      LAYER met1 ;
        RECT 421.000 394.595 724.315 395.955 ;
      LAYER met1 ;
        RECT 5.060 394.365 421.430 394.595 ;
      LAYER met1 ;
        RECT 421.430 394.365 724.315 394.595 ;
      LAYER met1 ;
        RECT 5.060 393.335 421.000 394.365 ;
      LAYER met1 ;
        RECT 421.000 393.335 724.315 394.365 ;
      LAYER met1 ;
        RECT 5.060 393.105 421.500 393.335 ;
      LAYER met1 ;
        RECT 421.500 393.105 724.315 393.335 ;
      LAYER met1 ;
        RECT 5.060 388.575 421.000 393.105 ;
      LAYER met1 ;
        RECT 421.000 388.575 724.315 393.105 ;
      LAYER met1 ;
        RECT 5.060 388.345 421.500 388.575 ;
      LAYER met1 ;
        RECT 421.500 388.345 724.315 388.575 ;
      LAYER met1 ;
        RECT 5.060 386.425 421.000 388.345 ;
      LAYER met1 ;
        RECT 421.000 386.425 724.315 388.345 ;
      LAYER met1 ;
        RECT 5.060 385.055 422.000 386.425 ;
      LAYER met1 ;
        RECT 422.000 385.055 724.315 386.425 ;
      LAYER met1 ;
        RECT 5.060 383.695 421.000 385.055 ;
      LAYER met1 ;
        RECT 421.000 383.695 724.315 385.055 ;
      LAYER met1 ;
        RECT 5.060 383.465 421.430 383.695 ;
      LAYER met1 ;
        RECT 421.430 383.465 724.315 383.695 ;
      LAYER met1 ;
        RECT 5.060 382.435 421.000 383.465 ;
      LAYER met1 ;
        RECT 421.000 382.435 724.315 383.465 ;
      LAYER met1 ;
        RECT 5.060 382.205 421.500 382.435 ;
      LAYER met1 ;
        RECT 421.500 382.205 724.315 382.435 ;
      LAYER met1 ;
        RECT 5.060 377.675 421.000 382.205 ;
      LAYER met1 ;
        RECT 421.000 377.675 724.315 382.205 ;
      LAYER met1 ;
        RECT 5.060 377.445 421.500 377.675 ;
      LAYER met1 ;
        RECT 421.500 377.445 724.315 377.675 ;
      LAYER met1 ;
        RECT 5.060 375.525 421.000 377.445 ;
      LAYER met1 ;
        RECT 421.000 375.525 724.315 377.445 ;
      LAYER met1 ;
        RECT 5.060 374.155 422.000 375.525 ;
      LAYER met1 ;
        RECT 422.000 374.155 724.315 375.525 ;
      LAYER met1 ;
        RECT 5.060 372.795 421.000 374.155 ;
      LAYER met1 ;
        RECT 421.000 372.795 724.315 374.155 ;
      LAYER met1 ;
        RECT 5.060 372.565 421.430 372.795 ;
      LAYER met1 ;
        RECT 421.430 372.565 724.315 372.795 ;
      LAYER met1 ;
        RECT 5.060 371.535 421.000 372.565 ;
      LAYER met1 ;
        RECT 421.000 371.535 724.315 372.565 ;
      LAYER met1 ;
        RECT 5.060 371.305 421.500 371.535 ;
      LAYER met1 ;
        RECT 421.500 371.305 724.315 371.535 ;
      LAYER met1 ;
        RECT 5.060 366.775 421.000 371.305 ;
      LAYER met1 ;
        RECT 421.000 366.775 724.315 371.305 ;
      LAYER met1 ;
        RECT 5.060 366.545 421.500 366.775 ;
      LAYER met1 ;
        RECT 421.500 366.545 724.315 366.775 ;
      LAYER met1 ;
        RECT 5.060 364.625 421.000 366.545 ;
      LAYER met1 ;
        RECT 421.000 364.625 724.315 366.545 ;
      LAYER met1 ;
        RECT 5.060 363.255 422.000 364.625 ;
      LAYER met1 ;
        RECT 422.000 363.255 724.315 364.625 ;
      LAYER met1 ;
        RECT 5.060 361.895 421.000 363.255 ;
      LAYER met1 ;
        RECT 421.000 361.895 724.315 363.255 ;
      LAYER met1 ;
        RECT 5.060 361.665 421.430 361.895 ;
      LAYER met1 ;
        RECT 421.430 361.665 724.315 361.895 ;
      LAYER met1 ;
        RECT 5.060 360.635 421.000 361.665 ;
      LAYER met1 ;
        RECT 421.000 360.635 724.315 361.665 ;
      LAYER met1 ;
        RECT 5.060 360.405 421.500 360.635 ;
      LAYER met1 ;
        RECT 421.500 360.405 724.315 360.635 ;
      LAYER met1 ;
        RECT 5.060 355.875 421.000 360.405 ;
      LAYER met1 ;
        RECT 421.000 355.875 724.315 360.405 ;
      LAYER met1 ;
        RECT 5.060 355.645 421.500 355.875 ;
      LAYER met1 ;
        RECT 421.500 355.645 724.315 355.875 ;
      LAYER met1 ;
        RECT 5.060 353.725 421.000 355.645 ;
      LAYER met1 ;
        RECT 421.000 353.725 724.315 355.645 ;
      LAYER met1 ;
        RECT 5.060 352.355 422.000 353.725 ;
      LAYER met1 ;
        RECT 422.000 352.355 724.315 353.725 ;
      LAYER met1 ;
        RECT 5.060 350.995 421.000 352.355 ;
      LAYER met1 ;
        RECT 421.000 350.995 724.315 352.355 ;
      LAYER met1 ;
        RECT 5.060 350.765 421.430 350.995 ;
      LAYER met1 ;
        RECT 421.430 350.765 724.315 350.995 ;
      LAYER met1 ;
        RECT 5.060 349.735 421.000 350.765 ;
      LAYER met1 ;
        RECT 421.000 349.735 724.315 350.765 ;
      LAYER met1 ;
        RECT 5.060 349.505 421.500 349.735 ;
      LAYER met1 ;
        RECT 421.500 349.505 724.315 349.735 ;
      LAYER met1 ;
        RECT 5.060 344.975 421.000 349.505 ;
      LAYER met1 ;
        RECT 421.000 344.975 724.315 349.505 ;
      LAYER met1 ;
        RECT 5.060 344.745 421.500 344.975 ;
      LAYER met1 ;
        RECT 421.500 344.745 724.315 344.975 ;
      LAYER met1 ;
        RECT 5.060 342.825 421.000 344.745 ;
      LAYER met1 ;
        RECT 421.000 342.825 724.315 344.745 ;
      LAYER met1 ;
        RECT 5.060 341.455 422.000 342.825 ;
      LAYER met1 ;
        RECT 422.000 341.455 724.315 342.825 ;
      LAYER met1 ;
        RECT 5.060 340.095 421.000 341.455 ;
      LAYER met1 ;
        RECT 421.000 340.095 724.315 341.455 ;
      LAYER met1 ;
        RECT 5.060 339.865 421.430 340.095 ;
      LAYER met1 ;
        RECT 421.430 339.865 724.315 340.095 ;
      LAYER met1 ;
        RECT 5.060 338.835 421.000 339.865 ;
      LAYER met1 ;
        RECT 421.000 338.835 724.315 339.865 ;
      LAYER met1 ;
        RECT 5.060 338.605 421.500 338.835 ;
      LAYER met1 ;
        RECT 421.500 338.605 724.315 338.835 ;
      LAYER met1 ;
        RECT 5.060 334.075 421.000 338.605 ;
      LAYER met1 ;
        RECT 421.000 334.075 724.315 338.605 ;
      LAYER met1 ;
        RECT 5.060 333.845 421.500 334.075 ;
      LAYER met1 ;
        RECT 421.500 333.845 724.315 334.075 ;
      LAYER met1 ;
        RECT 5.060 331.925 421.000 333.845 ;
      LAYER met1 ;
        RECT 421.000 331.925 724.315 333.845 ;
      LAYER met1 ;
        RECT 5.060 330.555 422.000 331.925 ;
      LAYER met1 ;
        RECT 422.000 330.555 724.315 331.925 ;
      LAYER met1 ;
        RECT 5.060 329.195 421.000 330.555 ;
      LAYER met1 ;
        RECT 421.000 329.195 724.315 330.555 ;
      LAYER met1 ;
        RECT 5.060 328.965 421.430 329.195 ;
      LAYER met1 ;
        RECT 421.430 328.965 724.315 329.195 ;
      LAYER met1 ;
        RECT 5.060 327.935 421.000 328.965 ;
      LAYER met1 ;
        RECT 421.000 327.935 724.315 328.965 ;
      LAYER met1 ;
        RECT 5.060 327.705 421.500 327.935 ;
      LAYER met1 ;
        RECT 421.500 327.705 724.315 327.935 ;
      LAYER met1 ;
        RECT 5.060 323.175 421.000 327.705 ;
      LAYER met1 ;
        RECT 421.000 323.175 724.315 327.705 ;
      LAYER met1 ;
        RECT 5.060 322.945 421.500 323.175 ;
      LAYER met1 ;
        RECT 421.500 322.945 724.315 323.175 ;
      LAYER met1 ;
        RECT 5.060 321.025 421.000 322.945 ;
      LAYER met1 ;
        RECT 421.000 321.025 724.315 322.945 ;
      LAYER met1 ;
        RECT 5.060 319.655 422.000 321.025 ;
      LAYER met1 ;
        RECT 422.000 319.655 724.315 321.025 ;
      LAYER met1 ;
        RECT 5.060 318.295 421.000 319.655 ;
      LAYER met1 ;
        RECT 421.000 318.295 724.315 319.655 ;
      LAYER met1 ;
        RECT 5.060 318.065 421.430 318.295 ;
      LAYER met1 ;
        RECT 421.430 318.065 724.315 318.295 ;
      LAYER met1 ;
        RECT 5.060 317.035 421.000 318.065 ;
      LAYER met1 ;
        RECT 421.000 317.035 724.315 318.065 ;
      LAYER met1 ;
        RECT 5.060 316.805 421.500 317.035 ;
      LAYER met1 ;
        RECT 421.500 316.805 724.315 317.035 ;
      LAYER met1 ;
        RECT 5.060 312.275 421.000 316.805 ;
      LAYER met1 ;
        RECT 421.000 312.275 724.315 316.805 ;
      LAYER met1 ;
        RECT 5.060 312.045 421.500 312.275 ;
      LAYER met1 ;
        RECT 421.500 312.045 724.315 312.275 ;
      LAYER met1 ;
        RECT 5.060 310.125 421.000 312.045 ;
      LAYER met1 ;
        RECT 421.000 310.125 724.315 312.045 ;
      LAYER met1 ;
        RECT 5.060 308.755 422.000 310.125 ;
      LAYER met1 ;
        RECT 422.000 308.755 724.315 310.125 ;
      LAYER met1 ;
        RECT 5.060 307.395 421.000 308.755 ;
      LAYER met1 ;
        RECT 421.000 307.395 724.315 308.755 ;
      LAYER met1 ;
        RECT 5.060 307.165 421.430 307.395 ;
      LAYER met1 ;
        RECT 421.430 307.165 724.315 307.395 ;
      LAYER met1 ;
        RECT 5.060 306.135 421.000 307.165 ;
      LAYER met1 ;
        RECT 421.000 306.135 724.315 307.165 ;
      LAYER met1 ;
        RECT 5.060 305.905 421.500 306.135 ;
      LAYER met1 ;
        RECT 421.500 305.905 724.315 306.135 ;
      LAYER met1 ;
        RECT 5.060 301.375 421.000 305.905 ;
      LAYER met1 ;
        RECT 421.000 301.375 724.315 305.905 ;
      LAYER met1 ;
        RECT 5.060 301.145 421.500 301.375 ;
      LAYER met1 ;
        RECT 421.500 301.145 724.315 301.375 ;
      LAYER met1 ;
        RECT 5.060 299.225 421.000 301.145 ;
      LAYER met1 ;
        RECT 421.000 299.225 724.315 301.145 ;
      LAYER met1 ;
        RECT 5.060 297.855 422.000 299.225 ;
      LAYER met1 ;
        RECT 422.000 297.855 724.315 299.225 ;
      LAYER met1 ;
        RECT 5.060 296.495 421.000 297.855 ;
      LAYER met1 ;
        RECT 421.000 296.495 724.315 297.855 ;
      LAYER met1 ;
        RECT 5.060 296.265 421.430 296.495 ;
      LAYER met1 ;
        RECT 421.430 296.265 724.315 296.495 ;
      LAYER met1 ;
        RECT 5.060 295.235 421.000 296.265 ;
      LAYER met1 ;
        RECT 421.000 295.235 724.315 296.265 ;
      LAYER met1 ;
        RECT 5.060 295.005 421.500 295.235 ;
      LAYER met1 ;
        RECT 421.500 295.005 724.315 295.235 ;
      LAYER met1 ;
        RECT 5.060 290.475 421.000 295.005 ;
      LAYER met1 ;
        RECT 421.000 290.475 724.315 295.005 ;
      LAYER met1 ;
        RECT 5.060 290.245 421.500 290.475 ;
      LAYER met1 ;
        RECT 421.500 290.245 724.315 290.475 ;
      LAYER met1 ;
        RECT 5.060 288.325 421.000 290.245 ;
      LAYER met1 ;
        RECT 421.000 288.325 724.315 290.245 ;
      LAYER met1 ;
        RECT 5.060 286.955 422.000 288.325 ;
      LAYER met1 ;
        RECT 422.000 286.955 724.315 288.325 ;
      LAYER met1 ;
        RECT 5.060 285.595 421.000 286.955 ;
      LAYER met1 ;
        RECT 421.000 285.595 724.315 286.955 ;
      LAYER met1 ;
        RECT 5.060 285.365 421.430 285.595 ;
      LAYER met1 ;
        RECT 421.430 285.365 724.315 285.595 ;
      LAYER met1 ;
        RECT 5.060 284.335 421.000 285.365 ;
      LAYER met1 ;
        RECT 421.000 284.335 724.315 285.365 ;
      LAYER met1 ;
        RECT 5.060 284.105 421.500 284.335 ;
      LAYER met1 ;
        RECT 421.500 284.105 724.315 284.335 ;
      LAYER met1 ;
        RECT 5.060 279.575 421.000 284.105 ;
      LAYER met1 ;
        RECT 421.000 279.575 724.315 284.105 ;
      LAYER met1 ;
        RECT 5.060 279.345 421.500 279.575 ;
      LAYER met1 ;
        RECT 421.500 279.345 724.315 279.575 ;
      LAYER met1 ;
        RECT 5.060 277.425 421.000 279.345 ;
      LAYER met1 ;
        RECT 421.000 277.425 724.315 279.345 ;
      LAYER met1 ;
        RECT 5.060 276.055 422.000 277.425 ;
      LAYER met1 ;
        RECT 422.000 276.055 724.315 277.425 ;
      LAYER met1 ;
        RECT 5.060 274.695 421.000 276.055 ;
      LAYER met1 ;
        RECT 421.000 274.695 724.315 276.055 ;
      LAYER met1 ;
        RECT 5.060 274.465 421.430 274.695 ;
      LAYER met1 ;
        RECT 421.430 274.465 724.315 274.695 ;
      LAYER met1 ;
        RECT 5.060 273.435 421.000 274.465 ;
      LAYER met1 ;
        RECT 421.000 273.435 724.315 274.465 ;
      LAYER met1 ;
        RECT 5.060 273.205 421.500 273.435 ;
      LAYER met1 ;
        RECT 421.500 273.205 724.315 273.435 ;
      LAYER met1 ;
        RECT 5.060 268.675 421.000 273.205 ;
      LAYER met1 ;
        RECT 421.000 268.675 724.315 273.205 ;
      LAYER met1 ;
        RECT 5.060 268.445 421.500 268.675 ;
      LAYER met1 ;
        RECT 421.500 268.445 724.315 268.675 ;
      LAYER met1 ;
        RECT 5.060 266.525 421.000 268.445 ;
      LAYER met1 ;
        RECT 421.000 266.525 724.315 268.445 ;
      LAYER met1 ;
        RECT 5.060 265.155 422.000 266.525 ;
      LAYER met1 ;
        RECT 422.000 265.155 724.315 266.525 ;
      LAYER met1 ;
        RECT 5.060 263.795 421.000 265.155 ;
      LAYER met1 ;
        RECT 421.000 263.795 724.315 265.155 ;
      LAYER met1 ;
        RECT 5.060 263.565 421.430 263.795 ;
      LAYER met1 ;
        RECT 421.430 263.565 724.315 263.795 ;
      LAYER met1 ;
        RECT 5.060 262.535 421.000 263.565 ;
      LAYER met1 ;
        RECT 421.000 262.535 724.315 263.565 ;
      LAYER met1 ;
        RECT 5.060 262.305 421.500 262.535 ;
      LAYER met1 ;
        RECT 421.500 262.305 724.315 262.535 ;
      LAYER met1 ;
        RECT 5.060 257.775 421.000 262.305 ;
      LAYER met1 ;
        RECT 421.000 257.775 724.315 262.305 ;
      LAYER met1 ;
        RECT 5.060 257.545 421.500 257.775 ;
      LAYER met1 ;
        RECT 421.500 257.545 724.315 257.775 ;
      LAYER met1 ;
        RECT 5.060 255.955 421.000 257.545 ;
      LAYER met1 ;
        RECT 421.000 255.955 724.315 257.545 ;
      LAYER met1 ;
        RECT 5.060 255.765 422.015 255.955 ;
      LAYER met1 ;
        RECT 422.015 255.765 724.315 255.955 ;
      LAYER met1 ;
        RECT 5.060 255.625 421.000 255.765 ;
      LAYER met1 ;
        RECT 421.000 255.625 724.315 255.765 ;
      LAYER met1 ;
        RECT 5.060 254.255 422.000 255.625 ;
      LAYER met1 ;
        RECT 422.000 254.255 724.315 255.625 ;
      LAYER met1 ;
        RECT 5.060 252.895 421.000 254.255 ;
      LAYER met1 ;
        RECT 421.000 252.895 724.315 254.255 ;
      LAYER met1 ;
        RECT 5.060 252.665 421.430 252.895 ;
      LAYER met1 ;
        RECT 421.430 252.665 724.315 252.895 ;
      LAYER met1 ;
        RECT 5.060 251.635 421.000 252.665 ;
      LAYER met1 ;
        RECT 421.000 251.635 724.315 252.665 ;
      LAYER met1 ;
        RECT 5.060 251.405 421.500 251.635 ;
      LAYER met1 ;
        RECT 421.500 251.405 724.315 251.635 ;
      LAYER met1 ;
        RECT 5.060 249.730 421.000 251.405 ;
      LAYER met1 ;
        RECT 421.000 249.730 724.315 251.405 ;
      LAYER met1 ;
        RECT 5.060 249.470 421.630 249.730 ;
      LAYER met1 ;
        RECT 421.630 249.470 724.315 249.730 ;
      LAYER met1 ;
        RECT 5.060 248.805 421.000 249.470 ;
      LAYER met1 ;
        RECT 421.000 248.805 724.315 249.470 ;
      LAYER met1 ;
        RECT 5.060 248.545 421.620 248.805 ;
      LAYER met1 ;
        RECT 421.620 248.545 724.315 248.805 ;
      LAYER met1 ;
        RECT 5.060 245.665 421.000 248.545 ;
      LAYER met1 ;
        RECT 421.000 245.665 724.315 248.545 ;
      LAYER met1 ;
        RECT 5.060 245.405 421.605 245.665 ;
      LAYER met1 ;
        RECT 421.605 245.405 724.315 245.665 ;
      LAYER met1 ;
        RECT 5.060 245.265 421.000 245.405 ;
      LAYER met1 ;
        RECT 421.000 245.265 724.315 245.405 ;
      LAYER met1 ;
        RECT 5.060 245.005 421.610 245.265 ;
      LAYER met1 ;
        RECT 421.610 245.005 724.315 245.265 ;
      LAYER met1 ;
        RECT 5.060 242.125 421.000 245.005 ;
      LAYER met1 ;
        RECT 421.000 242.125 724.315 245.005 ;
      LAYER met1 ;
        RECT 5.060 241.865 421.550 242.125 ;
      LAYER met1 ;
        RECT 421.550 241.865 724.315 242.125 ;
      LAYER met1 ;
        RECT 5.060 241.725 421.000 241.865 ;
      LAYER met1 ;
        RECT 421.000 241.725 724.315 241.865 ;
      LAYER met1 ;
        RECT 5.060 241.465 421.535 241.725 ;
      LAYER met1 ;
        RECT 421.535 241.465 724.315 241.725 ;
      LAYER met1 ;
        RECT 5.060 238.585 421.000 241.465 ;
      LAYER met1 ;
        RECT 421.000 238.585 724.315 241.465 ;
      LAYER met1 ;
        RECT 5.060 238.325 421.590 238.585 ;
      LAYER met1 ;
        RECT 421.590 238.325 724.315 238.585 ;
      LAYER met1 ;
        RECT 5.060 238.185 421.000 238.325 ;
      LAYER met1 ;
        RECT 421.000 238.185 724.315 238.325 ;
      LAYER met1 ;
        RECT 5.060 237.925 421.575 238.185 ;
      LAYER met1 ;
        RECT 421.575 237.925 724.315 238.185 ;
      LAYER met1 ;
        RECT 5.060 231.505 421.000 237.925 ;
      LAYER met1 ;
        RECT 421.000 234.065 724.315 237.925 ;
        RECT 421.000 233.805 724.055 234.065 ;
      LAYER met1 ;
        RECT 724.055 233.805 724.775 234.065 ;
      LAYER met1 ;
        RECT 421.000 231.505 724.315 233.805 ;
      LAYER met1 ;
        RECT 5.060 231.245 421.510 231.505 ;
      LAYER met1 ;
        RECT 421.510 231.245 724.315 231.505 ;
      LAYER met1 ;
        RECT 5.060 231.105 421.000 231.245 ;
      LAYER met1 ;
        RECT 421.000 231.105 724.315 231.245 ;
      LAYER met1 ;
        RECT 5.060 230.845 421.510 231.105 ;
      LAYER met1 ;
        RECT 421.510 230.845 724.315 231.105 ;
      LAYER met1 ;
        RECT 5.060 227.965 421.000 230.845 ;
      LAYER met1 ;
        RECT 421.000 227.965 724.315 230.845 ;
      LAYER met1 ;
        RECT 5.060 227.705 421.510 227.965 ;
      LAYER met1 ;
        RECT 421.510 227.705 724.315 227.965 ;
      LAYER met1 ;
        RECT 5.060 227.565 421.000 227.705 ;
      LAYER met1 ;
        RECT 421.000 227.565 724.315 227.705 ;
      LAYER met1 ;
        RECT 5.060 227.305 421.505 227.565 ;
      LAYER met1 ;
        RECT 421.505 227.305 724.315 227.565 ;
      LAYER met1 ;
        RECT 5.060 224.420 421.000 227.305 ;
      LAYER met1 ;
        RECT 421.000 224.420 724.315 227.305 ;
      LAYER met1 ;
        RECT 5.060 224.165 421.675 224.420 ;
      LAYER met1 ;
        RECT 421.675 224.165 724.315 224.420 ;
      LAYER met1 ;
        RECT 5.060 224.025 421.000 224.165 ;
      LAYER met1 ;
        RECT 421.000 224.025 724.315 224.165 ;
      LAYER met1 ;
        RECT 5.060 223.765 421.665 224.025 ;
      LAYER met1 ;
        RECT 421.665 223.765 724.315 224.025 ;
      LAYER met1 ;
        RECT 5.060 219.685 421.000 223.765 ;
      LAYER met1 ;
        RECT 421.000 219.685 724.315 223.765 ;
      LAYER met1 ;
        RECT 5.060 219.485 421.865 219.685 ;
      LAYER met1 ;
        RECT 421.865 219.485 724.315 219.685 ;
      LAYER met1 ;
        RECT 5.060 219.345 421.000 219.485 ;
      LAYER met1 ;
        RECT 421.000 219.345 724.315 219.485 ;
      LAYER met1 ;
        RECT 5.060 219.145 421.880 219.345 ;
      LAYER met1 ;
        RECT 421.880 219.145 724.315 219.345 ;
      LAYER met1 ;
        RECT 5.060 217.985 421.000 219.145 ;
      LAYER met1 ;
        RECT 421.000 217.985 724.315 219.145 ;
      LAYER met1 ;
        RECT 5.060 217.795 421.785 217.985 ;
      LAYER met1 ;
        RECT 421.785 217.795 724.315 217.985 ;
      LAYER met1 ;
        RECT 5.060 216.465 421.000 217.795 ;
      LAYER met1 ;
        RECT 421.000 216.465 724.315 217.795 ;
      LAYER met1 ;
        RECT 5.060 216.235 421.500 216.465 ;
      LAYER met1 ;
        RECT 421.500 216.235 724.315 216.465 ;
      LAYER met1 ;
        RECT 5.060 215.205 421.000 216.235 ;
      LAYER met1 ;
        RECT 421.000 215.205 724.315 216.235 ;
      LAYER met1 ;
        RECT 5.060 214.975 421.430 215.205 ;
      LAYER met1 ;
        RECT 421.430 214.975 724.315 215.205 ;
      LAYER met1 ;
        RECT 5.060 213.615 421.000 214.975 ;
      LAYER met1 ;
        RECT 421.000 213.615 724.315 214.975 ;
      LAYER met1 ;
        RECT 5.060 212.245 422.000 213.615 ;
      LAYER met1 ;
        RECT 422.000 212.245 724.315 213.615 ;
      LAYER met1 ;
        RECT 5.060 210.325 421.000 212.245 ;
      LAYER met1 ;
        RECT 421.000 210.325 724.315 212.245 ;
      LAYER met1 ;
        RECT 5.060 210.095 421.500 210.325 ;
      LAYER met1 ;
        RECT 421.500 210.095 724.315 210.325 ;
      LAYER met1 ;
        RECT 5.060 207.525 421.000 210.095 ;
      LAYER met1 ;
        RECT 421.000 207.525 724.315 210.095 ;
      LAYER met1 ;
        RECT 5.060 207.275 421.630 207.525 ;
      LAYER met1 ;
        RECT 421.630 207.275 724.315 207.525 ;
      LAYER met1 ;
        RECT 5.060 207.135 421.000 207.275 ;
      LAYER met1 ;
        RECT 421.000 207.135 724.315 207.275 ;
      LAYER met1 ;
        RECT 5.060 206.895 421.635 207.135 ;
      LAYER met1 ;
        RECT 421.635 206.895 724.315 207.135 ;
      LAYER met1 ;
        RECT 5.060 205.565 421.000 206.895 ;
      LAYER met1 ;
        RECT 421.000 205.565 724.315 206.895 ;
      LAYER met1 ;
        RECT 5.060 205.335 421.500 205.565 ;
      LAYER met1 ;
        RECT 421.500 205.335 724.315 205.565 ;
      LAYER met1 ;
        RECT 5.060 204.305 421.000 205.335 ;
      LAYER met1 ;
        RECT 421.000 204.305 724.315 205.335 ;
      LAYER met1 ;
        RECT 5.060 204.075 421.430 204.305 ;
      LAYER met1 ;
        RECT 421.430 204.075 724.315 204.305 ;
      LAYER met1 ;
        RECT 5.060 202.715 421.000 204.075 ;
      LAYER met1 ;
        RECT 421.000 202.715 724.315 204.075 ;
      LAYER met1 ;
        RECT 5.060 201.345 422.000 202.715 ;
      LAYER met1 ;
        RECT 422.000 201.345 724.315 202.715 ;
      LAYER met1 ;
        RECT 5.060 200.825 421.000 201.345 ;
      LAYER met1 ;
        RECT 421.000 200.825 724.315 201.345 ;
      LAYER met1 ;
        RECT 5.060 200.595 421.645 200.825 ;
      LAYER met1 ;
        RECT 421.645 200.595 724.315 200.825 ;
      LAYER met1 ;
        RECT 5.060 199.425 421.000 200.595 ;
      LAYER met1 ;
        RECT 421.000 199.425 724.315 200.595 ;
      LAYER met1 ;
        RECT 5.060 199.195 421.500 199.425 ;
      LAYER met1 ;
        RECT 421.500 199.195 724.315 199.425 ;
      LAYER met1 ;
        RECT 5.060 194.665 421.000 199.195 ;
      LAYER met1 ;
        RECT 421.000 194.665 724.315 199.195 ;
      LAYER met1 ;
        RECT 5.060 194.435 421.500 194.665 ;
      LAYER met1 ;
        RECT 421.500 194.435 724.315 194.665 ;
      LAYER met1 ;
        RECT 5.060 193.405 421.000 194.435 ;
      LAYER met1 ;
        RECT 421.000 193.405 724.315 194.435 ;
      LAYER met1 ;
        RECT 5.060 193.175 421.430 193.405 ;
      LAYER met1 ;
        RECT 421.430 193.175 724.315 193.405 ;
      LAYER met1 ;
        RECT 5.060 191.815 421.000 193.175 ;
      LAYER met1 ;
        RECT 421.000 191.815 724.315 193.175 ;
      LAYER met1 ;
        RECT 5.060 190.445 422.000 191.815 ;
      LAYER met1 ;
        RECT 422.000 190.445 724.315 191.815 ;
      LAYER met1 ;
        RECT 5.060 188.525 421.000 190.445 ;
      LAYER met1 ;
        RECT 421.000 188.525 724.315 190.445 ;
      LAYER met1 ;
        RECT 5.060 188.295 421.500 188.525 ;
      LAYER met1 ;
        RECT 421.500 188.295 724.315 188.525 ;
      LAYER met1 ;
        RECT 5.060 183.765 421.000 188.295 ;
      LAYER met1 ;
        RECT 421.000 183.765 724.315 188.295 ;
      LAYER met1 ;
        RECT 5.060 183.535 421.500 183.765 ;
      LAYER met1 ;
        RECT 421.500 183.535 724.315 183.765 ;
      LAYER met1 ;
        RECT 5.060 182.505 421.000 183.535 ;
      LAYER met1 ;
        RECT 421.000 182.505 724.315 183.535 ;
      LAYER met1 ;
        RECT 5.060 182.275 421.430 182.505 ;
      LAYER met1 ;
        RECT 421.430 182.275 724.315 182.505 ;
      LAYER met1 ;
        RECT 5.060 180.915 421.000 182.275 ;
      LAYER met1 ;
        RECT 421.000 180.915 724.315 182.275 ;
      LAYER met1 ;
        RECT 5.060 179.545 422.000 180.915 ;
      LAYER met1 ;
        RECT 422.000 179.545 724.315 180.915 ;
      LAYER met1 ;
        RECT 5.060 177.625 421.000 179.545 ;
      LAYER met1 ;
        RECT 421.000 177.625 724.315 179.545 ;
      LAYER met1 ;
        RECT 5.060 177.395 421.500 177.625 ;
      LAYER met1 ;
        RECT 421.500 177.395 724.315 177.625 ;
      LAYER met1 ;
        RECT 5.060 172.865 421.000 177.395 ;
      LAYER met1 ;
        RECT 421.000 172.865 724.315 177.395 ;
      LAYER met1 ;
        RECT 5.060 172.635 421.500 172.865 ;
      LAYER met1 ;
        RECT 421.500 172.635 724.315 172.865 ;
      LAYER met1 ;
        RECT 5.060 171.605 421.000 172.635 ;
      LAYER met1 ;
        RECT 421.000 171.605 724.315 172.635 ;
      LAYER met1 ;
        RECT 5.060 171.375 421.430 171.605 ;
      LAYER met1 ;
        RECT 421.430 171.375 724.315 171.605 ;
      LAYER met1 ;
        RECT 5.060 170.015 421.000 171.375 ;
      LAYER met1 ;
        RECT 421.000 170.015 724.315 171.375 ;
      LAYER met1 ;
        RECT 5.060 168.645 422.000 170.015 ;
      LAYER met1 ;
        RECT 422.000 168.645 724.315 170.015 ;
      LAYER met1 ;
        RECT 5.060 166.725 421.000 168.645 ;
      LAYER met1 ;
        RECT 421.000 166.725 724.315 168.645 ;
      LAYER met1 ;
        RECT 5.060 166.495 421.500 166.725 ;
      LAYER met1 ;
        RECT 421.500 166.495 724.315 166.725 ;
      LAYER met1 ;
        RECT 5.060 161.965 421.000 166.495 ;
      LAYER met1 ;
        RECT 421.000 161.965 724.315 166.495 ;
      LAYER met1 ;
        RECT 5.060 161.735 421.500 161.965 ;
      LAYER met1 ;
        RECT 421.500 161.735 724.315 161.965 ;
      LAYER met1 ;
        RECT 5.060 160.705 421.000 161.735 ;
      LAYER met1 ;
        RECT 421.000 160.705 724.315 161.735 ;
      LAYER met1 ;
        RECT 5.060 160.475 421.430 160.705 ;
      LAYER met1 ;
        RECT 421.430 160.475 724.315 160.705 ;
      LAYER met1 ;
        RECT 5.060 159.115 421.000 160.475 ;
      LAYER met1 ;
        RECT 421.000 159.115 724.315 160.475 ;
      LAYER met1 ;
        RECT 5.060 157.745 422.000 159.115 ;
      LAYER met1 ;
        RECT 422.000 157.745 724.315 159.115 ;
      LAYER met1 ;
        RECT 5.060 155.825 421.000 157.745 ;
      LAYER met1 ;
        RECT 421.000 155.825 724.315 157.745 ;
      LAYER met1 ;
        RECT 5.060 155.595 421.500 155.825 ;
      LAYER met1 ;
        RECT 421.500 155.595 724.315 155.825 ;
      LAYER met1 ;
        RECT 5.060 151.065 421.000 155.595 ;
      LAYER met1 ;
        RECT 421.000 151.065 724.315 155.595 ;
      LAYER met1 ;
        RECT 5.060 150.835 421.500 151.065 ;
      LAYER met1 ;
        RECT 421.500 150.835 724.315 151.065 ;
      LAYER met1 ;
        RECT 5.060 149.805 421.000 150.835 ;
      LAYER met1 ;
        RECT 421.000 149.805 724.315 150.835 ;
      LAYER met1 ;
        RECT 5.060 149.575 421.430 149.805 ;
      LAYER met1 ;
        RECT 421.430 149.575 724.315 149.805 ;
      LAYER met1 ;
        RECT 5.060 148.215 421.000 149.575 ;
      LAYER met1 ;
        RECT 421.000 148.215 724.315 149.575 ;
      LAYER met1 ;
        RECT 5.060 146.845 422.000 148.215 ;
      LAYER met1 ;
        RECT 422.000 146.845 724.315 148.215 ;
      LAYER met1 ;
        RECT 5.060 144.925 421.000 146.845 ;
      LAYER met1 ;
        RECT 421.000 144.925 724.315 146.845 ;
      LAYER met1 ;
        RECT 5.060 144.695 421.500 144.925 ;
      LAYER met1 ;
        RECT 421.500 144.695 724.315 144.925 ;
      LAYER met1 ;
        RECT 5.060 140.165 421.000 144.695 ;
      LAYER met1 ;
        RECT 421.000 140.165 724.315 144.695 ;
      LAYER met1 ;
        RECT 5.060 139.935 421.500 140.165 ;
      LAYER met1 ;
        RECT 421.500 139.935 724.315 140.165 ;
      LAYER met1 ;
        RECT 5.060 138.905 421.000 139.935 ;
      LAYER met1 ;
        RECT 421.000 138.905 724.315 139.935 ;
      LAYER met1 ;
        RECT 5.060 138.675 421.430 138.905 ;
      LAYER met1 ;
        RECT 421.430 138.675 724.315 138.905 ;
      LAYER met1 ;
        RECT 5.060 137.315 421.000 138.675 ;
      LAYER met1 ;
        RECT 421.000 137.315 724.315 138.675 ;
      LAYER met1 ;
        RECT 5.060 135.945 422.000 137.315 ;
      LAYER met1 ;
        RECT 422.000 135.945 724.315 137.315 ;
      LAYER met1 ;
        RECT 5.060 134.025 421.000 135.945 ;
      LAYER met1 ;
        RECT 421.000 134.025 724.315 135.945 ;
      LAYER met1 ;
        RECT 5.060 133.795 421.500 134.025 ;
      LAYER met1 ;
        RECT 421.500 133.795 724.315 134.025 ;
      LAYER met1 ;
        RECT 5.060 129.265 421.000 133.795 ;
      LAYER met1 ;
        RECT 421.000 129.265 724.315 133.795 ;
      LAYER met1 ;
        RECT 5.060 129.035 421.500 129.265 ;
      LAYER met1 ;
        RECT 421.500 129.035 724.315 129.265 ;
      LAYER met1 ;
        RECT 5.060 128.005 421.000 129.035 ;
      LAYER met1 ;
        RECT 421.000 128.005 724.315 129.035 ;
      LAYER met1 ;
        RECT 5.060 127.775 421.430 128.005 ;
      LAYER met1 ;
        RECT 421.430 127.775 724.315 128.005 ;
      LAYER met1 ;
        RECT 5.060 126.415 421.000 127.775 ;
      LAYER met1 ;
        RECT 421.000 126.415 724.315 127.775 ;
      LAYER met1 ;
        RECT 5.060 125.045 422.000 126.415 ;
      LAYER met1 ;
        RECT 422.000 125.045 724.315 126.415 ;
      LAYER met1 ;
        RECT 5.060 123.125 421.000 125.045 ;
      LAYER met1 ;
        RECT 421.000 123.125 724.315 125.045 ;
      LAYER met1 ;
        RECT 5.060 122.895 421.500 123.125 ;
      LAYER met1 ;
        RECT 421.500 122.895 724.315 123.125 ;
      LAYER met1 ;
        RECT 5.060 118.365 421.000 122.895 ;
      LAYER met1 ;
        RECT 421.000 118.365 724.315 122.895 ;
      LAYER met1 ;
        RECT 5.060 118.135 421.500 118.365 ;
      LAYER met1 ;
        RECT 421.500 118.135 724.315 118.365 ;
      LAYER met1 ;
        RECT 5.060 117.105 421.000 118.135 ;
      LAYER met1 ;
        RECT 421.000 117.105 724.315 118.135 ;
      LAYER met1 ;
        RECT 5.060 116.875 421.430 117.105 ;
      LAYER met1 ;
        RECT 421.430 116.875 724.315 117.105 ;
      LAYER met1 ;
        RECT 5.060 115.515 421.000 116.875 ;
      LAYER met1 ;
        RECT 421.000 115.515 724.315 116.875 ;
      LAYER met1 ;
        RECT 5.060 114.145 422.000 115.515 ;
      LAYER met1 ;
        RECT 422.000 114.145 724.315 115.515 ;
      LAYER met1 ;
        RECT 5.060 112.225 421.000 114.145 ;
      LAYER met1 ;
        RECT 421.000 112.225 724.315 114.145 ;
      LAYER met1 ;
        RECT 5.060 111.995 421.500 112.225 ;
      LAYER met1 ;
        RECT 421.500 111.995 724.315 112.225 ;
      LAYER met1 ;
        RECT 5.060 107.465 421.000 111.995 ;
      LAYER met1 ;
        RECT 421.000 107.465 724.315 111.995 ;
      LAYER met1 ;
        RECT 5.060 107.235 421.500 107.465 ;
      LAYER met1 ;
        RECT 421.500 107.235 724.315 107.465 ;
      LAYER met1 ;
        RECT 5.060 106.205 421.000 107.235 ;
      LAYER met1 ;
        RECT 421.000 106.205 724.315 107.235 ;
      LAYER met1 ;
        RECT 5.060 105.975 421.430 106.205 ;
      LAYER met1 ;
        RECT 421.430 105.975 724.315 106.205 ;
      LAYER met1 ;
        RECT 5.060 104.615 421.000 105.975 ;
      LAYER met1 ;
        RECT 421.000 104.615 724.315 105.975 ;
      LAYER met1 ;
        RECT 5.060 103.245 422.000 104.615 ;
      LAYER met1 ;
        RECT 422.000 103.245 724.315 104.615 ;
      LAYER met1 ;
        RECT 5.060 101.325 421.000 103.245 ;
      LAYER met1 ;
        RECT 421.000 101.325 724.315 103.245 ;
      LAYER met1 ;
        RECT 5.060 101.095 421.500 101.325 ;
      LAYER met1 ;
        RECT 421.500 101.095 724.315 101.325 ;
      LAYER met1 ;
        RECT 5.060 96.565 421.000 101.095 ;
      LAYER met1 ;
        RECT 421.000 96.565 724.315 101.095 ;
      LAYER met1 ;
        RECT 5.060 96.335 421.500 96.565 ;
      LAYER met1 ;
        RECT 421.500 96.335 724.315 96.565 ;
      LAYER met1 ;
        RECT 5.060 95.305 421.000 96.335 ;
      LAYER met1 ;
        RECT 421.000 95.305 724.315 96.335 ;
      LAYER met1 ;
        RECT 5.060 95.075 421.430 95.305 ;
      LAYER met1 ;
        RECT 421.430 95.075 724.315 95.305 ;
      LAYER met1 ;
        RECT 5.060 93.715 421.000 95.075 ;
      LAYER met1 ;
        RECT 421.000 93.715 724.315 95.075 ;
      LAYER met1 ;
        RECT 5.060 92.345 422.000 93.715 ;
      LAYER met1 ;
        RECT 422.000 92.345 724.315 93.715 ;
      LAYER met1 ;
        RECT 5.060 90.425 421.000 92.345 ;
      LAYER met1 ;
        RECT 421.000 90.425 724.315 92.345 ;
      LAYER met1 ;
        RECT 5.060 90.195 421.500 90.425 ;
      LAYER met1 ;
        RECT 421.500 90.195 724.315 90.425 ;
      LAYER met1 ;
        RECT 5.060 85.665 421.000 90.195 ;
      LAYER met1 ;
        RECT 421.000 85.665 724.315 90.195 ;
      LAYER met1 ;
        RECT 5.060 85.435 421.500 85.665 ;
      LAYER met1 ;
        RECT 421.500 85.435 724.315 85.665 ;
      LAYER met1 ;
        RECT 5.060 84.405 421.000 85.435 ;
      LAYER met1 ;
        RECT 421.000 84.405 724.315 85.435 ;
      LAYER met1 ;
        RECT 5.060 84.175 421.430 84.405 ;
      LAYER met1 ;
        RECT 421.430 84.175 724.315 84.405 ;
      LAYER met1 ;
        RECT 5.060 82.815 421.000 84.175 ;
      LAYER met1 ;
        RECT 421.000 82.815 724.315 84.175 ;
      LAYER met1 ;
        RECT 5.060 81.445 422.000 82.815 ;
      LAYER met1 ;
        RECT 422.000 81.445 724.315 82.815 ;
      LAYER met1 ;
        RECT 5.060 79.525 421.000 81.445 ;
      LAYER met1 ;
        RECT 421.000 79.525 724.315 81.445 ;
      LAYER met1 ;
        RECT 5.060 79.295 421.500 79.525 ;
      LAYER met1 ;
        RECT 421.500 79.295 724.315 79.525 ;
      LAYER met1 ;
        RECT 5.060 74.765 421.000 79.295 ;
      LAYER met1 ;
        RECT 421.000 74.765 724.315 79.295 ;
      LAYER met1 ;
        RECT 5.060 74.535 421.500 74.765 ;
      LAYER met1 ;
        RECT 421.500 74.535 724.315 74.765 ;
      LAYER met1 ;
        RECT 5.060 73.505 421.000 74.535 ;
      LAYER met1 ;
        RECT 421.000 73.505 724.315 74.535 ;
      LAYER met1 ;
        RECT 5.060 73.275 421.430 73.505 ;
      LAYER met1 ;
        RECT 421.430 73.275 724.315 73.505 ;
      LAYER met1 ;
        RECT 5.060 71.915 421.000 73.275 ;
      LAYER met1 ;
        RECT 421.000 71.915 724.315 73.275 ;
      LAYER met1 ;
        RECT 5.060 70.545 422.000 71.915 ;
      LAYER met1 ;
        RECT 422.000 70.545 724.315 71.915 ;
      LAYER met1 ;
        RECT 5.060 68.625 421.000 70.545 ;
      LAYER met1 ;
        RECT 421.000 68.625 724.315 70.545 ;
      LAYER met1 ;
        RECT 5.060 68.395 421.500 68.625 ;
      LAYER met1 ;
        RECT 421.500 68.395 724.315 68.625 ;
      LAYER met1 ;
        RECT 5.060 63.865 421.000 68.395 ;
      LAYER met1 ;
        RECT 421.000 63.865 724.315 68.395 ;
      LAYER met1 ;
        RECT 5.060 63.635 421.500 63.865 ;
      LAYER met1 ;
        RECT 421.500 63.635 724.315 63.865 ;
      LAYER met1 ;
        RECT 5.060 62.605 421.000 63.635 ;
      LAYER met1 ;
        RECT 421.000 62.605 724.315 63.635 ;
      LAYER met1 ;
        RECT 5.060 62.375 421.430 62.605 ;
      LAYER met1 ;
        RECT 421.430 62.375 724.315 62.605 ;
      LAYER met1 ;
        RECT 5.060 61.015 421.000 62.375 ;
      LAYER met1 ;
        RECT 421.000 61.015 724.315 62.375 ;
      LAYER met1 ;
        RECT 5.060 59.645 422.000 61.015 ;
      LAYER met1 ;
        RECT 422.000 59.645 724.315 61.015 ;
      LAYER met1 ;
        RECT 5.060 57.725 421.000 59.645 ;
      LAYER met1 ;
        RECT 421.000 57.725 724.315 59.645 ;
      LAYER met1 ;
        RECT 5.060 57.495 421.500 57.725 ;
      LAYER met1 ;
        RECT 421.500 57.495 724.315 57.725 ;
      LAYER met1 ;
        RECT 5.060 52.965 421.000 57.495 ;
      LAYER met1 ;
        RECT 421.000 55.610 724.315 57.495 ;
        RECT 421.000 53.370 724.035 55.610 ;
      LAYER met1 ;
        RECT 724.035 53.370 724.315 55.610 ;
      LAYER met1 ;
        RECT 421.000 52.965 724.315 53.370 ;
      LAYER met1 ;
        RECT 5.060 52.735 421.500 52.965 ;
      LAYER met1 ;
        RECT 421.500 52.735 724.315 52.965 ;
      LAYER met1 ;
        RECT 5.060 51.705 421.000 52.735 ;
      LAYER met1 ;
        RECT 421.000 51.705 724.315 52.735 ;
      LAYER met1 ;
        RECT 5.060 51.475 421.430 51.705 ;
      LAYER met1 ;
        RECT 421.430 51.475 724.315 51.705 ;
      LAYER met1 ;
        RECT 5.060 50.115 421.000 51.475 ;
      LAYER met1 ;
        RECT 421.000 50.115 724.315 51.475 ;
      LAYER met1 ;
        RECT 5.060 48.745 422.000 50.115 ;
      LAYER met1 ;
        RECT 422.000 48.745 724.315 50.115 ;
      LAYER met1 ;
        RECT 5.060 46.825 421.000 48.745 ;
      LAYER met1 ;
        RECT 421.000 46.825 724.315 48.745 ;
      LAYER met1 ;
        RECT 5.060 46.595 421.500 46.825 ;
      LAYER met1 ;
        RECT 421.500 46.595 724.315 46.825 ;
      LAYER met1 ;
        RECT 5.060 40.000 421.000 46.595 ;
      LAYER met1 ;
        RECT 421.000 45.580 724.315 46.595 ;
        RECT 421.000 45.080 723.980 45.580 ;
      LAYER met1 ;
        RECT 723.980 45.080 724.315 45.580 ;
      LAYER met1 ;
        RECT 421.000 42.835 724.315 45.080 ;
        RECT 421.000 41.140 724.035 42.835 ;
      LAYER met1 ;
        RECT 724.035 41.140 724.315 42.835 ;
      LAYER met1 ;
        RECT 421.000 40.000 724.315 41.140 ;
      LAYER met1 ;
        RECT 5.060 3.100 680.000 40.000 ;
      LAYER met2 ;
        RECT 10.130 30.140 358.900 1629.125 ;
        RECT 10.130 30.000 20.660 30.140 ;
        RECT 11.220 4.920 20.660 30.000 ;
        RECT 22.980 4.920 58.900 30.140 ;
        RECT 61.220 4.920 70.660 30.140 ;
        RECT 72.980 4.920 108.900 30.140 ;
        RECT 111.220 4.920 120.660 30.140 ;
        RECT 122.980 4.920 158.900 30.140 ;
        RECT 161.220 4.920 170.660 30.140 ;
        RECT 172.980 4.920 208.900 30.140 ;
        RECT 211.220 4.920 220.660 30.140 ;
        RECT 222.980 30.000 308.900 30.140 ;
        RECT 222.980 4.920 258.900 30.000 ;
        RECT 261.220 4.920 270.660 30.000 ;
        RECT 272.980 4.920 308.900 30.000 ;
        RECT 311.220 4.920 320.660 30.140 ;
        RECT 322.980 4.920 358.900 30.140 ;
        RECT 361.220 4.920 370.660 1629.125 ;
        RECT 372.980 1628.170 680.000 1629.125 ;
        RECT 372.980 1627.190 484.205 1628.170 ;
      LAYER met2 ;
        RECT 484.205 1627.890 722.050 1628.170 ;
      LAYER met2 ;
        RECT 722.050 1627.890 724.315 1628.170 ;
      LAYER met2 ;
        RECT 484.205 1627.190 724.315 1627.890 ;
      LAYER met2 ;
        RECT 372.980 1627.030 486.265 1627.190 ;
      LAYER met2 ;
        RECT 486.265 1627.030 724.315 1627.190 ;
      LAYER met2 ;
        RECT 372.980 1626.940 489.470 1627.030 ;
      LAYER met2 ;
        RECT 489.470 1626.940 723.795 1627.030 ;
      LAYER met2 ;
        RECT 372.980 1625.160 677.910 1626.940 ;
      LAYER met2 ;
        RECT 677.910 1625.160 691.890 1626.940 ;
      LAYER met2 ;
        RECT 372.980 1243.310 678.645 1625.160 ;
      LAYER met2 ;
        RECT 678.645 1243.310 691.890 1625.160 ;
      LAYER met2 ;
        RECT 372.980 1241.530 677.910 1243.310 ;
      LAYER met2 ;
        RECT 677.910 1241.530 691.890 1243.310 ;
      LAYER met2 ;
        RECT 691.890 1241.530 692.360 1626.940 ;
      LAYER met2 ;
        RECT 692.360 1625.160 706.340 1626.940 ;
        RECT 692.360 1243.310 692.625 1625.160 ;
      LAYER met2 ;
        RECT 692.625 1243.310 693.095 1625.160 ;
      LAYER met2 ;
        RECT 693.095 1243.310 706.340 1625.160 ;
        RECT 692.360 1241.530 706.340 1243.310 ;
      LAYER met2 ;
        RECT 706.340 1241.530 706.810 1626.940 ;
      LAYER met2 ;
        RECT 706.810 1626.390 723.795 1626.940 ;
        RECT 706.810 1625.160 722.655 1626.390 ;
        RECT 706.810 1243.310 707.075 1625.160 ;
      LAYER met2 ;
        RECT 707.075 1243.310 707.545 1625.160 ;
      LAYER met2 ;
        RECT 707.545 1243.310 722.655 1625.160 ;
        RECT 706.810 1242.080 722.655 1243.310 ;
      LAYER met2 ;
        RECT 722.655 1242.080 723.655 1626.390 ;
      LAYER met2 ;
        RECT 723.655 1242.080 723.795 1626.390 ;
        RECT 706.810 1241.530 723.795 1242.080 ;
      LAYER met2 ;
        RECT 372.980 1241.440 489.470 1241.530 ;
      LAYER met2 ;
        RECT 489.470 1241.440 723.795 1241.530 ;
      LAYER met2 ;
        RECT 723.795 1241.440 724.315 1627.030 ;
        RECT 724.465 1434.050 724.745 1434.420 ;
        RECT 372.980 1241.280 486.265 1241.440 ;
      LAYER met2 ;
        RECT 486.265 1241.280 724.315 1241.440 ;
      LAYER met2 ;
        RECT 372.980 1240.300 484.205 1241.280 ;
      LAYER met2 ;
        RECT 484.205 1240.580 724.315 1241.280 ;
        RECT 484.205 1240.300 722.050 1240.580 ;
      LAYER met2 ;
        RECT 722.050 1240.300 724.315 1240.580 ;
        RECT 372.980 1228.370 680.000 1240.300 ;
        RECT 372.980 1227.390 484.205 1228.370 ;
      LAYER met2 ;
        RECT 484.205 1228.090 722.050 1228.370 ;
      LAYER met2 ;
        RECT 722.050 1228.090 724.315 1228.370 ;
      LAYER met2 ;
        RECT 484.205 1227.390 724.315 1228.090 ;
      LAYER met2 ;
        RECT 372.980 1227.230 486.265 1227.390 ;
      LAYER met2 ;
        RECT 486.265 1227.230 724.315 1227.390 ;
      LAYER met2 ;
        RECT 372.980 1227.140 489.470 1227.230 ;
      LAYER met2 ;
        RECT 489.470 1227.140 723.795 1227.230 ;
      LAYER met2 ;
        RECT 372.980 1225.360 677.910 1227.140 ;
      LAYER met2 ;
        RECT 677.910 1225.360 691.890 1227.140 ;
      LAYER met2 ;
        RECT 372.980 843.510 678.645 1225.360 ;
      LAYER met2 ;
        RECT 678.645 843.510 691.890 1225.360 ;
      LAYER met2 ;
        RECT 372.980 841.730 677.910 843.510 ;
      LAYER met2 ;
        RECT 677.910 841.730 691.890 843.510 ;
      LAYER met2 ;
        RECT 691.890 841.730 692.360 1227.140 ;
      LAYER met2 ;
        RECT 692.360 1225.360 706.340 1227.140 ;
        RECT 692.360 843.510 692.625 1225.360 ;
      LAYER met2 ;
        RECT 692.625 843.510 693.095 1225.360 ;
      LAYER met2 ;
        RECT 693.095 843.510 706.340 1225.360 ;
        RECT 692.360 841.730 706.340 843.510 ;
      LAYER met2 ;
        RECT 706.340 841.730 706.810 1227.140 ;
      LAYER met2 ;
        RECT 706.810 1226.590 723.795 1227.140 ;
        RECT 706.810 1225.360 722.655 1226.590 ;
        RECT 706.810 843.510 707.075 1225.360 ;
      LAYER met2 ;
        RECT 707.075 843.510 707.545 1225.360 ;
      LAYER met2 ;
        RECT 707.545 843.510 722.655 1225.360 ;
        RECT 706.810 842.280 722.655 843.510 ;
      LAYER met2 ;
        RECT 722.655 842.280 723.655 1226.590 ;
      LAYER met2 ;
        RECT 723.655 842.280 723.795 1226.590 ;
        RECT 706.810 841.730 723.795 842.280 ;
      LAYER met2 ;
        RECT 372.980 841.640 489.470 841.730 ;
      LAYER met2 ;
        RECT 489.470 841.640 723.795 841.730 ;
      LAYER met2 ;
        RECT 723.795 841.640 724.315 1227.230 ;
        RECT 724.465 1034.250 724.745 1034.620 ;
        RECT 372.980 841.480 486.265 841.640 ;
      LAYER met2 ;
        RECT 486.265 841.480 724.315 841.640 ;
      LAYER met2 ;
        RECT 372.980 840.500 484.205 841.480 ;
      LAYER met2 ;
        RECT 484.205 840.780 724.315 841.480 ;
        RECT 484.205 840.500 722.050 840.780 ;
      LAYER met2 ;
        RECT 722.050 840.500 724.315 840.780 ;
        RECT 372.980 828.870 680.000 840.500 ;
        RECT 372.980 827.890 484.205 828.870 ;
      LAYER met2 ;
        RECT 484.205 828.590 722.050 828.870 ;
      LAYER met2 ;
        RECT 722.050 828.590 724.315 828.870 ;
      LAYER met2 ;
        RECT 484.205 827.890 724.315 828.590 ;
      LAYER met2 ;
        RECT 372.980 827.730 486.265 827.890 ;
      LAYER met2 ;
        RECT 486.265 827.730 724.315 827.890 ;
      LAYER met2 ;
        RECT 372.980 827.640 489.470 827.730 ;
      LAYER met2 ;
        RECT 489.470 827.640 723.795 827.730 ;
      LAYER met2 ;
        RECT 372.980 825.860 677.910 827.640 ;
      LAYER met2 ;
        RECT 677.910 825.860 691.890 827.640 ;
      LAYER met2 ;
        RECT 372.980 444.010 678.645 825.860 ;
      LAYER met2 ;
        RECT 678.645 444.010 691.890 825.860 ;
      LAYER met2 ;
        RECT 372.980 442.230 677.910 444.010 ;
      LAYER met2 ;
        RECT 677.910 442.230 691.890 444.010 ;
      LAYER met2 ;
        RECT 691.890 442.230 692.360 827.640 ;
      LAYER met2 ;
        RECT 692.360 825.860 706.340 827.640 ;
        RECT 692.360 444.010 692.625 825.860 ;
      LAYER met2 ;
        RECT 692.625 444.010 693.095 825.860 ;
      LAYER met2 ;
        RECT 693.095 444.010 706.340 825.860 ;
        RECT 692.360 442.230 706.340 444.010 ;
      LAYER met2 ;
        RECT 706.340 442.230 706.810 827.640 ;
      LAYER met2 ;
        RECT 706.810 827.090 723.795 827.640 ;
        RECT 706.810 825.860 722.655 827.090 ;
        RECT 706.810 444.010 707.075 825.860 ;
      LAYER met2 ;
        RECT 707.075 444.010 707.545 825.860 ;
      LAYER met2 ;
        RECT 707.545 444.010 722.655 825.860 ;
        RECT 706.810 442.780 722.655 444.010 ;
      LAYER met2 ;
        RECT 722.655 442.780 723.655 827.090 ;
      LAYER met2 ;
        RECT 723.655 442.780 723.795 827.090 ;
        RECT 706.810 442.230 723.795 442.780 ;
      LAYER met2 ;
        RECT 372.980 442.140 489.470 442.230 ;
      LAYER met2 ;
        RECT 489.470 442.140 723.795 442.230 ;
      LAYER met2 ;
        RECT 723.795 442.140 724.315 827.730 ;
        RECT 724.465 634.750 724.745 635.120 ;
        RECT 372.980 441.980 486.265 442.140 ;
      LAYER met2 ;
        RECT 486.265 441.980 724.315 442.140 ;
      LAYER met2 ;
        RECT 372.980 441.000 484.205 441.980 ;
      LAYER met2 ;
        RECT 484.205 441.280 724.315 441.980 ;
        RECT 484.205 441.000 722.050 441.280 ;
      LAYER met2 ;
        RECT 722.050 441.000 724.315 441.280 ;
        RECT 372.980 427.870 680.000 441.000 ;
        RECT 372.980 426.890 484.205 427.870 ;
      LAYER met2 ;
        RECT 484.205 427.590 722.050 427.870 ;
      LAYER met2 ;
        RECT 722.050 427.590 724.315 427.870 ;
      LAYER met2 ;
        RECT 484.205 426.890 724.315 427.590 ;
      LAYER met2 ;
        RECT 372.980 426.730 486.265 426.890 ;
      LAYER met2 ;
        RECT 486.265 426.730 724.315 426.890 ;
      LAYER met2 ;
        RECT 372.980 426.640 489.470 426.730 ;
      LAYER met2 ;
        RECT 489.470 426.640 723.795 426.730 ;
      LAYER met2 ;
        RECT 372.980 424.860 677.910 426.640 ;
      LAYER met2 ;
        RECT 677.910 424.860 691.890 426.640 ;
      LAYER met2 ;
        RECT 372.980 43.010 678.645 424.860 ;
      LAYER met2 ;
        RECT 678.645 43.010 691.890 424.860 ;
      LAYER met2 ;
        RECT 372.980 41.230 677.910 43.010 ;
      LAYER met2 ;
        RECT 677.910 41.230 691.890 43.010 ;
      LAYER met2 ;
        RECT 691.890 41.230 692.360 426.640 ;
      LAYER met2 ;
        RECT 692.360 424.860 706.340 426.640 ;
        RECT 692.360 43.010 692.625 424.860 ;
      LAYER met2 ;
        RECT 692.625 43.010 693.095 424.860 ;
      LAYER met2 ;
        RECT 693.095 43.010 706.340 424.860 ;
        RECT 692.360 41.230 706.340 43.010 ;
      LAYER met2 ;
        RECT 706.340 41.230 706.810 426.640 ;
      LAYER met2 ;
        RECT 706.810 426.090 723.795 426.640 ;
        RECT 706.810 424.860 722.655 426.090 ;
        RECT 706.810 43.010 707.075 424.860 ;
      LAYER met2 ;
        RECT 707.075 43.010 707.545 424.860 ;
      LAYER met2 ;
        RECT 707.545 43.010 722.655 424.860 ;
        RECT 706.810 41.780 722.655 43.010 ;
      LAYER met2 ;
        RECT 722.655 41.780 723.655 426.090 ;
      LAYER met2 ;
        RECT 723.655 41.780 723.795 426.090 ;
        RECT 706.810 41.230 723.795 41.780 ;
      LAYER met2 ;
        RECT 372.980 41.140 489.470 41.230 ;
      LAYER met2 ;
        RECT 489.470 41.140 723.795 41.230 ;
      LAYER met2 ;
        RECT 723.795 41.140 724.315 426.730 ;
        RECT 724.465 233.750 724.745 234.120 ;
        RECT 372.980 40.980 486.265 41.140 ;
      LAYER met2 ;
        RECT 486.265 40.980 724.315 41.140 ;
      LAYER met2 ;
        RECT 372.980 40.000 484.205 40.980 ;
      LAYER met2 ;
        RECT 484.205 40.280 724.315 40.980 ;
        RECT 484.205 40.000 722.050 40.280 ;
      LAYER met2 ;
        RECT 722.050 40.000 724.315 40.280 ;
        RECT 372.980 30.140 680.000 40.000 ;
        RECT 372.980 4.920 408.900 30.140 ;
        RECT 411.220 30.000 508.900 30.140 ;
        RECT 411.220 4.920 420.660 30.000 ;
        RECT 422.980 4.920 458.900 30.000 ;
        RECT 461.220 4.920 470.660 30.000 ;
        RECT 472.980 4.920 508.900 30.000 ;
        RECT 511.220 4.920 520.660 30.140 ;
        RECT 522.980 4.920 558.900 30.140 ;
        RECT 561.220 4.920 570.660 30.140 ;
        RECT 572.980 4.920 608.900 30.140 ;
        RECT 611.220 4.920 620.660 30.140 ;
        RECT 622.980 4.920 658.900 30.140 ;
        RECT 661.220 4.920 670.660 30.140 ;
        RECT 672.980 4.920 680.000 30.140 ;
        RECT 10.130 4.280 680.000 4.920 ;
        RECT 10.130 3.070 189.790 4.280 ;
        RECT 190.630 3.070 194.390 4.280 ;
        RECT 195.230 3.070 198.990 4.280 ;
        RECT 199.830 3.070 203.590 4.280 ;
        RECT 204.430 3.070 208.190 4.280 ;
        RECT 209.030 3.070 212.790 4.280 ;
        RECT 213.630 3.070 217.390 4.280 ;
        RECT 218.230 3.070 221.990 4.280 ;
        RECT 222.830 3.070 226.590 4.280 ;
        RECT 227.430 3.070 231.190 4.280 ;
        RECT 232.030 3.070 235.790 4.280 ;
        RECT 236.630 3.070 240.390 4.280 ;
        RECT 241.230 3.070 244.990 4.280 ;
        RECT 245.830 3.070 249.590 4.280 ;
        RECT 250.430 3.070 254.190 4.280 ;
        RECT 255.030 3.070 258.790 4.280 ;
        RECT 259.630 3.070 263.390 4.280 ;
        RECT 264.230 3.070 267.990 4.280 ;
        RECT 268.830 3.070 272.590 4.280 ;
        RECT 273.430 3.070 277.190 4.280 ;
        RECT 278.030 3.070 281.790 4.280 ;
        RECT 282.630 3.070 286.390 4.280 ;
        RECT 287.230 3.070 290.990 4.280 ;
        RECT 291.830 3.070 295.590 4.280 ;
        RECT 296.430 3.070 300.190 4.280 ;
        RECT 301.030 3.070 304.790 4.280 ;
        RECT 305.630 3.070 309.390 4.280 ;
        RECT 310.230 3.070 313.990 4.280 ;
        RECT 314.830 3.070 318.590 4.280 ;
        RECT 319.430 3.070 323.190 4.280 ;
        RECT 324.030 3.070 327.790 4.280 ;
        RECT 328.630 3.070 332.390 4.280 ;
        RECT 333.230 3.070 336.990 4.280 ;
        RECT 337.830 3.070 341.590 4.280 ;
        RECT 342.430 3.070 346.190 4.280 ;
        RECT 347.030 3.070 350.790 4.280 ;
        RECT 351.630 3.070 355.390 4.280 ;
        RECT 356.230 3.070 359.990 4.280 ;
        RECT 360.830 3.070 364.590 4.280 ;
        RECT 365.430 3.070 369.190 4.280 ;
        RECT 370.030 3.070 373.790 4.280 ;
        RECT 374.630 3.070 378.390 4.280 ;
        RECT 379.230 3.070 382.990 4.280 ;
        RECT 383.830 3.070 387.590 4.280 ;
        RECT 388.430 3.070 392.190 4.280 ;
        RECT 393.030 3.070 396.790 4.280 ;
        RECT 397.630 3.070 401.390 4.280 ;
        RECT 402.230 3.070 405.990 4.280 ;
        RECT 406.830 3.070 410.590 4.280 ;
        RECT 411.430 3.070 415.190 4.280 ;
        RECT 416.030 3.070 419.790 4.280 ;
        RECT 420.630 3.070 424.390 4.280 ;
        RECT 425.230 3.070 428.990 4.280 ;
        RECT 429.830 3.070 433.590 4.280 ;
        RECT 434.430 3.070 438.190 4.280 ;
        RECT 439.030 3.070 442.790 4.280 ;
        RECT 443.630 3.070 447.390 4.280 ;
        RECT 448.230 3.070 451.990 4.280 ;
        RECT 452.830 3.070 456.590 4.280 ;
        RECT 457.430 3.070 461.190 4.280 ;
        RECT 462.030 3.070 465.790 4.280 ;
        RECT 466.630 3.070 470.390 4.280 ;
        RECT 471.230 3.070 474.990 4.280 ;
        RECT 475.830 3.070 479.590 4.280 ;
        RECT 480.430 3.070 484.190 4.280 ;
        RECT 485.030 3.070 488.790 4.280 ;
        RECT 489.630 3.070 493.390 4.280 ;
        RECT 494.230 3.070 497.990 4.280 ;
        RECT 498.830 3.070 502.590 4.280 ;
        RECT 503.430 3.070 507.190 4.280 ;
        RECT 508.030 3.070 511.790 4.280 ;
        RECT 512.630 3.070 516.390 4.280 ;
        RECT 517.230 3.070 520.990 4.280 ;
        RECT 521.830 3.070 525.590 4.280 ;
        RECT 526.430 3.070 530.190 4.280 ;
        RECT 531.030 3.070 534.790 4.280 ;
        RECT 535.630 3.070 539.390 4.280 ;
        RECT 540.230 3.070 543.990 4.280 ;
        RECT 544.830 3.070 548.590 4.280 ;
        RECT 549.430 3.070 553.190 4.280 ;
        RECT 554.030 3.070 557.790 4.280 ;
        RECT 558.630 3.070 562.390 4.280 ;
        RECT 563.230 3.070 566.990 4.280 ;
        RECT 567.830 3.070 571.590 4.280 ;
        RECT 572.430 3.070 576.190 4.280 ;
        RECT 577.030 3.070 580.790 4.280 ;
        RECT 581.630 3.070 585.390 4.280 ;
        RECT 586.230 3.070 589.990 4.280 ;
        RECT 590.830 3.070 594.590 4.280 ;
        RECT 595.430 3.070 599.190 4.280 ;
        RECT 600.030 3.070 603.790 4.280 ;
        RECT 604.630 3.070 608.390 4.280 ;
        RECT 609.230 3.070 612.990 4.280 ;
        RECT 613.830 3.070 617.590 4.280 ;
        RECT 618.430 3.070 622.190 4.280 ;
        RECT 623.030 3.070 626.790 4.280 ;
        RECT 627.630 3.070 631.390 4.280 ;
        RECT 632.230 3.070 635.990 4.280 ;
        RECT 636.830 3.070 640.590 4.280 ;
        RECT 641.430 3.070 645.190 4.280 ;
        RECT 646.030 3.070 649.790 4.280 ;
        RECT 650.630 3.070 654.390 4.280 ;
        RECT 655.230 3.070 658.990 4.280 ;
        RECT 659.830 3.070 663.590 4.280 ;
        RECT 664.430 3.070 668.190 4.280 ;
        RECT 669.030 3.070 672.790 4.280 ;
        RECT 673.630 3.070 680.000 4.280 ;
      LAYER met3 ;
        RECT 10.105 1623.480 680.000 1629.105 ;
        RECT 675.460 1620.920 680.000 1623.480 ;
        RECT 10.105 1611.720 680.000 1620.920 ;
        RECT 675.460 1609.160 680.000 1611.720 ;
        RECT 10.105 1573.480 680.000 1609.160 ;
        RECT 675.460 1570.920 680.000 1573.480 ;
        RECT 10.105 1561.720 680.000 1570.920 ;
        RECT 675.460 1559.160 680.000 1561.720 ;
        RECT 10.105 1523.480 680.000 1559.160 ;
        RECT 675.460 1520.920 680.000 1523.480 ;
        RECT 10.105 1511.720 680.000 1520.920 ;
        RECT 675.460 1509.160 680.000 1511.720 ;
        RECT 10.105 1473.480 680.000 1509.160 ;
        RECT 675.460 1470.920 680.000 1473.480 ;
        RECT 10.105 1461.720 680.000 1470.920 ;
        RECT 675.460 1459.160 680.000 1461.720 ;
        RECT 10.105 1434.385 680.000 1459.160 ;
        RECT 724.440 1434.385 724.770 1434.400 ;
        RECT 10.105 1434.085 724.770 1434.385 ;
        RECT 10.105 1423.480 680.000 1434.085 ;
        RECT 724.440 1434.070 724.770 1434.085 ;
        RECT 675.460 1420.920 680.000 1423.480 ;
        RECT 10.105 1411.720 680.000 1420.920 ;
        RECT 675.460 1409.160 680.000 1411.720 ;
        RECT 10.105 1373.480 680.000 1409.160 ;
        RECT 675.460 1370.920 680.000 1373.480 ;
        RECT 10.105 1361.720 680.000 1370.920 ;
        RECT 675.460 1359.160 680.000 1361.720 ;
        RECT 10.105 1323.480 680.000 1359.160 ;
        RECT 675.460 1320.920 680.000 1323.480 ;
        RECT 10.105 1311.720 680.000 1320.920 ;
        RECT 675.460 1309.160 680.000 1311.720 ;
        RECT 10.105 1273.480 680.000 1309.160 ;
        RECT 675.460 1270.920 680.000 1273.480 ;
        RECT 10.105 1261.720 680.000 1270.920 ;
        RECT 675.460 1259.160 680.000 1261.720 ;
        RECT 10.105 1223.480 680.000 1259.160 ;
        RECT 675.460 1220.920 680.000 1223.480 ;
        RECT 10.105 1211.720 680.000 1220.920 ;
        RECT 675.460 1209.160 680.000 1211.720 ;
        RECT 10.105 1173.480 680.000 1209.160 ;
        RECT 675.460 1170.920 680.000 1173.480 ;
        RECT 10.105 1161.720 680.000 1170.920 ;
        RECT 675.460 1159.160 680.000 1161.720 ;
        RECT 10.105 1123.480 680.000 1159.160 ;
        RECT 675.460 1120.920 680.000 1123.480 ;
        RECT 10.105 1111.720 680.000 1120.920 ;
        RECT 675.460 1109.160 680.000 1111.720 ;
        RECT 10.105 1073.480 680.000 1109.160 ;
        RECT 675.460 1070.920 680.000 1073.480 ;
        RECT 10.105 1061.720 680.000 1070.920 ;
        RECT 675.460 1059.160 680.000 1061.720 ;
        RECT 10.105 1034.585 680.000 1059.160 ;
        RECT 724.440 1034.585 724.770 1034.600 ;
        RECT 10.105 1034.285 724.770 1034.585 ;
        RECT 10.105 1023.480 680.000 1034.285 ;
        RECT 724.440 1034.270 724.770 1034.285 ;
        RECT 675.460 1020.920 680.000 1023.480 ;
        RECT 10.105 1011.720 680.000 1020.920 ;
        RECT 675.460 1009.160 680.000 1011.720 ;
        RECT 10.105 973.480 680.000 1009.160 ;
        RECT 675.460 970.920 680.000 973.480 ;
        RECT 10.105 961.720 680.000 970.920 ;
        RECT 675.460 959.160 680.000 961.720 ;
        RECT 10.105 923.480 680.000 959.160 ;
        RECT 675.460 920.920 680.000 923.480 ;
        RECT 10.105 911.720 680.000 920.920 ;
        RECT 675.460 909.160 680.000 911.720 ;
        RECT 10.105 873.480 680.000 909.160 ;
        RECT 675.460 870.920 680.000 873.480 ;
        RECT 10.105 861.720 680.000 870.920 ;
        RECT 675.460 859.160 680.000 861.720 ;
        RECT 10.105 823.480 680.000 859.160 ;
        RECT 675.460 820.920 680.000 823.480 ;
        RECT 10.105 811.720 680.000 820.920 ;
        RECT 675.460 809.160 680.000 811.720 ;
        RECT 10.105 773.480 680.000 809.160 ;
        RECT 675.460 770.920 680.000 773.480 ;
        RECT 10.105 761.720 680.000 770.920 ;
        RECT 675.460 759.160 680.000 761.720 ;
        RECT 10.105 723.480 680.000 759.160 ;
        RECT 675.460 720.920 680.000 723.480 ;
        RECT 10.105 711.720 680.000 720.920 ;
        RECT 675.460 709.160 680.000 711.720 ;
        RECT 10.105 673.480 680.000 709.160 ;
        RECT 675.460 670.920 680.000 673.480 ;
        RECT 10.105 661.720 680.000 670.920 ;
        RECT 675.460 659.160 680.000 661.720 ;
        RECT 10.105 635.085 680.000 659.160 ;
        RECT 724.440 635.085 724.770 635.100 ;
        RECT 10.105 634.785 724.770 635.085 ;
        RECT 10.105 623.480 680.000 634.785 ;
        RECT 724.440 634.770 724.770 634.785 ;
        RECT 675.460 620.920 680.000 623.480 ;
        RECT 10.105 611.720 680.000 620.920 ;
        RECT 675.460 609.160 680.000 611.720 ;
        RECT 10.105 573.480 680.000 609.160 ;
        RECT 675.460 570.920 680.000 573.480 ;
        RECT 10.105 561.720 680.000 570.920 ;
        RECT 675.460 559.160 680.000 561.720 ;
        RECT 10.105 523.480 680.000 559.160 ;
        RECT 675.460 520.920 680.000 523.480 ;
        RECT 10.105 511.720 680.000 520.920 ;
        RECT 675.460 509.160 680.000 511.720 ;
        RECT 10.105 473.480 680.000 509.160 ;
        RECT 675.460 470.920 680.000 473.480 ;
        RECT 10.105 461.720 680.000 470.920 ;
        RECT 675.460 459.160 680.000 461.720 ;
        RECT 10.105 423.480 680.000 459.160 ;
        RECT 675.460 420.920 680.000 423.480 ;
        RECT 10.105 411.720 680.000 420.920 ;
        RECT 675.460 409.160 680.000 411.720 ;
        RECT 10.105 373.480 680.000 409.160 ;
        RECT 675.460 370.920 680.000 373.480 ;
        RECT 10.105 361.720 680.000 370.920 ;
        RECT 675.460 359.160 680.000 361.720 ;
        RECT 10.105 323.480 680.000 359.160 ;
        RECT 675.460 320.920 680.000 323.480 ;
        RECT 10.105 311.720 680.000 320.920 ;
        RECT 675.460 309.160 680.000 311.720 ;
        RECT 10.105 273.480 680.000 309.160 ;
        RECT 675.460 270.920 680.000 273.480 ;
        RECT 10.105 261.720 680.000 270.920 ;
        RECT 675.460 259.160 680.000 261.720 ;
        RECT 10.105 234.085 680.000 259.160 ;
        RECT 724.440 234.085 724.770 234.100 ;
        RECT 10.105 233.785 724.770 234.085 ;
        RECT 10.105 223.480 680.000 233.785 ;
        RECT 724.440 233.770 724.770 233.785 ;
        RECT 675.460 220.920 680.000 223.480 ;
        RECT 10.105 211.720 680.000 220.920 ;
        RECT 675.460 209.160 680.000 211.720 ;
        RECT 10.105 173.480 680.000 209.160 ;
        RECT 675.460 170.920 680.000 173.480 ;
        RECT 10.105 161.720 680.000 170.920 ;
        RECT 675.460 159.160 680.000 161.720 ;
        RECT 10.105 123.480 680.000 159.160 ;
        RECT 675.460 120.920 680.000 123.480 ;
        RECT 10.105 111.720 680.000 120.920 ;
        RECT 675.460 109.160 680.000 111.720 ;
        RECT 10.105 73.480 680.000 109.160 ;
        RECT 675.460 70.920 680.000 73.480 ;
        RECT 10.105 61.720 680.000 70.920 ;
        RECT 675.460 59.160 680.000 61.720 ;
        RECT 10.105 26.015 680.000 59.160 ;
      LAYER met4 ;
        RECT 286.415 26.015 293.110 1628.425 ;
        RECT 297.010 26.015 308.110 1628.425 ;
        RECT 312.010 26.015 323.110 1628.425 ;
        RECT 327.010 26.015 338.110 1628.425 ;
        RECT 342.010 26.015 353.110 1628.425 ;
        RECT 357.010 26.015 368.110 1628.425 ;
        RECT 372.010 26.015 383.110 1628.425 ;
        RECT 387.010 26.015 398.110 1628.425 ;
        RECT 402.010 26.015 413.110 1628.425 ;
        RECT 417.010 26.015 428.110 1628.425 ;
        RECT 432.010 26.015 443.110 1628.425 ;
        RECT 447.010 26.015 451.425 1628.425 ;
  END
END CF_SRAM_8192x32
END LIBRARY

